# Local copy of test/gf180/gf180mcu_fd_io.lef with the duplicate macro bodies
# removed.  That file declares every one of its 14 macros twice with different
# geometry, and odb appends the second body to the first instead of replacing
# it, so gf180mcu_fd_io__dvdd ends up with the second body's Metal2 blanket
# (to local y 348.720) underneath the first body's pin openings (from local
# y 345.345).  Each body on its own keeps a legal 0.300 um gap.  The pad tests
# here need obstructions that are consistent with their own pins, so they read
# this copy; the odb behaviour is a separate issue.
VERSION 5.7 ;
  NOWIREEXTENSIONATPIN ON ;
  DIVIDERCHAR "/" ;
  BUSBITCHARS "[]" ;
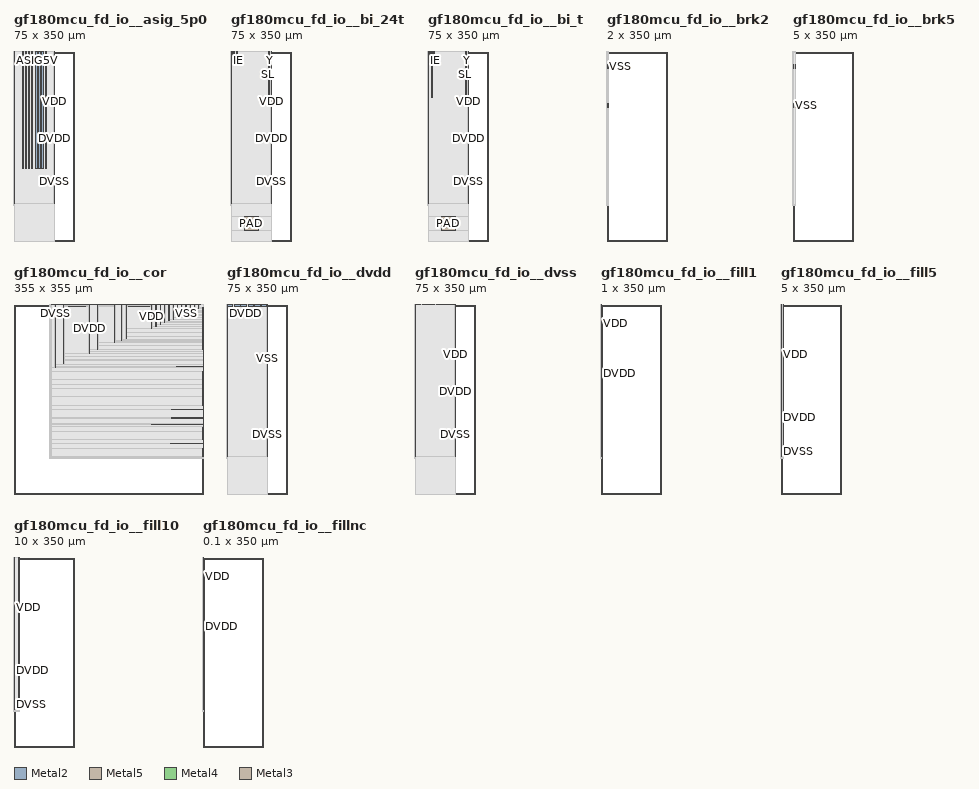
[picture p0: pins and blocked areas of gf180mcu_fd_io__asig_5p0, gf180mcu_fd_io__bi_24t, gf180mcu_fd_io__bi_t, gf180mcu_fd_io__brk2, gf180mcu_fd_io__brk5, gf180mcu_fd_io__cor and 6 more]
MACRO gf180mcu_fd_io__asig_5p0
  CLASS PAD INOUT ;
  FOREIGN gf180mcu_fd_io__asig_5p0 ;
  ORIGIN 0.000 0.000 ;
  SIZE 75.000 BY 350.000 ;
  SYMMETRY X Y R90 ;
  PIN ASIG5V
    DIRECTION INOUT ;
    USE SIGNAL ;
    PORT
      LAYER Metal2 ;
        RECT 15.340 134.370 17.880 350.000 ;
    END
    PORT
      LAYER Metal2 ;
        RECT 21.020 134.370 23.560 350.000 ;
    END
    PORT
      LAYER Metal2 ;
        RECT 26.700 134.370 29.240 350.000 ;
    END
    PORT
      LAYER Metal2 ;
        RECT 32.380 134.370 34.920 350.000 ;
    END
    PORT
      LAYER Metal2 ;
        RECT 40.080 134.370 42.620 350.000 ;
    END
    PORT
      LAYER Metal2 ;
        RECT 45.760 134.370 48.300 350.000 ;
    END
    PORT
      LAYER Metal2 ;
        RECT 51.440 134.370 53.980 350.000 ;
    END
    PORT
      LAYER Metal2 ;
        RECT 57.120 134.370 59.660 350.000 ;
    END
  END ASIG5V
  PIN DVDD
    DIRECTION INOUT ;
    USE POWER ;
    PORT
      LAYER Metal5 ;
        RECT 74.000 118.000 75.000 125.000 ;
    END
    PORT
      LAYER Metal5 ;
        RECT 74.000 182.000 75.000 197.000 ;
    END
    PORT
      LAYER Metal5 ;
        RECT 74.000 166.000 75.000 181.000 ;
    END
    PORT
      LAYER Metal5 ;
        RECT 74.000 150.000 75.000 165.000 ;
    END
    PORT
      LAYER Metal5 ;
        RECT 74.000 134.000 75.000 149.000 ;
    END
    PORT
      LAYER Metal5 ;
        RECT 74.000 214.000 75.000 229.000 ;
    END
    PORT
      LAYER Metal5 ;
        RECT 74.000 206.000 75.000 213.000 ;
    END
    PORT
      LAYER Metal5 ;
        RECT 74.000 278.000 75.000 285.000 ;
    END
    PORT
      LAYER Metal5 ;
        RECT 74.000 270.000 75.000 277.000 ;
    END
    PORT
      LAYER Metal5 ;
        RECT 74.000 262.000 75.000 269.000 ;
    END
    PORT
      LAYER Metal5 ;
        RECT 74.000 294.000 75.000 301.000 ;
    END
    PORT
      LAYER Metal5 ;
        RECT 74.000 334.000 75.000 341.000 ;
    END
    PORT
      LAYER Metal4 ;
        RECT 74.000 118.000 75.000 125.000 ;
    END
    PORT
      LAYER Metal4 ;
        RECT 74.000 182.000 75.000 197.000 ;
    END
    PORT
      LAYER Metal4 ;
        RECT 74.000 166.000 75.000 181.000 ;
    END
    PORT
      LAYER Metal4 ;
        RECT 74.000 150.000 75.000 165.000 ;
    END
    PORT
      LAYER Metal4 ;
        RECT 74.000 134.000 75.000 149.000 ;
    END
    PORT
      LAYER Metal4 ;
        RECT 74.000 214.000 75.000 229.000 ;
    END
    PORT
      LAYER Metal4 ;
        RECT 74.000 206.000 75.000 213.000 ;
    END
    PORT
      LAYER Metal4 ;
        RECT 74.000 278.000 75.000 285.000 ;
    END
    PORT
      LAYER Metal4 ;
        RECT 74.000 270.000 75.000 277.000 ;
    END
    PORT
      LAYER Metal4 ;
        RECT 74.000 262.000 75.000 269.000 ;
    END
    PORT
      LAYER Metal4 ;
        RECT 74.000 294.000 75.000 301.000 ;
    END
    PORT
      LAYER Metal4 ;
        RECT 74.000 334.000 75.000 341.000 ;
    END
    PORT
      LAYER Metal3 ;
        RECT 74.000 118.000 75.000 125.000 ;
    END
    PORT
      LAYER Metal3 ;
        RECT 74.000 182.000 75.000 197.000 ;
    END
    PORT
      LAYER Metal3 ;
        RECT 74.000 166.000 75.000 181.000 ;
    END
    PORT
      LAYER Metal3 ;
        RECT 74.000 150.000 75.000 165.000 ;
    END
    PORT
      LAYER Metal3 ;
        RECT 74.000 134.000 75.000 149.000 ;
    END
    PORT
      LAYER Metal3 ;
        RECT 74.000 214.000 75.000 229.000 ;
    END
    PORT
      LAYER Metal3 ;
        RECT 74.000 206.000 75.000 213.000 ;
    END
    PORT
      LAYER Metal3 ;
        RECT 74.000 278.000 75.000 285.000 ;
    END
    PORT
      LAYER Metal3 ;
        RECT 74.000 270.000 75.000 277.000 ;
    END
    PORT
      LAYER Metal3 ;
        RECT 74.000 262.000 75.000 269.000 ;
    END
    PORT
      LAYER Metal3 ;
        RECT 74.000 294.000 75.000 301.000 ;
    END
    PORT
      LAYER Metal3 ;
        RECT 74.000 334.000 75.000 341.000 ;
    END
    PORT
      LAYER Metal3 ;
        RECT 0.000 334.000 1.000 341.000 ;
    END
    PORT
      LAYER Metal3 ;
        RECT 0.000 294.000 1.000 301.000 ;
    END
    PORT
      LAYER Metal3 ;
        RECT 0.000 262.000 1.000 269.000 ;
    END
    PORT
      LAYER Metal3 ;
        RECT 0.000 270.000 1.000 277.000 ;
    END
    PORT
      LAYER Metal3 ;
        RECT 0.000 278.000 1.000 285.000 ;
    END
    PORT
      LAYER Metal3 ;
        RECT 0.000 206.000 1.000 213.000 ;
    END
    PORT
      LAYER Metal3 ;
        RECT 0.000 214.000 1.000 229.000 ;
    END
    PORT
      LAYER Metal3 ;
        RECT 0.000 134.000 1.000 149.000 ;
    END
    PORT
      LAYER Metal3 ;
        RECT 0.000 150.000 1.000 165.000 ;
    END
    PORT
      LAYER Metal3 ;
        RECT 0.000 166.000 1.000 181.000 ;
    END
    PORT
      LAYER Metal3 ;
        RECT 0.000 182.000 1.000 197.000 ;
    END
    PORT
      LAYER Metal5 ;
        RECT 0.000 334.000 1.000 341.000 ;
    END
    PORT
      LAYER Metal5 ;
        RECT 0.000 294.000 1.000 301.000 ;
    END
    PORT
      LAYER Metal5 ;
        RECT 0.000 262.000 1.000 269.000 ;
    END
    PORT
      LAYER Metal5 ;
        RECT 0.000 270.000 1.000 277.000 ;
    END
    PORT
      LAYER Metal5 ;
        RECT 0.000 278.000 1.000 285.000 ;
    END
    PORT
      LAYER Metal5 ;
        RECT 0.000 206.000 1.000 213.000 ;
    END
    PORT
      LAYER Metal5 ;
        RECT 0.000 214.000 1.000 229.000 ;
    END
    PORT
      LAYER Metal5 ;
        RECT 0.000 134.000 1.000 149.000 ;
    END
    PORT
      LAYER Metal5 ;
        RECT 0.000 150.000 1.000 165.000 ;
    END
    PORT
      LAYER Metal5 ;
        RECT 0.000 166.000 1.000 181.000 ;
    END
    PORT
      LAYER Metal5 ;
        RECT 0.000 182.000 1.000 197.000 ;
    END
    PORT
      LAYER Metal4 ;
        RECT 0.000 334.000 1.000 341.000 ;
    END
    PORT
      LAYER Metal4 ;
        RECT 0.000 294.000 1.000 301.000 ;
    END
    PORT
      LAYER Metal4 ;
        RECT 0.000 262.000 1.000 269.000 ;
    END
    PORT
      LAYER Metal4 ;
        RECT 0.000 270.000 1.000 277.000 ;
    END
    PORT
      LAYER Metal4 ;
        RECT 0.000 278.000 1.000 285.000 ;
    END
    PORT
      LAYER Metal4 ;
        RECT 0.000 206.000 1.000 213.000 ;
    END
    PORT
      LAYER Metal4 ;
        RECT 0.000 214.000 1.000 229.000 ;
    END
    PORT
      LAYER Metal4 ;
        RECT 0.000 134.000 1.000 149.000 ;
    END
    PORT
      LAYER Metal4 ;
        RECT 0.000 150.000 1.000 165.000 ;
    END
    PORT
      LAYER Metal4 ;
        RECT 0.000 166.000 1.000 181.000 ;
    END
    PORT
      LAYER Metal4 ;
        RECT 0.000 182.000 1.000 197.000 ;
    END
    PORT
      LAYER Metal4 ;
        RECT 0.000 118.000 1.000 125.000 ;
    END
    PORT
      LAYER Metal5 ;
        RECT 0.000 118.000 1.000 125.000 ;
    END
    PORT
      LAYER Metal3 ;
        RECT 0.000 118.000 1.000 125.000 ;
    END
  END DVDD
  PIN DVSS
    DIRECTION INOUT ;
    USE GROUND ;
    PORT
      LAYER Metal5 ;
        RECT 74.000 102.000 75.000 117.000 ;
    END
    PORT
      LAYER Metal5 ;
        RECT 74.000 86.000 75.000 101.000 ;
    END
    PORT
      LAYER Metal5 ;
        RECT 74.000 70.000 75.000 85.000 ;
    END
    PORT
      LAYER Metal5 ;
        RECT 74.000 126.000 75.000 133.000 ;
    END
    PORT
      LAYER Metal5 ;
        RECT 74.000 198.000 75.000 205.000 ;
    END
    PORT
      LAYER Metal5 ;
        RECT 74.000 230.000 75.000 245.000 ;
    END
    PORT
      LAYER Metal5 ;
        RECT 74.000 286.000 75.000 293.000 ;
    END
    PORT
      LAYER Metal5 ;
        RECT 74.000 302.000 75.000 309.000 ;
    END
    PORT
      LAYER Metal5 ;
        RECT 74.000 326.000 75.000 333.000 ;
    END
    PORT
      LAYER Metal5 ;
        RECT 74.000 342.000 75.000 348.390 ;
    END
    PORT
      LAYER Metal4 ;
        RECT 74.000 102.000 75.000 117.000 ;
    END
    PORT
      LAYER Metal4 ;
        RECT 74.000 86.000 75.000 101.000 ;
    END
    PORT
      LAYER Metal4 ;
        RECT 74.000 70.000 75.000 85.000 ;
    END
    PORT
      LAYER Metal4 ;
        RECT 74.000 126.000 75.000 133.000 ;
    END
    PORT
      LAYER Metal4 ;
        RECT 74.000 198.000 75.000 205.000 ;
    END
    PORT
      LAYER Metal4 ;
        RECT 74.000 230.000 75.000 245.000 ;
    END
    PORT
      LAYER Metal4 ;
        RECT 74.000 286.000 75.000 293.000 ;
    END
    PORT
      LAYER Metal4 ;
        RECT 74.000 302.000 75.000 309.000 ;
    END
    PORT
      LAYER Metal4 ;
        RECT 74.000 326.000 75.000 333.000 ;
    END
    PORT
      LAYER Metal4 ;
        RECT 74.000 342.000 75.000 348.390 ;
    END
    PORT
      LAYER Metal3 ;
        RECT 74.000 102.000 75.000 117.000 ;
    END
    PORT
      LAYER Metal3 ;
        RECT 74.000 86.000 75.000 101.000 ;
    END
    PORT
      LAYER Metal3 ;
        RECT 74.000 70.000 75.000 85.000 ;
    END
    PORT
      LAYER Metal3 ;
        RECT 74.000 126.000 75.000 133.000 ;
    END
    PORT
      LAYER Metal3 ;
        RECT 74.000 198.000 75.000 205.000 ;
    END
    PORT
      LAYER Metal3 ;
        RECT 74.000 230.000 75.000 245.000 ;
    END
    PORT
      LAYER Metal3 ;
        RECT 74.000 286.000 75.000 293.000 ;
    END
    PORT
      LAYER Metal3 ;
        RECT 74.000 302.000 75.000 309.000 ;
    END
    PORT
      LAYER Metal3 ;
        RECT 74.000 326.000 75.000 333.000 ;
    END
    PORT
      LAYER Metal3 ;
        RECT 74.000 342.000 75.000 348.390 ;
    END
    PORT
      LAYER Metal3 ;
        RECT 0.000 342.000 1.000 348.390 ;
    END
    PORT
      LAYER Metal3 ;
        RECT 0.000 326.000 1.000 333.000 ;
    END
    PORT
      LAYER Metal3 ;
        RECT 0.000 302.000 1.000 309.000 ;
    END
    PORT
      LAYER Metal3 ;
        RECT 0.000 286.000 1.000 293.000 ;
    END
    PORT
      LAYER Metal3 ;
        RECT 0.000 230.000 1.000 245.000 ;
    END
    PORT
      LAYER Metal3 ;
        RECT 0.000 198.000 1.000 205.000 ;
    END
    PORT
      LAYER Metal3 ;
        RECT 0.000 126.000 1.000 133.000 ;
    END
    PORT
      LAYER Metal3 ;
        RECT 0.000 70.000 1.000 85.000 ;
    END
    PORT
      LAYER Metal3 ;
        RECT 0.000 86.000 1.000 101.000 ;
    END
    PORT
      LAYER Metal5 ;
        RECT 0.000 342.000 1.000 348.390 ;
    END
    PORT
      LAYER Metal5 ;
        RECT 0.000 326.000 1.000 333.000 ;
    END
    PORT
      LAYER Metal5 ;
        RECT 0.000 302.000 1.000 309.000 ;
    END
    PORT
      LAYER Metal5 ;
        RECT 0.000 286.000 1.000 293.000 ;
    END
    PORT
      LAYER Metal5 ;
        RECT 0.000 230.000 1.000 245.000 ;
    END
    PORT
      LAYER Metal5 ;
        RECT 0.000 198.000 1.000 205.000 ;
    END
    PORT
      LAYER Metal5 ;
        RECT 0.000 126.000 1.000 133.000 ;
    END
    PORT
      LAYER Metal5 ;
        RECT 0.000 70.000 1.000 85.000 ;
    END
    PORT
      LAYER Metal5 ;
        RECT 0.000 86.000 1.000 101.000 ;
    END
    PORT
      LAYER Metal4 ;
        RECT 0.000 342.000 1.000 348.390 ;
    END
    PORT
      LAYER Metal4 ;
        RECT 0.000 326.000 1.000 333.000 ;
    END
    PORT
      LAYER Metal4 ;
        RECT 0.000 302.000 1.000 309.000 ;
    END
    PORT
      LAYER Metal4 ;
        RECT 0.000 286.000 1.000 293.000 ;
    END
    PORT
      LAYER Metal4 ;
        RECT 0.000 230.000 1.000 245.000 ;
    END
    PORT
      LAYER Metal4 ;
        RECT 0.000 198.000 1.000 205.000 ;
    END
    PORT
      LAYER Metal4 ;
        RECT 0.000 126.000 1.000 133.000 ;
    END
    PORT
      LAYER Metal4 ;
        RECT 0.000 70.000 1.000 85.000 ;
    END
    PORT
      LAYER Metal4 ;
        RECT 0.000 86.000 1.000 101.000 ;
    END
    PORT
      LAYER Metal4 ;
        RECT 0.000 102.000 1.000 117.000 ;
    END
    PORT
      LAYER Metal5 ;
        RECT 0.000 102.000 1.000 117.000 ;
    END
    PORT
      LAYER Metal3 ;
        RECT 0.000 102.000 1.000 117.000 ;
    END
  END DVSS
  PIN VDD
    DIRECTION INOUT ;
    USE POWER ;
    PORT
      LAYER Metal5 ;
        RECT 74.000 254.000 75.000 261.000 ;
    END
    PORT
      LAYER Metal5 ;
        RECT 74.000 310.000 75.000 317.000 ;
    END
    PORT
      LAYER Metal4 ;
        RECT 74.000 254.000 75.000 261.000 ;
    END
    PORT
      LAYER Metal4 ;
        RECT 74.000 310.000 75.000 317.000 ;
    END
    PORT
      LAYER Metal3 ;
        RECT 74.000 254.000 75.000 261.000 ;
    END
    PORT
      LAYER Metal3 ;
        RECT 74.000 310.000 75.000 317.000 ;
    END
    PORT
      LAYER Metal3 ;
        RECT 0.000 310.000 1.000 317.000 ;
    END
    PORT
      LAYER Metal5 ;
        RECT 0.000 310.000 1.000 317.000 ;
    END
    PORT
      LAYER Metal4 ;
        RECT 0.000 310.000 1.000 317.000 ;
    END
    PORT
      LAYER Metal4 ;
        RECT 0.000 254.000 1.000 261.000 ;
    END
    PORT
      LAYER Metal5 ;
        RECT 0.000 254.000 1.000 261.000 ;
    END
    PORT
      LAYER Metal3 ;
        RECT 0.000 254.000 1.000 261.000 ;
    END
  END VDD
  PIN VSS
    DIRECTION INOUT ;
    USE GROUND ;
    PORT
      LAYER Metal5 ;
        RECT 74.000 246.000 75.000 253.000 ;
    END
    PORT
      LAYER Metal5 ;
        RECT 74.000 318.000 75.000 325.000 ;
    END
    PORT
      LAYER Metal4 ;
        RECT 74.000 246.000 75.000 253.000 ;
    END
    PORT
      LAYER Metal4 ;
        RECT 74.000 318.000 75.000 325.000 ;
    END
    PORT
      LAYER Metal3 ;
        RECT 74.000 246.000 75.000 253.000 ;
    END
    PORT
      LAYER Metal3 ;
        RECT 74.000 318.000 75.000 325.000 ;
    END
    PORT
      LAYER Metal3 ;
        RECT 0.000 318.000 1.000 325.000 ;
    END
    PORT
      LAYER Metal5 ;
        RECT 0.000 318.000 1.000 325.000 ;
    END
    PORT
      LAYER Metal4 ;
        RECT 0.000 318.000 1.000 325.000 ;
    END
    PORT
      LAYER Metal4 ;
        RECT 0.000 246.000 1.000 253.000 ;
    END
    PORT
      LAYER Metal5 ;
        RECT 0.000 246.000 1.000 253.000 ;
    END
    PORT
      LAYER Metal3 ;
        RECT 0.000 246.000 1.000 253.000 ;
    END
  END VSS
  OBS
      LAYER Metal1 ;
        RECT -0.160 65.540 75.160 349.785 ;
      LAYER Metal2 ;
        RECT 0.000 134.070 15.040 348.390 ;
        RECT 18.180 134.070 20.720 348.390 ;
        RECT 23.860 134.070 26.400 348.390 ;
        RECT 29.540 134.070 32.080 348.390 ;
        RECT 35.220 134.070 39.780 348.390 ;
        RECT 42.920 134.070 45.460 348.390 ;
        RECT 48.600 134.070 51.140 348.390 ;
        RECT 54.280 134.070 56.820 348.390 ;
        RECT 59.960 134.070 75.000 348.390 ;
        RECT 0.000 0.000 75.000 134.070 ;
      LAYER Metal3 ;
        RECT 1.300 341.700 73.700 348.390 ;
        RECT 1.000 341.300 74.000 341.700 ;
        RECT 1.300 333.700 73.700 341.300 ;
        RECT 1.000 333.300 74.000 333.700 ;
        RECT 1.300 325.700 73.700 333.300 ;
        RECT 1.000 325.300 74.000 325.700 ;
        RECT 1.300 317.700 73.700 325.300 ;
        RECT 1.000 317.300 74.000 317.700 ;
        RECT 1.300 309.700 73.700 317.300 ;
        RECT 1.000 309.300 74.000 309.700 ;
        RECT 1.300 301.700 73.700 309.300 ;
        RECT 1.000 301.300 74.000 301.700 ;
        RECT 1.300 293.700 73.700 301.300 ;
        RECT 1.000 293.300 74.000 293.700 ;
        RECT 1.300 285.700 73.700 293.300 ;
        RECT 1.000 285.300 74.000 285.700 ;
        RECT 1.300 277.700 73.700 285.300 ;
        RECT 1.000 277.300 74.000 277.700 ;
        RECT 1.300 269.700 73.700 277.300 ;
        RECT 1.000 269.300 74.000 269.700 ;
        RECT 1.300 261.700 73.700 269.300 ;
        RECT 1.000 261.300 74.000 261.700 ;
        RECT 1.300 253.700 73.700 261.300 ;
        RECT 1.000 253.300 74.000 253.700 ;
        RECT 1.300 245.700 73.700 253.300 ;
        RECT 1.000 245.300 74.000 245.700 ;
        RECT 1.300 229.700 73.700 245.300 ;
        RECT 1.000 229.300 74.000 229.700 ;
        RECT 1.300 213.700 73.700 229.300 ;
        RECT 1.000 213.300 74.000 213.700 ;
        RECT 1.300 205.700 73.700 213.300 ;
        RECT 1.000 205.300 74.000 205.700 ;
        RECT 1.300 197.700 73.700 205.300 ;
        RECT 1.000 197.300 74.000 197.700 ;
        RECT 1.300 181.700 73.700 197.300 ;
        RECT 1.000 181.300 74.000 181.700 ;
        RECT 1.300 165.700 73.700 181.300 ;
        RECT 1.000 165.300 74.000 165.700 ;
        RECT 1.300 149.700 73.700 165.300 ;
        RECT 1.000 149.300 74.000 149.700 ;
        RECT 1.300 133.700 73.700 149.300 ;
        RECT 1.000 133.300 74.000 133.700 ;
        RECT 1.300 125.700 73.700 133.300 ;
        RECT 1.000 125.300 74.000 125.700 ;
        RECT 1.300 117.700 73.700 125.300 ;
        RECT 1.000 117.300 74.000 117.700 ;
        RECT 1.300 101.700 73.700 117.300 ;
        RECT 1.000 101.300 74.000 101.700 ;
        RECT 1.300 85.700 73.700 101.300 ;
        RECT 1.000 85.300 74.000 85.700 ;
        RECT 1.300 69.700 73.700 85.300 ;
        RECT 1.000 0.000 74.000 69.700 ;
      LAYER Metal4 ;
        RECT 1.300 341.700 73.700 348.390 ;
        RECT 1.000 341.300 74.000 341.700 ;
        RECT 1.300 333.700 73.700 341.300 ;
        RECT 1.000 333.300 74.000 333.700 ;
        RECT 1.300 325.700 73.700 333.300 ;
        RECT 1.000 325.300 74.000 325.700 ;
        RECT 1.300 317.700 73.700 325.300 ;
        RECT 1.000 317.300 74.000 317.700 ;
        RECT 1.300 309.700 73.700 317.300 ;
        RECT 1.000 309.300 74.000 309.700 ;
        RECT 1.300 301.700 73.700 309.300 ;
        RECT 1.000 301.300 74.000 301.700 ;
        RECT 1.300 293.700 73.700 301.300 ;
        RECT 1.000 293.300 74.000 293.700 ;
        RECT 1.300 285.700 73.700 293.300 ;
        RECT 1.000 285.300 74.000 285.700 ;
        RECT 1.300 277.700 73.700 285.300 ;
        RECT 1.000 277.300 74.000 277.700 ;
        RECT 1.300 269.700 73.700 277.300 ;
        RECT 1.000 269.300 74.000 269.700 ;
        RECT 1.300 261.700 73.700 269.300 ;
        RECT 1.000 261.300 74.000 261.700 ;
        RECT 1.300 253.700 73.700 261.300 ;
        RECT 1.000 253.300 74.000 253.700 ;
        RECT 1.300 245.700 73.700 253.300 ;
        RECT 1.000 245.300 74.000 245.700 ;
        RECT 1.300 229.700 73.700 245.300 ;
        RECT 1.000 229.300 74.000 229.700 ;
        RECT 1.300 213.700 73.700 229.300 ;
        RECT 1.000 213.300 74.000 213.700 ;
        RECT 1.300 205.700 73.700 213.300 ;
        RECT 1.000 205.300 74.000 205.700 ;
        RECT 1.300 197.700 73.700 205.300 ;
        RECT 1.000 197.300 74.000 197.700 ;
        RECT 1.300 181.700 73.700 197.300 ;
        RECT 1.000 181.300 74.000 181.700 ;
        RECT 1.300 165.700 73.700 181.300 ;
        RECT 1.000 165.300 74.000 165.700 ;
        RECT 1.300 149.700 73.700 165.300 ;
        RECT 1.000 149.300 74.000 149.700 ;
        RECT 1.300 133.700 73.700 149.300 ;
        RECT 1.000 133.300 74.000 133.700 ;
        RECT 1.300 125.700 73.700 133.300 ;
        RECT 1.000 125.300 74.000 125.700 ;
        RECT 1.300 117.700 73.700 125.300 ;
        RECT 1.000 117.300 74.000 117.700 ;
        RECT 1.300 101.700 73.700 117.300 ;
        RECT 1.000 101.300 74.000 101.700 ;
        RECT 1.300 85.700 73.700 101.300 ;
        RECT 1.000 85.300 74.000 85.700 ;
        RECT 1.300 69.700 73.700 85.300 ;
        RECT 1.000 0.000 74.000 69.700 ;
      LAYER Metal5 ;
        RECT 1.500 69.500 73.500 348.390 ;
        RECT 1.000 0.000 74.000 69.500 ;
  END
END gf180mcu_fd_io__asig_5p0

#--------EOF---------

#--------EOF---------

MACRO gf180mcu_fd_io__bi_24t
  CLASS PAD INOUT ;
  FOREIGN gf180mcu_fd_io__bi_24t ;
  ORIGIN 0.000 0.000 ;
  SIZE 75.000 BY 350.000 ;
  SYMMETRY X Y R90 ;
  PIN A
    DIRECTION INPUT ;
    USE SIGNAL ;
    PORT
      LAYER Metal2 ;
        RECT 69.400 264.310 69.780 350.000 ;
    END
  END A
  PIN CS
    DIRECTION INPUT ;
    USE SIGNAL ;
    PORT
      LAYER Metal2 ;
        RECT 3.360 328.395 3.740 350.000 ;
    END
  END CS
  PIN DVDD
    DIRECTION INOUT ;
    USE POWER ;
    PORT
      LAYER Metal5 ;
        RECT 74.000 118.000 75.000 125.000 ;
    END
    PORT
      LAYER Metal5 ;
        RECT 74.000 182.000 75.000 197.000 ;
    END
    PORT
      LAYER Metal5 ;
        RECT 74.000 166.000 75.000 181.000 ;
    END
    PORT
      LAYER Metal5 ;
        RECT 74.000 150.000 75.000 165.000 ;
    END
    PORT
      LAYER Metal5 ;
        RECT 74.000 134.000 75.000 149.000 ;
    END
    PORT
      LAYER Metal5 ;
        RECT 74.000 214.000 75.000 229.000 ;
    END
    PORT
      LAYER Metal5 ;
        RECT 74.000 206.000 75.000 213.000 ;
    END
    PORT
      LAYER Metal5 ;
        RECT 74.000 278.000 75.000 285.000 ;
    END
    PORT
      LAYER Metal5 ;
        RECT 74.000 270.000 75.000 277.000 ;
    END
    PORT
      LAYER Metal5 ;
        RECT 74.000 262.000 75.000 269.000 ;
    END
    PORT
      LAYER Metal5 ;
        RECT 74.000 294.000 75.000 301.000 ;
    END
    PORT
      LAYER Metal5 ;
        RECT 74.000 334.000 75.000 341.000 ;
    END
    PORT
      LAYER Metal4 ;
        RECT 74.000 118.000 75.000 125.000 ;
    END
    PORT
      LAYER Metal4 ;
        RECT 74.000 182.000 75.000 197.000 ;
    END
    PORT
      LAYER Metal4 ;
        RECT 74.000 166.000 75.000 181.000 ;
    END
    PORT
      LAYER Metal4 ;
        RECT 74.000 150.000 75.000 165.000 ;
    END
    PORT
      LAYER Metal4 ;
        RECT 74.000 134.000 75.000 149.000 ;
    END
    PORT
      LAYER Metal4 ;
        RECT 74.000 214.000 75.000 229.000 ;
    END
    PORT
      LAYER Metal4 ;
        RECT 74.000 206.000 75.000 213.000 ;
    END
    PORT
      LAYER Metal4 ;
        RECT 74.000 278.000 75.000 285.000 ;
    END
    PORT
      LAYER Metal4 ;
        RECT 74.000 270.000 75.000 277.000 ;
    END
    PORT
      LAYER Metal4 ;
        RECT 74.000 262.000 75.000 269.000 ;
    END
    PORT
      LAYER Metal4 ;
        RECT 74.000 294.000 75.000 301.000 ;
    END
    PORT
      LAYER Metal4 ;
        RECT 74.000 334.000 75.000 341.000 ;
    END
    PORT
      LAYER Metal3 ;
        RECT 74.000 118.000 75.000 125.000 ;
    END
    PORT
      LAYER Metal3 ;
        RECT 74.000 182.000 75.000 197.000 ;
    END
    PORT
      LAYER Metal3 ;
        RECT 74.000 166.000 75.000 181.000 ;
    END
    PORT
      LAYER Metal3 ;
        RECT 74.000 150.000 75.000 165.000 ;
    END
    PORT
      LAYER Metal3 ;
        RECT 74.000 134.000 75.000 149.000 ;
    END
    PORT
      LAYER Metal3 ;
        RECT 74.000 214.000 75.000 229.000 ;
    END
    PORT
      LAYER Metal3 ;
        RECT 74.000 206.000 75.000 213.000 ;
    END
    PORT
      LAYER Metal3 ;
        RECT 74.000 278.000 75.000 285.000 ;
    END
    PORT
      LAYER Metal3 ;
        RECT 74.000 270.000 75.000 277.000 ;
    END
    PORT
      LAYER Metal3 ;
        RECT 74.000 262.000 75.000 269.000 ;
    END
    PORT
      LAYER Metal3 ;
        RECT 74.000 294.000 75.000 301.000 ;
    END
    PORT
      LAYER Metal3 ;
        RECT 74.000 334.000 75.000 341.000 ;
    END
    PORT
      LAYER Metal3 ;
        RECT 0.000 334.000 1.000 341.000 ;
    END
    PORT
      LAYER Metal3 ;
        RECT 0.000 294.000 1.000 301.000 ;
    END
    PORT
      LAYER Metal3 ;
        RECT 0.000 262.000 1.000 269.000 ;
    END
    PORT
      LAYER Metal3 ;
        RECT 0.000 270.000 1.000 277.000 ;
    END
    PORT
      LAYER Metal3 ;
        RECT 0.000 278.000 1.000 285.000 ;
    END
    PORT
      LAYER Metal3 ;
        RECT 0.000 206.000 1.000 213.000 ;
    END
    PORT
      LAYER Metal3 ;
        RECT 0.000 214.000 1.000 229.000 ;
    END
    PORT
      LAYER Metal3 ;
        RECT 0.000 134.000 1.000 149.000 ;
    END
    PORT
      LAYER Metal3 ;
        RECT 0.000 150.000 1.000 165.000 ;
    END
    PORT
      LAYER Metal3 ;
        RECT 0.000 166.000 1.000 181.000 ;
    END
    PORT
      LAYER Metal3 ;
        RECT 0.000 182.000 1.000 197.000 ;
    END
    PORT
      LAYER Metal4 ;
        RECT 0.000 334.000 1.000 341.000 ;
    END
    PORT
      LAYER Metal4 ;
        RECT 0.000 294.000 1.000 301.000 ;
    END
    PORT
      LAYER Metal4 ;
        RECT 0.000 262.000 1.000 269.000 ;
    END
    PORT
      LAYER Metal4 ;
        RECT 0.000 270.000 1.000 277.000 ;
    END
    PORT
      LAYER Metal4 ;
        RECT 0.000 278.000 1.000 285.000 ;
    END
    PORT
      LAYER Metal4 ;
        RECT 0.000 206.000 1.000 213.000 ;
    END
    PORT
      LAYER Metal4 ;
        RECT 0.000 214.000 1.000 229.000 ;
    END
    PORT
      LAYER Metal4 ;
        RECT 0.000 134.000 1.000 149.000 ;
    END
    PORT
      LAYER Metal4 ;
        RECT 0.000 150.000 1.000 165.000 ;
    END
    PORT
      LAYER Metal4 ;
        RECT 0.000 166.000 1.000 181.000 ;
    END
    PORT
      LAYER Metal4 ;
        RECT 0.000 182.000 1.000 197.000 ;
    END
    PORT
      LAYER Metal5 ;
        RECT 0.000 334.000 1.000 341.000 ;
    END
    PORT
      LAYER Metal5 ;
        RECT 0.000 294.000 1.000 301.000 ;
    END
    PORT
      LAYER Metal5 ;
        RECT 0.000 262.000 1.000 269.000 ;
    END
    PORT
      LAYER Metal5 ;
        RECT 0.000 270.000 1.000 277.000 ;
    END
    PORT
      LAYER Metal5 ;
        RECT 0.000 278.000 1.000 285.000 ;
    END
    PORT
      LAYER Metal5 ;
        RECT 0.000 206.000 1.000 213.000 ;
    END
    PORT
      LAYER Metal5 ;
        RECT 0.000 214.000 1.000 229.000 ;
    END
    PORT
      LAYER Metal5 ;
        RECT 0.000 134.000 1.000 149.000 ;
    END
    PORT
      LAYER Metal5 ;
        RECT 0.000 150.000 1.000 165.000 ;
    END
    PORT
      LAYER Metal5 ;
        RECT 0.000 166.000 1.000 181.000 ;
    END
    PORT
      LAYER Metal5 ;
        RECT 0.000 182.000 1.000 197.000 ;
    END
    PORT
      LAYER Metal5 ;
        RECT 0.000 118.000 1.000 125.000 ;
    END
    PORT
      LAYER Metal4 ;
        RECT 0.000 118.000 1.000 125.000 ;
    END
    PORT
      LAYER Metal3 ;
        RECT 0.000 118.000 1.000 125.000 ;
    END
  END DVDD
  PIN DVSS
    DIRECTION INOUT ;
    USE GROUND ;
    PORT
      LAYER Metal5 ;
        RECT 74.000 102.000 75.000 117.000 ;
    END
    PORT
      LAYER Metal5 ;
        RECT 74.000 86.000 75.000 101.000 ;
    END
    PORT
      LAYER Metal5 ;
        RECT 74.000 70.000 75.000 85.000 ;
    END
    PORT
      LAYER Metal5 ;
        RECT 74.000 126.000 75.000 133.000 ;
    END
    PORT
      LAYER Metal5 ;
        RECT 74.000 198.000 75.000 205.000 ;
    END
    PORT
      LAYER Metal5 ;
        RECT 74.000 230.000 75.000 245.000 ;
    END
    PORT
      LAYER Metal5 ;
        RECT 74.000 286.000 75.000 293.000 ;
    END
    PORT
      LAYER Metal5 ;
        RECT 74.000 302.000 75.000 309.000 ;
    END
    PORT
      LAYER Metal5 ;
        RECT 74.000 326.000 75.000 333.000 ;
    END
    PORT
      LAYER Metal5 ;
        RECT 74.000 342.000 75.000 348.390 ;
    END
    PORT
      LAYER Metal4 ;
        RECT 74.000 102.000 75.000 117.000 ;
    END
    PORT
      LAYER Metal4 ;
        RECT 74.000 86.000 75.000 101.000 ;
    END
    PORT
      LAYER Metal4 ;
        RECT 74.000 70.000 75.000 85.000 ;
    END
    PORT
      LAYER Metal4 ;
        RECT 74.000 126.000 75.000 133.000 ;
    END
    PORT
      LAYER Metal4 ;
        RECT 74.000 198.000 75.000 205.000 ;
    END
    PORT
      LAYER Metal4 ;
        RECT 74.000 230.000 75.000 245.000 ;
    END
    PORT
      LAYER Metal4 ;
        RECT 74.000 286.000 75.000 293.000 ;
    END
    PORT
      LAYER Metal4 ;
        RECT 74.000 302.000 75.000 309.000 ;
    END
    PORT
      LAYER Metal4 ;
        RECT 74.000 326.000 75.000 333.000 ;
    END
    PORT
      LAYER Metal4 ;
        RECT 74.000 342.000 75.000 348.390 ;
    END
    PORT
      LAYER Metal3 ;
        RECT 74.000 102.000 75.000 117.000 ;
    END
    PORT
      LAYER Metal3 ;
        RECT 74.000 86.000 75.000 101.000 ;
    END
    PORT
      LAYER Metal3 ;
        RECT 74.000 70.000 75.000 85.000 ;
    END
    PORT
      LAYER Metal3 ;
        RECT 74.000 126.000 75.000 133.000 ;
    END
    PORT
      LAYER Metal3 ;
        RECT 74.000 198.000 75.000 205.000 ;
    END
    PORT
      LAYER Metal3 ;
        RECT 74.000 230.000 75.000 245.000 ;
    END
    PORT
      LAYER Metal3 ;
        RECT 74.000 286.000 75.000 293.000 ;
    END
    PORT
      LAYER Metal3 ;
        RECT 74.000 302.000 75.000 309.000 ;
    END
    PORT
      LAYER Metal3 ;
        RECT 74.000 326.000 75.000 333.000 ;
    END
    PORT
      LAYER Metal3 ;
        RECT 74.000 342.000 75.000 348.390 ;
    END
    PORT
      LAYER Metal3 ;
        RECT 0.000 342.000 1.000 348.390 ;
    END
    PORT
      LAYER Metal3 ;
        RECT 0.000 326.000 1.000 333.000 ;
    END
    PORT
      LAYER Metal3 ;
        RECT 0.000 302.000 1.000 309.000 ;
    END
    PORT
      LAYER Metal3 ;
        RECT 0.000 286.000 1.000 293.000 ;
    END
    PORT
      LAYER Metal3 ;
        RECT 0.000 230.000 1.000 245.000 ;
    END
    PORT
      LAYER Metal3 ;
        RECT 0.000 198.000 1.000 205.000 ;
    END
    PORT
      LAYER Metal3 ;
        RECT 0.000 126.000 1.000 133.000 ;
    END
    PORT
      LAYER Metal3 ;
        RECT 0.000 70.000 1.000 85.000 ;
    END
    PORT
      LAYER Metal3 ;
        RECT 0.000 86.000 1.000 101.000 ;
    END
    PORT
      LAYER Metal4 ;
        RECT 0.000 342.000 1.000 348.390 ;
    END
    PORT
      LAYER Metal4 ;
        RECT 0.000 326.000 1.000 333.000 ;
    END
    PORT
      LAYER Metal4 ;
        RECT 0.000 302.000 1.000 309.000 ;
    END
    PORT
      LAYER Metal4 ;
        RECT 0.000 286.000 1.000 293.000 ;
    END
    PORT
      LAYER Metal4 ;
        RECT 0.000 230.000 1.000 245.000 ;
    END
    PORT
      LAYER Metal4 ;
        RECT 0.000 198.000 1.000 205.000 ;
    END
    PORT
      LAYER Metal4 ;
        RECT 0.000 126.000 1.000 133.000 ;
    END
    PORT
      LAYER Metal4 ;
        RECT 0.000 70.000 1.000 85.000 ;
    END
    PORT
      LAYER Metal4 ;
        RECT 0.000 86.000 1.000 101.000 ;
    END
    PORT
      LAYER Metal5 ;
        RECT 0.000 342.000 1.000 348.390 ;
    END
    PORT
      LAYER Metal5 ;
        RECT 0.000 326.000 1.000 333.000 ;
    END
    PORT
      LAYER Metal5 ;
        RECT 0.000 302.000 1.000 309.000 ;
    END
    PORT
      LAYER Metal5 ;
        RECT 0.000 286.000 1.000 293.000 ;
    END
    PORT
      LAYER Metal5 ;
        RECT 0.000 230.000 1.000 245.000 ;
    END
    PORT
      LAYER Metal5 ;
        RECT 0.000 198.000 1.000 205.000 ;
    END
    PORT
      LAYER Metal5 ;
        RECT 0.000 126.000 1.000 133.000 ;
    END
    PORT
      LAYER Metal5 ;
        RECT 0.000 70.000 1.000 85.000 ;
    END
    PORT
      LAYER Metal5 ;
        RECT 0.000 86.000 1.000 101.000 ;
    END
    PORT
      LAYER Metal5 ;
        RECT 0.000 102.000 1.000 117.000 ;
    END
    PORT
      LAYER Metal4 ;
        RECT 0.000 102.000 1.000 117.000 ;
    END
    PORT
      LAYER Metal3 ;
        RECT 0.000 102.000 1.000 117.000 ;
    END
  END DVSS
  PIN IE
    DIRECTION INPUT ;
    USE SIGNAL ;
    PORT
      LAYER Metal2 ;
        RECT 11.385 334.770 11.765 350.000 ;
    END
  END IE
  PIN OE
    DIRECTION INPUT ;
    USE SIGNAL ;
    PORT
      LAYER Metal2 ;
        RECT 70.130 266.190 70.510 350.000 ;
    END
  END OE
  PIN PAD
    DIRECTION INOUT ;
    USE SIGNAL ;
    PORT
      LAYER Metal5 ;
        RECT 25.000 20.000 50.000 45.000 ;
    END
  END PAD
  PIN PD
    DIRECTION INPUT ;
    USE SIGNAL ;
    PORT
      LAYER Metal2 ;
        RECT 10.330 329.950 10.710 350.000 ;
    END
  END PD
  PIN PU
    DIRECTION INPUT ;
    USE SIGNAL ;
    PORT
      LAYER Metal2 ;
        RECT 5.965 330.270 6.345 350.000 ;
    END
  END PU
  PIN SL
    DIRECTION INPUT ;
    USE SIGNAL ;
    PORT
      LAYER Metal2 ;
        RECT 68.670 264.990 69.050 350.000 ;
    END
  END SL
  PIN VDD
    DIRECTION INOUT ;
    USE POWER ;
    PORT
      LAYER Metal5 ;
        RECT 74.000 254.000 75.000 261.000 ;
    END
    PORT
      LAYER Metal5 ;
        RECT 74.000 310.000 75.000 317.000 ;
    END
    PORT
      LAYER Metal4 ;
        RECT 74.000 254.000 75.000 261.000 ;
    END
    PORT
      LAYER Metal4 ;
        RECT 74.000 310.000 75.000 317.000 ;
    END
    PORT
      LAYER Metal3 ;
        RECT 74.000 254.000 75.000 261.000 ;
    END
    PORT
      LAYER Metal3 ;
        RECT 74.000 310.000 75.000 317.000 ;
    END
    PORT
      LAYER Metal3 ;
        RECT 0.000 310.000 1.000 317.000 ;
    END
    PORT
      LAYER Metal4 ;
        RECT 0.000 310.000 1.000 317.000 ;
    END
    PORT
      LAYER Metal5 ;
        RECT 0.000 310.000 1.000 317.000 ;
    END
    PORT
      LAYER Metal5 ;
        RECT 0.000 254.000 1.000 261.000 ;
    END
    PORT
      LAYER Metal4 ;
        RECT 0.000 254.000 1.000 261.000 ;
    END
    PORT
      LAYER Metal3 ;
        RECT 0.000 254.000 1.000 261.000 ;
    END
  END VDD
  PIN VSS
    DIRECTION INOUT ;
    USE GROUND ;
    PORT
      LAYER Metal5 ;
        RECT 74.000 246.000 75.000 253.000 ;
    END
    PORT
      LAYER Metal5 ;
        RECT 74.000 318.000 75.000 325.000 ;
    END
    PORT
      LAYER Metal4 ;
        RECT 74.000 246.000 75.000 253.000 ;
    END
    PORT
      LAYER Metal4 ;
        RECT 74.000 318.000 75.000 325.000 ;
    END
    PORT
      LAYER Metal3 ;
        RECT 74.000 246.000 75.000 253.000 ;
    END
    PORT
      LAYER Metal3 ;
        RECT 74.000 318.000 75.000 325.000 ;
    END
    PORT
      LAYER Metal3 ;
        RECT 0.000 318.000 1.000 325.000 ;
    END
    PORT
      LAYER Metal4 ;
        RECT 0.000 318.000 1.000 325.000 ;
    END
    PORT
      LAYER Metal5 ;
        RECT 0.000 318.000 1.000 325.000 ;
    END
    PORT
      LAYER Metal5 ;
        RECT 0.000 246.000 1.000 253.000 ;
    END
    PORT
      LAYER Metal4 ;
        RECT 0.000 246.000 1.000 253.000 ;
    END
    PORT
      LAYER Metal3 ;
        RECT 0.000 246.000 1.000 253.000 ;
    END
  END VSS
  PIN Y
    DIRECTION OUTPUT ;
    USE SIGNAL ;
    PORT
      LAYER Metal2 ;
        RECT 70.860 319.750 71.240 350.000 ;
    END
  END Y
  OBS
      LAYER Metal1 ;
        RECT -0.160 65.540 75.160 349.785 ;
      LAYER Metal2 ;
        RECT 0.000 328.095 3.060 348.225 ;
        RECT 4.040 329.970 5.665 348.225 ;
        RECT 6.645 329.970 10.030 348.225 ;
        RECT 4.040 329.650 10.030 329.970 ;
        RECT 11.010 334.470 11.085 348.225 ;
        RECT 12.065 334.470 68.370 348.225 ;
        RECT 11.010 329.650 68.370 334.470 ;
        RECT 4.040 328.095 68.370 329.650 ;
        RECT 0.000 264.690 68.370 328.095 ;
        RECT 71.540 319.450 75.000 348.225 ;
        RECT 70.810 265.890 75.000 319.450 ;
        RECT 0.000 264.010 69.100 264.690 ;
        RECT 70.080 264.010 75.000 265.890 ;
        RECT 0.000 0.000 75.000 264.010 ;
      LAYER Metal3 ;
        RECT 1.300 341.700 73.700 348.390 ;
        RECT 1.000 341.300 74.000 341.700 ;
        RECT 1.300 333.700 73.700 341.300 ;
        RECT 1.000 333.300 74.000 333.700 ;
        RECT 1.300 325.700 73.700 333.300 ;
        RECT 1.000 325.300 74.000 325.700 ;
        RECT 1.300 317.700 73.700 325.300 ;
        RECT 1.000 317.300 74.000 317.700 ;
        RECT 1.300 309.700 73.700 317.300 ;
        RECT 1.000 309.300 74.000 309.700 ;
        RECT 1.300 301.700 73.700 309.300 ;
        RECT 1.000 301.300 74.000 301.700 ;
        RECT 1.300 293.700 73.700 301.300 ;
        RECT 1.000 293.300 74.000 293.700 ;
        RECT 1.300 285.700 73.700 293.300 ;
        RECT 1.000 285.300 74.000 285.700 ;
        RECT 1.300 277.700 73.700 285.300 ;
        RECT 1.000 277.300 74.000 277.700 ;
        RECT 1.300 269.700 73.700 277.300 ;
        RECT 1.000 269.300 74.000 269.700 ;
        RECT 1.300 261.700 73.700 269.300 ;
        RECT 1.000 261.300 74.000 261.700 ;
        RECT 1.300 253.700 73.700 261.300 ;
        RECT 1.000 253.300 74.000 253.700 ;
        RECT 1.300 245.700 73.700 253.300 ;
        RECT 1.000 245.300 74.000 245.700 ;
        RECT 1.300 229.700 73.700 245.300 ;
        RECT 1.000 229.300 74.000 229.700 ;
        RECT 1.300 213.700 73.700 229.300 ;
        RECT 1.000 213.300 74.000 213.700 ;
        RECT 1.300 205.700 73.700 213.300 ;
        RECT 1.000 205.300 74.000 205.700 ;
        RECT 1.300 197.700 73.700 205.300 ;
        RECT 1.000 197.300 74.000 197.700 ;
        RECT 1.300 181.700 73.700 197.300 ;
        RECT 1.000 181.300 74.000 181.700 ;
        RECT 1.300 165.700 73.700 181.300 ;
        RECT 1.000 165.300 74.000 165.700 ;
        RECT 1.300 149.700 73.700 165.300 ;
        RECT 1.000 149.300 74.000 149.700 ;
        RECT 1.300 133.700 73.700 149.300 ;
        RECT 1.000 133.300 74.000 133.700 ;
        RECT 1.300 125.700 73.700 133.300 ;
        RECT 1.000 125.300 74.000 125.700 ;
        RECT 1.300 117.700 73.700 125.300 ;
        RECT 1.000 117.300 74.000 117.700 ;
        RECT 1.300 101.700 73.700 117.300 ;
        RECT 1.000 101.300 74.000 101.700 ;
        RECT 1.300 85.700 73.700 101.300 ;
        RECT 1.000 85.300 74.000 85.700 ;
        RECT 1.300 69.700 73.700 85.300 ;
        RECT 1.000 0.000 74.000 69.700 ;
      LAYER Metal4 ;
        RECT 1.300 341.700 73.700 348.390 ;
        RECT 1.000 341.300 74.000 341.700 ;
        RECT 1.300 333.700 73.700 341.300 ;
        RECT 1.000 333.300 74.000 333.700 ;
        RECT 1.300 325.700 73.700 333.300 ;
        RECT 1.000 325.300 74.000 325.700 ;
        RECT 1.300 317.700 73.700 325.300 ;
        RECT 1.000 317.300 74.000 317.700 ;
        RECT 1.300 309.700 73.700 317.300 ;
        RECT 1.000 309.300 74.000 309.700 ;
        RECT 1.300 301.700 73.700 309.300 ;
        RECT 1.000 301.300 74.000 301.700 ;
        RECT 1.300 293.700 73.700 301.300 ;
        RECT 1.000 293.300 74.000 293.700 ;
        RECT 1.300 285.700 73.700 293.300 ;
        RECT 1.000 285.300 74.000 285.700 ;
        RECT 1.300 277.700 73.700 285.300 ;
        RECT 1.000 277.300 74.000 277.700 ;
        RECT 1.300 269.700 73.700 277.300 ;
        RECT 1.000 269.300 74.000 269.700 ;
        RECT 1.300 261.700 73.700 269.300 ;
        RECT 1.000 261.300 74.000 261.700 ;
        RECT 1.300 253.700 73.700 261.300 ;
        RECT 1.000 253.300 74.000 253.700 ;
        RECT 1.300 245.700 73.700 253.300 ;
        RECT 1.000 245.300 74.000 245.700 ;
        RECT 1.300 229.700 73.700 245.300 ;
        RECT 1.000 229.300 74.000 229.700 ;
        RECT 1.300 213.700 73.700 229.300 ;
        RECT 1.000 213.300 74.000 213.700 ;
        RECT 1.300 205.700 73.700 213.300 ;
        RECT 1.000 205.300 74.000 205.700 ;
        RECT 1.300 197.700 73.700 205.300 ;
        RECT 1.000 197.300 74.000 197.700 ;
        RECT 1.300 181.700 73.700 197.300 ;
        RECT 1.000 181.300 74.000 181.700 ;
        RECT 1.300 165.700 73.700 181.300 ;
        RECT 1.000 165.300 74.000 165.700 ;
        RECT 1.300 149.700 73.700 165.300 ;
        RECT 1.000 149.300 74.000 149.700 ;
        RECT 1.300 133.700 73.700 149.300 ;
        RECT 1.000 133.300 74.000 133.700 ;
        RECT 1.300 125.700 73.700 133.300 ;
        RECT 1.000 125.300 74.000 125.700 ;
        RECT 1.300 117.700 73.700 125.300 ;
        RECT 1.000 117.300 74.000 117.700 ;
        RECT 1.300 101.700 73.700 117.300 ;
        RECT 1.000 101.300 74.000 101.700 ;
        RECT 1.300 85.700 73.700 101.300 ;
        RECT 1.000 85.300 74.000 85.700 ;
        RECT 1.300 69.700 73.700 85.300 ;
        RECT 1.000 0.000 74.000 69.700 ;
      LAYER Metal5 ;
        RECT 1.500 69.500 73.500 348.390 ;
        RECT 1.000 45.500 74.000 69.500 ;
        RECT 1.000 19.500 24.500 45.500 ;
        RECT 50.500 19.500 74.000 45.500 ;
        RECT 1.000 0.000 74.000 19.500 ;
  END
END gf180mcu_fd_io__bi_24t

#--------EOF---------

#--------EOF---------

MACRO gf180mcu_fd_io__bi_t
  CLASS PAD INOUT ;
  FOREIGN gf180mcu_fd_io__bi_t ;
  ORIGIN 0.000 0.000 ;
  SIZE 75.000 BY 350.000 ;
  SYMMETRY X Y R90 ;
  PIN A
    DIRECTION INPUT ;
    USE SIGNAL ;
    PORT
      LAYER Metal2 ;
        RECT 69.400 264.460 69.780 350.000 ;
    END
  END A
  PIN CS
    DIRECTION INPUT ;
    USE SIGNAL ;
    PORT
      LAYER Metal2 ;
        RECT 3.360 328.545 3.740 350.000 ;
    END
  END CS
  PIN DVDD
    DIRECTION INOUT ;
    USE POWER ;
    PORT
      LAYER Metal5 ;
        RECT 74.000 118.000 75.000 125.000 ;
    END
    PORT
      LAYER Metal5 ;
        RECT 74.000 182.000 75.000 197.000 ;
    END
    PORT
      LAYER Metal5 ;
        RECT 74.000 166.000 75.000 181.000 ;
    END
    PORT
      LAYER Metal5 ;
        RECT 74.000 150.000 75.000 165.000 ;
    END
    PORT
      LAYER Metal5 ;
        RECT 74.000 134.000 75.000 149.000 ;
    END
    PORT
      LAYER Metal5 ;
        RECT 74.000 214.000 75.000 229.000 ;
    END
    PORT
      LAYER Metal5 ;
        RECT 74.000 206.000 75.000 213.000 ;
    END
    PORT
      LAYER Metal5 ;
        RECT 74.000 278.000 75.000 285.000 ;
    END
    PORT
      LAYER Metal5 ;
        RECT 74.000 270.000 75.000 277.000 ;
    END
    PORT
      LAYER Metal5 ;
        RECT 74.000 262.000 75.000 269.000 ;
    END
    PORT
      LAYER Metal5 ;
        RECT 74.000 294.000 75.000 301.000 ;
    END
    PORT
      LAYER Metal5 ;
        RECT 74.000 334.000 75.000 341.000 ;
    END
    PORT
      LAYER Metal4 ;
        RECT 74.000 118.000 75.000 125.000 ;
    END
    PORT
      LAYER Metal4 ;
        RECT 74.000 182.000 75.000 197.000 ;
    END
    PORT
      LAYER Metal4 ;
        RECT 74.000 166.000 75.000 181.000 ;
    END
    PORT
      LAYER Metal4 ;
        RECT 74.000 150.000 75.000 165.000 ;
    END
    PORT
      LAYER Metal4 ;
        RECT 74.000 134.000 75.000 149.000 ;
    END
    PORT
      LAYER Metal4 ;
        RECT 74.000 214.000 75.000 229.000 ;
    END
    PORT
      LAYER Metal4 ;
        RECT 74.000 206.000 75.000 213.000 ;
    END
    PORT
      LAYER Metal4 ;
        RECT 74.000 278.000 75.000 285.000 ;
    END
    PORT
      LAYER Metal4 ;
        RECT 74.000 270.000 75.000 277.000 ;
    END
    PORT
      LAYER Metal4 ;
        RECT 74.000 262.000 75.000 269.000 ;
    END
    PORT
      LAYER Metal4 ;
        RECT 74.000 294.000 75.000 301.000 ;
    END
    PORT
      LAYER Metal4 ;
        RECT 74.000 334.000 75.000 341.000 ;
    END
    PORT
      LAYER Metal3 ;
        RECT 74.000 118.000 75.000 125.000 ;
    END
    PORT
      LAYER Metal3 ;
        RECT 74.000 182.000 75.000 197.000 ;
    END
    PORT
      LAYER Metal3 ;
        RECT 74.000 166.000 75.000 181.000 ;
    END
    PORT
      LAYER Metal3 ;
        RECT 74.000 150.000 75.000 165.000 ;
    END
    PORT
      LAYER Metal3 ;
        RECT 74.000 134.000 75.000 149.000 ;
    END
    PORT
      LAYER Metal3 ;
        RECT 74.000 214.000 75.000 229.000 ;
    END
    PORT
      LAYER Metal3 ;
        RECT 74.000 206.000 75.000 213.000 ;
    END
    PORT
      LAYER Metal3 ;
        RECT 74.000 278.000 75.000 285.000 ;
    END
    PORT
      LAYER Metal3 ;
        RECT 74.000 270.000 75.000 277.000 ;
    END
    PORT
      LAYER Metal3 ;
        RECT 74.000 262.000 75.000 269.000 ;
    END
    PORT
      LAYER Metal3 ;
        RECT 74.000 294.000 75.000 301.000 ;
    END
    PORT
      LAYER Metal3 ;
        RECT 74.000 334.000 75.000 341.000 ;
    END
    PORT
      LAYER Metal3 ;
        RECT 0.000 334.000 1.000 341.000 ;
    END
    PORT
      LAYER Metal3 ;
        RECT 0.000 294.000 1.000 301.000 ;
    END
    PORT
      LAYER Metal3 ;
        RECT 0.000 262.000 1.000 269.000 ;
    END
    PORT
      LAYER Metal3 ;
        RECT 0.000 270.000 1.000 277.000 ;
    END
    PORT
      LAYER Metal3 ;
        RECT 0.000 278.000 1.000 285.000 ;
    END
    PORT
      LAYER Metal3 ;
        RECT 0.000 206.000 1.000 213.000 ;
    END
    PORT
      LAYER Metal3 ;
        RECT 0.000 214.000 1.000 229.000 ;
    END
    PORT
      LAYER Metal3 ;
        RECT 0.000 134.000 1.000 149.000 ;
    END
    PORT
      LAYER Metal3 ;
        RECT 0.000 150.000 1.000 165.000 ;
    END
    PORT
      LAYER Metal3 ;
        RECT 0.000 166.000 1.000 181.000 ;
    END
    PORT
      LAYER Metal3 ;
        RECT 0.000 182.000 1.000 197.000 ;
    END
    PORT
      LAYER Metal4 ;
        RECT 0.000 334.000 1.000 341.000 ;
    END
    PORT
      LAYER Metal4 ;
        RECT 0.000 294.000 1.000 301.000 ;
    END
    PORT
      LAYER Metal4 ;
        RECT 0.000 262.000 1.000 269.000 ;
    END
    PORT
      LAYER Metal4 ;
        RECT 0.000 270.000 1.000 277.000 ;
    END
    PORT
      LAYER Metal4 ;
        RECT 0.000 278.000 1.000 285.000 ;
    END
    PORT
      LAYER Metal4 ;
        RECT 0.000 206.000 1.000 213.000 ;
    END
    PORT
      LAYER Metal4 ;
        RECT 0.000 214.000 1.000 229.000 ;
    END
    PORT
      LAYER Metal4 ;
        RECT 0.000 134.000 1.000 149.000 ;
    END
    PORT
      LAYER Metal4 ;
        RECT 0.000 150.000 1.000 165.000 ;
    END
    PORT
      LAYER Metal4 ;
        RECT 0.000 166.000 1.000 181.000 ;
    END
    PORT
      LAYER Metal4 ;
        RECT 0.000 182.000 1.000 197.000 ;
    END
    PORT
      LAYER Metal5 ;
        RECT 0.000 334.000 1.000 341.000 ;
    END
    PORT
      LAYER Metal5 ;
        RECT 0.000 294.000 1.000 301.000 ;
    END
    PORT
      LAYER Metal5 ;
        RECT 0.000 262.000 1.000 269.000 ;
    END
    PORT
      LAYER Metal5 ;
        RECT 0.000 270.000 1.000 277.000 ;
    END
    PORT
      LAYER Metal5 ;
        RECT 0.000 278.000 1.000 285.000 ;
    END
    PORT
      LAYER Metal5 ;
        RECT 0.000 206.000 1.000 213.000 ;
    END
    PORT
      LAYER Metal5 ;
        RECT 0.000 214.000 1.000 229.000 ;
    END
    PORT
      LAYER Metal5 ;
        RECT 0.000 134.000 1.000 149.000 ;
    END
    PORT
      LAYER Metal5 ;
        RECT 0.000 150.000 1.000 165.000 ;
    END
    PORT
      LAYER Metal5 ;
        RECT 0.000 166.000 1.000 181.000 ;
    END
    PORT
      LAYER Metal5 ;
        RECT 0.000 182.000 1.000 197.000 ;
    END
    PORT
      LAYER Metal5 ;
        RECT 0.000 118.000 1.000 125.000 ;
    END
    PORT
      LAYER Metal4 ;
        RECT 0.000 118.000 1.000 125.000 ;
    END
    PORT
      LAYER Metal3 ;
        RECT 0.000 118.000 1.000 125.000 ;
    END
  END DVDD
  PIN DVSS
    DIRECTION INOUT ;
    USE GROUND ;
    PORT
      LAYER Metal5 ;
        RECT 74.000 102.000 75.000 117.000 ;
    END
    PORT
      LAYER Metal5 ;
        RECT 74.000 86.000 75.000 101.000 ;
    END
    PORT
      LAYER Metal5 ;
        RECT 74.000 70.000 75.000 85.000 ;
    END
    PORT
      LAYER Metal5 ;
        RECT 74.000 126.000 75.000 133.000 ;
    END
    PORT
      LAYER Metal5 ;
        RECT 74.000 198.000 75.000 205.000 ;
    END
    PORT
      LAYER Metal5 ;
        RECT 74.000 230.000 75.000 245.000 ;
    END
    PORT
      LAYER Metal5 ;
        RECT 74.000 286.000 75.000 293.000 ;
    END
    PORT
      LAYER Metal5 ;
        RECT 74.000 302.000 75.000 309.000 ;
    END
    PORT
      LAYER Metal5 ;
        RECT 74.000 326.000 75.000 333.000 ;
    END
    PORT
      LAYER Metal5 ;
        RECT 74.000 342.000 75.000 348.390 ;
    END
    PORT
      LAYER Metal4 ;
        RECT 74.000 102.000 75.000 117.000 ;
    END
    PORT
      LAYER Metal4 ;
        RECT 74.000 86.000 75.000 101.000 ;
    END
    PORT
      LAYER Metal4 ;
        RECT 74.000 70.000 75.000 85.000 ;
    END
    PORT
      LAYER Metal4 ;
        RECT 74.000 126.000 75.000 133.000 ;
    END
    PORT
      LAYER Metal4 ;
        RECT 74.000 198.000 75.000 205.000 ;
    END
    PORT
      LAYER Metal4 ;
        RECT 74.000 230.000 75.000 245.000 ;
    END
    PORT
      LAYER Metal4 ;
        RECT 74.000 286.000 75.000 293.000 ;
    END
    PORT
      LAYER Metal4 ;
        RECT 74.000 302.000 75.000 309.000 ;
    END
    PORT
      LAYER Metal4 ;
        RECT 74.000 326.000 75.000 333.000 ;
    END
    PORT
      LAYER Metal4 ;
        RECT 74.000 342.000 75.000 348.390 ;
    END
    PORT
      LAYER Metal3 ;
        RECT 74.000 102.000 75.000 117.000 ;
    END
    PORT
      LAYER Metal3 ;
        RECT 74.000 86.000 75.000 101.000 ;
    END
    PORT
      LAYER Metal3 ;
        RECT 74.000 70.000 75.000 85.000 ;
    END
    PORT
      LAYER Metal3 ;
        RECT 74.000 126.000 75.000 133.000 ;
    END
    PORT
      LAYER Metal3 ;
        RECT 74.000 198.000 75.000 205.000 ;
    END
    PORT
      LAYER Metal3 ;
        RECT 74.000 230.000 75.000 245.000 ;
    END
    PORT
      LAYER Metal3 ;
        RECT 74.000 286.000 75.000 293.000 ;
    END
    PORT
      LAYER Metal3 ;
        RECT 74.000 302.000 75.000 309.000 ;
    END
    PORT
      LAYER Metal3 ;
        RECT 74.000 326.000 75.000 333.000 ;
    END
    PORT
      LAYER Metal3 ;
        RECT 74.000 342.000 75.000 348.390 ;
    END
    PORT
      LAYER Metal3 ;
        RECT 0.000 342.000 1.000 348.390 ;
    END
    PORT
      LAYER Metal3 ;
        RECT 0.000 326.000 1.000 333.000 ;
    END
    PORT
      LAYER Metal3 ;
        RECT 0.000 302.000 1.000 309.000 ;
    END
    PORT
      LAYER Metal3 ;
        RECT 0.000 286.000 1.000 293.000 ;
    END
    PORT
      LAYER Metal3 ;
        RECT 0.000 230.000 1.000 245.000 ;
    END
    PORT
      LAYER Metal3 ;
        RECT 0.000 198.000 1.000 205.000 ;
    END
    PORT
      LAYER Metal3 ;
        RECT 0.000 126.000 1.000 133.000 ;
    END
    PORT
      LAYER Metal3 ;
        RECT 0.000 70.000 1.000 85.000 ;
    END
    PORT
      LAYER Metal3 ;
        RECT 0.000 86.000 1.000 101.000 ;
    END
    PORT
      LAYER Metal4 ;
        RECT 0.000 342.000 1.000 348.390 ;
    END
    PORT
      LAYER Metal4 ;
        RECT 0.000 326.000 1.000 333.000 ;
    END
    PORT
      LAYER Metal4 ;
        RECT 0.000 302.000 1.000 309.000 ;
    END
    PORT
      LAYER Metal4 ;
        RECT 0.000 286.000 1.000 293.000 ;
    END
    PORT
      LAYER Metal4 ;
        RECT 0.000 230.000 1.000 245.000 ;
    END
    PORT
      LAYER Metal4 ;
        RECT 0.000 198.000 1.000 205.000 ;
    END
    PORT
      LAYER Metal4 ;
        RECT 0.000 126.000 1.000 133.000 ;
    END
    PORT
      LAYER Metal4 ;
        RECT 0.000 70.000 1.000 85.000 ;
    END
    PORT
      LAYER Metal4 ;
        RECT 0.000 86.000 1.000 101.000 ;
    END
    PORT
      LAYER Metal5 ;
        RECT 0.000 342.000 1.000 348.390 ;
    END
    PORT
      LAYER Metal5 ;
        RECT 0.000 326.000 1.000 333.000 ;
    END
    PORT
      LAYER Metal5 ;
        RECT 0.000 302.000 1.000 309.000 ;
    END
    PORT
      LAYER Metal5 ;
        RECT 0.000 286.000 1.000 293.000 ;
    END
    PORT
      LAYER Metal5 ;
        RECT 0.000 230.000 1.000 245.000 ;
    END
    PORT
      LAYER Metal5 ;
        RECT 0.000 198.000 1.000 205.000 ;
    END
    PORT
      LAYER Metal5 ;
        RECT 0.000 126.000 1.000 133.000 ;
    END
    PORT
      LAYER Metal5 ;
        RECT 0.000 70.000 1.000 85.000 ;
    END
    PORT
      LAYER Metal5 ;
        RECT 0.000 86.000 1.000 101.000 ;
    END
    PORT
      LAYER Metal5 ;
        RECT 0.000 102.000 1.000 117.000 ;
    END
    PORT
      LAYER Metal4 ;
        RECT 0.000 102.000 1.000 117.000 ;
    END
    PORT
      LAYER Metal3 ;
        RECT 0.000 102.000 1.000 117.000 ;
    END
  END DVSS
  PIN IE
    DIRECTION INPUT ;
    USE SIGNAL ;
    PORT
      LAYER Metal2 ;
        RECT 11.385 334.920 11.765 350.000 ;
    END
  END IE
  PIN OE
    DIRECTION INPUT ;
    USE SIGNAL ;
    PORT
      LAYER Metal2 ;
        RECT 70.130 266.340 70.510 350.000 ;
    END
  END OE
  PIN PAD
    DIRECTION INOUT ;
    USE SIGNAL ;
    PORT
      LAYER Metal5 ;
        RECT 25.000 20.000 50.000 45.000 ;
    END
  END PAD
  PIN PD
    DIRECTION INPUT ;
    USE SIGNAL ;
    PORT
      LAYER Metal2 ;
        RECT 10.330 330.100 10.710 350.000 ;
    END
  END PD
  PIN PDRV0
    DIRECTION INPUT ;
    USE SIGNAL ;
    PORT
      LAYER Metal2 ;
        RECT 7.110 264.665 7.490 350.000 ;
    END
  END PDRV0
  PIN PDRV1
    DIRECTION INPUT ;
    USE SIGNAL ;
    PORT
      LAYER Metal2 ;
        RECT 7.820 264.990 8.200 350.000 ;
    END
  END PDRV1
  PIN PU
    DIRECTION INPUT ;
    USE SIGNAL ;
    PORT
      LAYER Metal2 ;
        RECT 5.965 330.420 6.345 350.000 ;
    END
  END PU
  PIN SL
    DIRECTION INPUT ;
    USE SIGNAL ;
    PORT
      LAYER Metal2 ;
        RECT 68.670 265.140 69.050 350.000 ;
    END
  END SL
  PIN VDD
    DIRECTION INOUT ;
    USE POWER ;
    PORT
      LAYER Metal5 ;
        RECT 74.000 254.000 75.000 261.000 ;
    END
    PORT
      LAYER Metal5 ;
        RECT 74.000 310.000 75.000 317.000 ;
    END
    PORT
      LAYER Metal4 ;
        RECT 74.000 254.000 75.000 261.000 ;
    END
    PORT
      LAYER Metal4 ;
        RECT 74.000 310.000 75.000 317.000 ;
    END
    PORT
      LAYER Metal3 ;
        RECT 74.000 254.000 75.000 261.000 ;
    END
    PORT
      LAYER Metal3 ;
        RECT 74.000 310.000 75.000 317.000 ;
    END
    PORT
      LAYER Metal3 ;
        RECT 0.000 310.000 1.000 317.000 ;
    END
    PORT
      LAYER Metal4 ;
        RECT 0.000 310.000 1.000 317.000 ;
    END
    PORT
      LAYER Metal5 ;
        RECT 0.000 310.000 1.000 317.000 ;
    END
    PORT
      LAYER Metal5 ;
        RECT 0.000 254.000 1.000 261.000 ;
    END
    PORT
      LAYER Metal4 ;
        RECT 0.000 254.000 1.000 261.000 ;
    END
    PORT
      LAYER Metal3 ;
        RECT 0.000 254.000 1.000 261.000 ;
    END
  END VDD
  PIN VSS
    DIRECTION INOUT ;
    USE GROUND ;
    PORT
      LAYER Metal5 ;
        RECT 74.000 246.000 75.000 253.000 ;
    END
    PORT
      LAYER Metal5 ;
        RECT 74.000 318.000 75.000 325.000 ;
    END
    PORT
      LAYER Metal4 ;
        RECT 74.000 246.000 75.000 253.000 ;
    END
    PORT
      LAYER Metal4 ;
        RECT 74.000 318.000 75.000 325.000 ;
    END
    PORT
      LAYER Metal3 ;
        RECT 74.000 246.000 75.000 253.000 ;
    END
    PORT
      LAYER Metal3 ;
        RECT 74.000 318.000 75.000 325.000 ;
    END
    PORT
      LAYER Metal3 ;
        RECT 0.000 318.000 1.000 325.000 ;
    END
    PORT
      LAYER Metal4 ;
        RECT 0.000 318.000 1.000 325.000 ;
    END
    PORT
      LAYER Metal5 ;
        RECT 0.000 318.000 1.000 325.000 ;
    END
    PORT
      LAYER Metal5 ;
        RECT 0.000 246.000 1.000 253.000 ;
    END
    PORT
      LAYER Metal4 ;
        RECT 0.000 246.000 1.000 253.000 ;
    END
    PORT
      LAYER Metal3 ;
        RECT 0.000 246.000 1.000 253.000 ;
    END
  END VSS
  PIN Y
    DIRECTION OUTPUT ;
    USE SIGNAL ;
    PORT
      LAYER Metal2 ;
        RECT 70.860 319.900 71.240 350.000 ;
    END
  END Y
  OBS
      LAYER Metal1 ;
        RECT -0.160 65.540 75.160 349.785 ;
      LAYER Metal2 ;
        RECT 0.000 328.245 3.060 348.375 ;
        RECT 4.040 330.120 5.665 348.375 ;
        RECT 6.645 330.120 6.810 348.375 ;
        RECT 4.040 328.245 6.810 330.120 ;
        RECT 0.000 264.365 6.810 328.245 ;
        RECT 8.500 329.800 10.030 348.375 ;
        RECT 11.010 334.620 11.085 348.375 ;
        RECT 12.065 334.620 68.370 348.375 ;
        RECT 11.010 329.800 68.370 334.620 ;
        RECT 8.500 264.840 68.370 329.800 ;
        RECT 71.540 319.600 75.000 348.375 ;
        RECT 70.810 266.040 75.000 319.600 ;
        RECT 8.500 264.690 69.100 264.840 ;
        RECT 7.790 264.365 69.100 264.690 ;
        RECT 0.000 264.160 69.100 264.365 ;
        RECT 70.080 264.160 75.000 266.040 ;
        RECT 0.000 0.000 75.000 264.160 ;
      LAYER Metal3 ;
        RECT 1.300 341.700 73.700 348.390 ;
        RECT 0.665 341.300 74.000 341.700 ;
        RECT 1.300 333.700 73.700 341.300 ;
        RECT 0.665 333.300 74.000 333.700 ;
        RECT 1.300 325.700 73.700 333.300 ;
        RECT 0.665 325.300 74.000 325.700 ;
        RECT 1.300 317.700 73.700 325.300 ;
        RECT 0.665 317.300 74.000 317.700 ;
        RECT 1.300 309.700 73.700 317.300 ;
        RECT 0.665 309.300 74.000 309.700 ;
        RECT 1.300 301.700 73.700 309.300 ;
        RECT 0.665 301.300 74.000 301.700 ;
        RECT 1.300 293.700 73.700 301.300 ;
        RECT 0.665 293.300 74.000 293.700 ;
        RECT 1.300 285.700 73.700 293.300 ;
        RECT 0.665 285.300 74.000 285.700 ;
        RECT 1.300 277.700 73.700 285.300 ;
        RECT 0.665 277.300 74.000 277.700 ;
        RECT 1.300 269.700 73.700 277.300 ;
        RECT 0.665 269.300 74.000 269.700 ;
        RECT 1.300 261.700 73.700 269.300 ;
        RECT 0.665 261.300 74.000 261.700 ;
        RECT 1.300 253.700 73.700 261.300 ;
        RECT 0.665 253.300 74.000 253.700 ;
        RECT 1.300 245.700 73.700 253.300 ;
        RECT 0.665 245.300 74.000 245.700 ;
        RECT 1.300 229.700 73.700 245.300 ;
        RECT 0.665 229.300 74.000 229.700 ;
        RECT 1.300 213.700 73.700 229.300 ;
        RECT 0.665 213.300 74.000 213.700 ;
        RECT 1.300 205.700 73.700 213.300 ;
        RECT 0.665 205.300 74.000 205.700 ;
        RECT 1.300 197.700 73.700 205.300 ;
        RECT 0.665 197.300 74.000 197.700 ;
        RECT 1.300 181.700 73.700 197.300 ;
        RECT 0.665 181.300 74.000 181.700 ;
        RECT 1.300 165.700 73.700 181.300 ;
        RECT 0.665 165.300 74.000 165.700 ;
        RECT 1.300 149.700 73.700 165.300 ;
        RECT 0.665 149.300 74.000 149.700 ;
        RECT 1.300 133.700 73.700 149.300 ;
        RECT 0.665 133.300 74.000 133.700 ;
        RECT 1.300 125.700 73.700 133.300 ;
        RECT 0.665 125.300 74.000 125.700 ;
        RECT 1.300 117.700 73.700 125.300 ;
        RECT 0.665 117.300 74.000 117.700 ;
        RECT 1.300 101.700 73.700 117.300 ;
        RECT 0.665 101.300 74.000 101.700 ;
        RECT 1.300 85.700 73.700 101.300 ;
        RECT 0.665 85.300 74.000 85.700 ;
        RECT 1.300 69.700 73.700 85.300 ;
        RECT 0.665 0.000 74.000 69.700 ;
      LAYER Metal4 ;
        RECT 1.300 341.700 73.700 348.390 ;
        RECT 1.000 341.300 74.000 341.700 ;
        RECT 1.300 333.700 73.700 341.300 ;
        RECT 1.000 333.300 74.000 333.700 ;
        RECT 1.300 325.700 73.700 333.300 ;
        RECT 1.000 325.300 74.000 325.700 ;
        RECT 1.300 317.700 73.700 325.300 ;
        RECT 1.000 317.300 74.000 317.700 ;
        RECT 1.300 309.700 73.700 317.300 ;
        RECT 1.000 309.300 74.000 309.700 ;
        RECT 1.300 301.700 73.700 309.300 ;
        RECT 1.000 301.300 74.000 301.700 ;
        RECT 1.300 293.700 73.700 301.300 ;
        RECT 1.000 293.300 74.000 293.700 ;
        RECT 1.300 285.700 73.700 293.300 ;
        RECT 1.000 285.300 74.000 285.700 ;
        RECT 1.300 277.700 73.700 285.300 ;
        RECT 1.000 277.300 74.000 277.700 ;
        RECT 1.300 269.700 73.700 277.300 ;
        RECT 1.000 269.300 74.000 269.700 ;
        RECT 1.300 261.700 73.700 269.300 ;
        RECT 1.000 261.300 74.000 261.700 ;
        RECT 1.300 253.700 73.700 261.300 ;
        RECT 1.000 253.300 74.000 253.700 ;
        RECT 1.300 245.700 73.700 253.300 ;
        RECT 1.000 245.300 74.000 245.700 ;
        RECT 1.300 229.700 73.700 245.300 ;
        RECT 1.000 229.300 74.000 229.700 ;
        RECT 1.300 213.700 73.700 229.300 ;
        RECT 1.000 213.300 74.000 213.700 ;
        RECT 1.300 205.700 73.700 213.300 ;
        RECT 1.000 205.300 74.000 205.700 ;
        RECT 1.300 197.700 73.700 205.300 ;
        RECT 1.000 197.300 74.000 197.700 ;
        RECT 1.300 181.700 73.700 197.300 ;
        RECT 1.000 181.300 74.000 181.700 ;
        RECT 1.300 165.700 73.700 181.300 ;
        RECT 1.000 165.300 74.000 165.700 ;
        RECT 1.300 149.700 73.700 165.300 ;
        RECT 1.000 149.300 74.000 149.700 ;
        RECT 1.300 133.700 73.700 149.300 ;
        RECT 1.000 133.300 74.000 133.700 ;
        RECT 1.300 125.700 73.700 133.300 ;
        RECT 1.000 125.300 74.000 125.700 ;
        RECT 1.300 117.700 73.700 125.300 ;
        RECT 1.000 117.300 74.000 117.700 ;
        RECT 1.300 101.700 73.700 117.300 ;
        RECT 1.000 101.300 74.000 101.700 ;
        RECT 1.300 85.700 73.700 101.300 ;
        RECT 1.000 85.300 74.000 85.700 ;
        RECT 1.300 69.700 73.700 85.300 ;
        RECT 1.000 0.000 74.000 69.700 ;
      LAYER Metal5 ;
        RECT 1.500 69.500 73.500 348.390 ;
        RECT 1.000 45.500 74.000 69.500 ;
        RECT 1.000 19.500 24.500 45.500 ;
        RECT 50.500 19.500 74.000 45.500 ;
        RECT 1.000 0.000 74.000 19.500 ;
  END
END gf180mcu_fd_io__bi_t

#--------EOF---------

#--------EOF---------

MACRO gf180mcu_fd_io__brk2
  CLASS PAD ;
  FOREIGN gf180mcu_fd_io__brk2 ;
  ORIGIN 0.000 0.000 ;
  SIZE 2.000 BY 350.000 ;
  SYMMETRY X Y R90 ;
  PIN VSS
    DIRECTION INOUT ;
    USE GROUND ;
    PORT
      LAYER Metal3 ;
        RECT 0.000 318.000 2.000 325.000 ;
    END
    PORT
      LAYER Metal4 ;
        RECT 0.000 318.000 2.000 325.000 ;
    END
    PORT
      LAYER Metal5 ;
        RECT 0.000 318.000 2.000 325.000 ;
    END
    PORT
      LAYER Metal5 ;
        RECT 0.000 246.000 2.000 253.000 ;
    END
    PORT
      LAYER Metal4 ;
        RECT 0.000 246.000 2.000 253.000 ;
    END
    PORT
      LAYER Metal3 ;
        RECT 0.000 246.000 2.000 253.000 ;
    END
  END VSS
  OBS
      LAYER Metal1 ;
        RECT -0.160 65.540 2.160 349.785 ;
      LAYER Metal2 ;
        RECT 0.000 66.375 2.000 348.845 ;
  END
END gf180mcu_fd_io__brk2

#--------EOF---------

#--------EOF---------

MACRO gf180mcu_fd_io__brk5
  CLASS PAD ;
  FOREIGN gf180mcu_fd_io__brk5 ;
  ORIGIN 0.000 0.000 ;
  SIZE 5.000 BY 350.000 ;
  SYMMETRY X Y R90 ;
  PIN VSS
    DIRECTION INOUT ;
    USE GROUND ;
    PORT
      LAYER Metal5 ;
        RECT 4.000 246.000 5.000 253.000 ;
    END
    PORT
      LAYER Metal5 ;
        RECT 4.000 318.000 5.000 325.000 ;
    END
    PORT
      LAYER Metal4 ;
        RECT 4.000 246.000 5.000 253.000 ;
    END
    PORT
      LAYER Metal4 ;
        RECT 4.000 318.000 5.000 325.000 ;
    END
    PORT
      LAYER Metal3 ;
        RECT 4.000 246.000 5.000 253.000 ;
    END
    PORT
      LAYER Metal3 ;
        RECT 4.000 318.000 5.000 325.000 ;
    END
    PORT
      LAYER Metal3 ;
        RECT 0.000 318.000 1.000 325.000 ;
    END
    PORT
      LAYER Metal4 ;
        RECT 0.000 318.000 1.000 325.000 ;
    END
    PORT
      LAYER Metal5 ;
        RECT 0.000 318.000 1.000 325.000 ;
    END
    PORT
      LAYER Metal5 ;
        RECT 0.000 246.000 1.000 253.000 ;
    END
    PORT
      LAYER Metal4 ;
        RECT 0.000 246.000 1.000 253.000 ;
    END
    PORT
      LAYER Metal3 ;
        RECT 0.000 246.000 1.000 253.000 ;
    END
  END VSS
  OBS
      LAYER Metal1 ;
        RECT -0.160 65.540 5.160 349.785 ;
      LAYER Metal2 ;
        RECT 0.000 68.110 5.000 348.080 ;
      LAYER Metal3 ;
        RECT 1.300 317.700 3.700 325.000 ;
        RECT 1.000 253.300 4.000 317.700 ;
        RECT 1.300 246.000 3.700 253.300 ;
      LAYER Metal4 ;
        RECT 1.300 317.700 3.700 325.000 ;
        RECT 1.000 253.300 4.000 317.700 ;
        RECT 1.300 246.000 3.700 253.300 ;
      LAYER Metal5 ;
        RECT 1.500 317.500 3.500 325.000 ;
        RECT 1.000 253.500 4.000 317.500 ;
        RECT 1.500 246.000 3.500 253.500 ;
  END
END gf180mcu_fd_io__brk5

#--------EOF---------

#--------EOF---------

MACRO gf180mcu_fd_io__cor
  CLASS ENDCAP BOTTOMLEFT ;
  FOREIGN gf180mcu_fd_io__cor ;
  ORIGIN 0.000 0.000 ;
  SIZE 355.000 BY 355.000 ;
  SYMMETRY X Y R90 ;
  PIN DVDD
    DIRECTION INOUT ;
    USE POWER ;
    PORT
      LAYER Metal3 ;
        RECT 334.000 354.000 341.000 355.000 ;
    END
    PORT
      LAYER Metal3 ;
        RECT 354.000 334.000 355.000 341.000 ;
    END
    PORT
      LAYER Metal3 ;
        RECT 294.000 354.000 301.000 355.000 ;
    END
    PORT
      LAYER Metal3 ;
        RECT 354.000 294.000 355.000 301.000 ;
    END
    PORT
      LAYER Metal3 ;
        RECT 278.000 354.000 285.000 355.000 ;
    END
    PORT
      LAYER Metal3 ;
        RECT 354.000 278.000 355.000 285.000 ;
    END
    PORT
      LAYER Metal3 ;
        RECT 270.000 354.000 277.000 355.000 ;
    END
    PORT
      LAYER Metal3 ;
        RECT 354.000 270.000 355.000 277.000 ;
    END
    PORT
      LAYER Metal3 ;
        RECT 262.000 354.000 269.000 355.000 ;
    END
    PORT
      LAYER Metal3 ;
        RECT 354.000 262.000 355.000 269.000 ;
    END
    PORT
      LAYER Metal3 ;
        RECT 214.000 354.000 229.000 355.000 ;
    END
    PORT
      LAYER Metal3 ;
        RECT 354.000 214.000 355.000 229.000 ;
    END
    PORT
      LAYER Metal3 ;
        RECT 206.000 354.000 213.000 355.000 ;
    END
    PORT
      LAYER Metal3 ;
        RECT 354.000 206.000 355.000 213.000 ;
    END
    PORT
      LAYER Metal3 ;
        RECT 182.000 354.000 197.000 355.000 ;
    END
    PORT
      LAYER Metal3 ;
        RECT 354.000 182.000 355.000 197.000 ;
    END
    PORT
      LAYER Metal3 ;
        RECT 166.000 354.000 181.000 355.000 ;
    END
    PORT
      LAYER Metal3 ;
        RECT 354.000 166.000 355.000 181.000 ;
    END
    PORT
      LAYER Metal3 ;
        RECT 150.000 354.000 165.000 355.000 ;
    END
    PORT
      LAYER Metal3 ;
        RECT 354.000 150.000 355.000 165.000 ;
    END
    PORT
      LAYER Metal3 ;
        RECT 134.000 354.000 149.000 355.000 ;
    END
    PORT
      LAYER Metal3 ;
        RECT 354.000 134.000 355.000 149.000 ;
    END
    PORT
      LAYER Metal3 ;
        RECT 118.000 354.000 125.000 355.000 ;
    END
    PORT
      LAYER Metal4 ;
        RECT 334.000 354.000 341.000 355.000 ;
    END
    PORT
      LAYER Metal4 ;
        RECT 354.000 334.000 355.000 341.000 ;
    END
    PORT
      LAYER Metal4 ;
        RECT 294.000 354.000 301.000 355.000 ;
    END
    PORT
      LAYER Metal4 ;
        RECT 354.000 294.000 355.000 301.000 ;
    END
    PORT
      LAYER Metal4 ;
        RECT 278.000 354.000 285.000 355.000 ;
    END
    PORT
      LAYER Metal4 ;
        RECT 354.000 278.000 355.000 285.000 ;
    END
    PORT
      LAYER Metal4 ;
        RECT 270.000 354.000 277.000 355.000 ;
    END
    PORT
      LAYER Metal4 ;
        RECT 354.000 270.000 355.000 277.000 ;
    END
    PORT
      LAYER Metal4 ;
        RECT 262.000 354.000 269.000 355.000 ;
    END
    PORT
      LAYER Metal4 ;
        RECT 354.000 262.000 355.000 269.000 ;
    END
    PORT
      LAYER Metal4 ;
        RECT 214.000 354.000 229.000 355.000 ;
    END
    PORT
      LAYER Metal4 ;
        RECT 354.000 214.000 355.000 229.000 ;
    END
    PORT
      LAYER Metal4 ;
        RECT 206.000 354.000 213.000 355.000 ;
    END
    PORT
      LAYER Metal4 ;
        RECT 354.000 206.000 355.000 213.000 ;
    END
    PORT
      LAYER Metal4 ;
        RECT 182.000 354.000 197.000 355.000 ;
    END
    PORT
      LAYER Metal4 ;
        RECT 354.000 182.000 355.000 197.000 ;
    END
    PORT
      LAYER Metal4 ;
        RECT 166.000 354.000 181.000 355.000 ;
    END
    PORT
      LAYER Metal4 ;
        RECT 354.000 166.000 355.000 181.000 ;
    END
    PORT
      LAYER Metal4 ;
        RECT 150.000 354.000 165.000 355.000 ;
    END
    PORT
      LAYER Metal4 ;
        RECT 354.000 150.000 355.000 165.000 ;
    END
    PORT
      LAYER Metal4 ;
        RECT 134.000 354.000 149.000 355.000 ;
    END
    PORT
      LAYER Metal4 ;
        RECT 354.000 134.000 355.000 149.000 ;
    END
    PORT
      LAYER Metal4 ;
        RECT 118.000 354.000 125.000 355.000 ;
    END
    PORT
      LAYER Metal5 ;
        RECT 334.000 354.000 341.000 355.000 ;
    END
    PORT
      LAYER Metal5 ;
        RECT 354.000 334.000 355.000 341.000 ;
    END
    PORT
      LAYER Metal5 ;
        RECT 294.000 354.000 301.000 355.000 ;
    END
    PORT
      LAYER Metal5 ;
        RECT 354.000 294.000 355.000 301.000 ;
    END
    PORT
      LAYER Metal5 ;
        RECT 278.000 354.000 285.000 355.000 ;
    END
    PORT
      LAYER Metal5 ;
        RECT 354.000 278.000 355.000 285.000 ;
    END
    PORT
      LAYER Metal5 ;
        RECT 270.000 354.000 277.000 355.000 ;
    END
    PORT
      LAYER Metal5 ;
        RECT 354.000 270.000 355.000 277.000 ;
    END
    PORT
      LAYER Metal5 ;
        RECT 262.000 354.000 269.000 355.000 ;
    END
    PORT
      LAYER Metal5 ;
        RECT 354.000 262.000 355.000 269.000 ;
    END
    PORT
      LAYER Metal5 ;
        RECT 214.000 354.000 229.000 355.000 ;
    END
    PORT
      LAYER Metal5 ;
        RECT 354.000 214.000 355.000 229.000 ;
    END
    PORT
      LAYER Metal5 ;
        RECT 206.000 354.000 213.000 355.000 ;
    END
    PORT
      LAYER Metal5 ;
        RECT 354.000 206.000 355.000 213.000 ;
    END
    PORT
      LAYER Metal5 ;
        RECT 182.000 354.000 197.000 355.000 ;
    END
    PORT
      LAYER Metal5 ;
        RECT 354.000 182.000 355.000 197.000 ;
    END
    PORT
      LAYER Metal5 ;
        RECT 166.000 354.000 181.000 355.000 ;
    END
    PORT
      LAYER Metal5 ;
        RECT 354.000 166.000 355.000 181.000 ;
    END
    PORT
      LAYER Metal5 ;
        RECT 150.000 354.000 165.000 355.000 ;
    END
    PORT
      LAYER Metal5 ;
        RECT 354.000 150.000 355.000 165.000 ;
    END
    PORT
      LAYER Metal5 ;
        RECT 134.000 354.000 149.000 355.000 ;
    END
    PORT
      LAYER Metal5 ;
        RECT 354.000 134.000 355.000 149.000 ;
    END
    PORT
      LAYER Metal5 ;
        RECT 118.000 354.000 125.000 355.000 ;
    END
    PORT
      LAYER Metal5 ;
        RECT 354.000 118.000 355.000 125.000 ;
    END
    PORT
      LAYER Metal4 ;
        RECT 354.000 118.000 355.000 125.000 ;
    END
    PORT
      LAYER Metal3 ;
        RECT 354.000 118.000 355.000 125.000 ;
    END
    PORT
      LAYER Metal5 ;
        RECT 337.310 343.345 337.690 354.000 ;
    END
    PORT
      LAYER Metal5 ;
        RECT 352.060 214.000 352.440 229.000 ;
    END
    PORT
      LAYER Metal5 ;
        RECT 352.215 265.875 352.225 265.885 ;
    END
    PORT
      LAYER Metal5 ;
        RECT 351.910 270.000 352.290 277.000 ;
    END
    PORT
      LAYER Metal5 ;
        RECT 351.920 278.000 352.300 285.000 ;
    END
    PORT
      LAYER Metal5 ;
        RECT 351.945 294.000 352.325 301.000 ;
    END
    PORT
      LAYER Metal5 ;
        RECT 352.010 334.000 352.390 341.000 ;
    END
    PORT
      LAYER Metal5 ;
        RECT 214.000 350.740 229.000 351.120 ;
    END
    PORT
      LAYER Metal5 ;
        RECT 265.310 313.415 265.690 354.000 ;
    END
    PORT
      LAYER Metal5 ;
        RECT 273.310 316.745 273.690 354.000 ;
    END
    PORT
      LAYER Metal5 ;
        RECT 281.310 320.060 281.690 354.000 ;
    END
    PORT
      LAYER Metal5 ;
        RECT 297.310 326.710 297.690 354.000 ;
    END
    PORT
      LAYER Metal5 ;
        RECT 209.310 289.930 209.690 354.000 ;
    END
    PORT
      LAYER Metal5 ;
        RECT 188.320 283.200 188.700 354.000 ;
    END
    PORT
      LAYER Metal5 ;
        RECT 118.000 350.800 125.000 351.180 ;
    END
    PORT
      LAYER Metal5 ;
        RECT 140.320 263.145 140.700 354.000 ;
    END
    PORT
      LAYER Metal5 ;
        RECT 156.320 269.835 156.700 354.000 ;
    END
    PORT
      LAYER Metal5 ;
        RECT 172.240 351.095 172.250 351.105 ;
    END
    PORT
      LAYER Metal5 ;
        RECT 351.970 182.000 352.350 197.000 ;
    END
    PORT
      LAYER Metal5 ;
        RECT 352.035 206.000 352.415 213.000 ;
    END
    PORT
      LAYER Metal5 ;
        RECT 293.405 157.640 354.000 158.020 ;
    END
    PORT
      LAYER Metal5 ;
        RECT 351.920 166.000 352.300 181.000 ;
    END
    PORT
      LAYER Metal5 ;
        RECT 352.120 118.000 352.500 125.000 ;
    END
    PORT
      LAYER Metal5 ;
        RECT 293.405 141.640 354.000 142.020 ;
    END
  END DVDD
  PIN DVSS
    DIRECTION INOUT ;
    USE GROUND ;
    PORT
      LAYER Metal3 ;
        RECT 342.000 354.000 348.390 355.000 ;
    END
    PORT
      LAYER Metal3 ;
        RECT 354.000 342.000 355.000 348.390 ;
    END
    PORT
      LAYER Metal3 ;
        RECT 326.000 354.000 333.000 355.000 ;
    END
    PORT
      LAYER Metal3 ;
        RECT 354.000 326.000 355.000 333.000 ;
    END
    PORT
      LAYER Metal3 ;
        RECT 302.000 354.000 309.000 355.000 ;
    END
    PORT
      LAYER Metal3 ;
        RECT 354.000 302.000 355.000 309.000 ;
    END
    PORT
      LAYER Metal3 ;
        RECT 286.000 354.000 293.000 355.000 ;
    END
    PORT
      LAYER Metal3 ;
        RECT 354.000 286.000 355.000 293.000 ;
    END
    PORT
      LAYER Metal3 ;
        RECT 230.000 354.000 245.000 355.000 ;
    END
    PORT
      LAYER Metal3 ;
        RECT 354.000 230.000 355.000 245.000 ;
    END
    PORT
      LAYER Metal3 ;
        RECT 198.000 354.000 205.000 355.000 ;
    END
    PORT
      LAYER Metal3 ;
        RECT 354.000 198.000 355.000 205.000 ;
    END
    PORT
      LAYER Metal3 ;
        RECT 126.000 354.000 133.000 355.000 ;
    END
    PORT
      LAYER Metal3 ;
        RECT 354.000 126.000 355.000 133.000 ;
    END
    PORT
      LAYER Metal3 ;
        RECT 102.000 354.000 117.000 355.000 ;
    END
    PORT
      LAYER Metal3 ;
        RECT 354.000 102.000 355.000 117.000 ;
    END
    PORT
      LAYER Metal3 ;
        RECT 86.000 354.000 101.000 355.000 ;
    END
    PORT
      LAYER Metal3 ;
        RECT 354.000 86.000 355.000 101.000 ;
    END
    PORT
      LAYER Metal3 ;
        RECT 70.000 354.000 85.000 355.000 ;
    END
    PORT
      LAYER Metal4 ;
        RECT 342.000 354.000 348.390 355.000 ;
    END
    PORT
      LAYER Metal4 ;
        RECT 354.000 342.000 355.000 348.390 ;
    END
    PORT
      LAYER Metal4 ;
        RECT 326.000 354.000 333.000 355.000 ;
    END
    PORT
      LAYER Metal4 ;
        RECT 354.000 326.000 355.000 333.000 ;
    END
    PORT
      LAYER Metal4 ;
        RECT 302.000 354.000 309.000 355.000 ;
    END
    PORT
      LAYER Metal4 ;
        RECT 354.000 302.000 355.000 309.000 ;
    END
    PORT
      LAYER Metal4 ;
        RECT 286.000 354.000 293.000 355.000 ;
    END
    PORT
      LAYER Metal4 ;
        RECT 354.000 286.000 355.000 293.000 ;
    END
    PORT
      LAYER Metal4 ;
        RECT 230.000 354.000 245.000 355.000 ;
    END
    PORT
      LAYER Metal4 ;
        RECT 354.000 230.000 355.000 245.000 ;
    END
    PORT
      LAYER Metal4 ;
        RECT 198.000 354.000 205.000 355.000 ;
    END
    PORT
      LAYER Metal4 ;
        RECT 354.000 198.000 355.000 205.000 ;
    END
    PORT
      LAYER Metal4 ;
        RECT 126.000 354.000 133.000 355.000 ;
    END
    PORT
      LAYER Metal4 ;
        RECT 354.000 126.000 355.000 133.000 ;
    END
    PORT
      LAYER Metal4 ;
        RECT 102.000 354.000 117.000 355.000 ;
    END
    PORT
      LAYER Metal4 ;
        RECT 354.000 102.000 355.000 117.000 ;
    END
    PORT
      LAYER Metal4 ;
        RECT 86.000 354.000 101.000 355.000 ;
    END
    PORT
      LAYER Metal4 ;
        RECT 354.000 86.000 355.000 101.000 ;
    END
    PORT
      LAYER Metal4 ;
        RECT 70.000 354.000 85.000 355.000 ;
    END
    PORT
      LAYER Metal5 ;
        RECT 342.000 354.000 348.390 355.000 ;
    END
    PORT
      LAYER Metal5 ;
        RECT 354.000 342.000 355.000 348.390 ;
    END
    PORT
      LAYER Metal5 ;
        RECT 326.000 354.000 333.000 355.000 ;
    END
    PORT
      LAYER Metal5 ;
        RECT 354.000 326.000 355.000 333.000 ;
    END
    PORT
      LAYER Metal5 ;
        RECT 302.000 354.000 309.000 355.000 ;
    END
    PORT
      LAYER Metal5 ;
        RECT 354.000 302.000 355.000 309.000 ;
    END
    PORT
      LAYER Metal5 ;
        RECT 286.000 354.000 293.000 355.000 ;
    END
    PORT
      LAYER Metal5 ;
        RECT 354.000 286.000 355.000 293.000 ;
    END
    PORT
      LAYER Metal5 ;
        RECT 230.000 354.000 245.000 355.000 ;
    END
    PORT
      LAYER Metal5 ;
        RECT 354.000 230.000 355.000 245.000 ;
    END
    PORT
      LAYER Metal5 ;
        RECT 198.000 354.000 205.000 355.000 ;
    END
    PORT
      LAYER Metal5 ;
        RECT 354.000 198.000 355.000 205.000 ;
    END
    PORT
      LAYER Metal5 ;
        RECT 126.000 354.000 133.000 355.000 ;
    END
    PORT
      LAYER Metal5 ;
        RECT 354.000 126.000 355.000 133.000 ;
    END
    PORT
      LAYER Metal5 ;
        RECT 102.000 354.000 117.000 355.000 ;
    END
    PORT
      LAYER Metal5 ;
        RECT 354.000 102.000 355.000 117.000 ;
    END
    PORT
      LAYER Metal5 ;
        RECT 86.000 354.000 101.000 355.000 ;
    END
    PORT
      LAYER Metal5 ;
        RECT 354.000 86.000 355.000 101.000 ;
    END
    PORT
      LAYER Metal5 ;
        RECT 70.000 354.000 85.000 355.000 ;
    END
    PORT
      LAYER Metal5 ;
        RECT 354.000 70.000 355.000 85.000 ;
    END
    PORT
      LAYER Metal4 ;
        RECT 354.000 70.000 355.000 85.000 ;
    END
    PORT
      LAYER Metal3 ;
        RECT 354.000 70.000 355.000 85.000 ;
    END
    PORT
      LAYER Metal5 ;
        RECT 345.005 346.290 345.385 354.000 ;
    END
    PORT
      LAYER Metal5 ;
        RECT 303.085 237.640 354.000 238.020 ;
    END
    PORT
      LAYER Metal5 ;
        RECT 351.930 286.000 352.310 293.000 ;
    END
    PORT
      LAYER Metal5 ;
        RECT 351.955 302.000 352.335 309.000 ;
    END
    PORT
      LAYER Metal5 ;
        RECT 352.000 326.000 352.380 333.000 ;
    END
    PORT
      LAYER Metal5 ;
        RECT 351.975 342.000 352.355 348.390 ;
    END
    PORT
      LAYER Metal5 ;
        RECT 230.000 350.855 245.000 351.235 ;
    END
    PORT
      LAYER Metal5 ;
        RECT 289.310 323.375 289.690 354.000 ;
    END
    PORT
      LAYER Metal5 ;
        RECT 305.310 330.035 305.690 354.000 ;
    END
    PORT
      LAYER Metal5 ;
        RECT 329.335 340.000 329.715 354.000 ;
    END
    PORT
      LAYER Metal5 ;
        RECT 201.310 286.570 201.690 354.000 ;
    END
    PORT
      LAYER Metal5 ;
        RECT 76.980 236.435 77.360 354.000 ;
    END
    PORT
      LAYER Metal5 ;
        RECT 92.980 243.115 93.360 354.000 ;
    END
    PORT
      LAYER Metal5 ;
        RECT 102.000 350.755 117.000 351.135 ;
    END
    PORT
      LAYER Metal5 ;
        RECT 126.000 350.820 133.000 351.200 ;
    END
    PORT
      LAYER Metal5 ;
        RECT 292.025 94.300 354.000 94.680 ;
    END
    PORT
      LAYER Metal5 ;
        RECT 352.020 70.000 352.400 85.000 ;
    END
    PORT
      LAYER Metal5 ;
        RECT 352.075 102.000 352.455 117.000 ;
    END
    PORT
      LAYER Metal5 ;
        RECT 256.480 129.970 354.000 130.350 ;
    END
    PORT
      LAYER Metal5 ;
        RECT 352.005 198.000 352.385 205.000 ;
    END
  END DVSS
  PIN VDD
    DIRECTION INOUT ;
    USE POWER ;
    PORT
      LAYER Metal3 ;
        RECT 310.000 354.000 317.000 355.000 ;
    END
    PORT
      LAYER Metal3 ;
        RECT 354.000 310.000 355.000 317.000 ;
    END
    PORT
      LAYER Metal3 ;
        RECT 254.000 354.000 261.000 355.000 ;
    END
    PORT
      LAYER Metal4 ;
        RECT 310.000 354.000 317.000 355.000 ;
    END
    PORT
      LAYER Metal4 ;
        RECT 354.000 310.000 355.000 317.000 ;
    END
    PORT
      LAYER Metal4 ;
        RECT 254.000 354.000 261.000 355.000 ;
    END
    PORT
      LAYER Metal5 ;
        RECT 310.000 354.000 317.000 355.000 ;
    END
    PORT
      LAYER Metal5 ;
        RECT 354.000 310.000 355.000 317.000 ;
    END
    PORT
      LAYER Metal5 ;
        RECT 254.000 354.000 261.000 355.000 ;
    END
    PORT
      LAYER Metal5 ;
        RECT 354.000 254.000 355.000 261.000 ;
    END
    PORT
      LAYER Metal4 ;
        RECT 354.000 254.000 355.000 261.000 ;
    END
    PORT
      LAYER Metal3 ;
        RECT 354.000 254.000 355.000 261.000 ;
    END
    PORT
      LAYER Metal5 ;
        RECT 352.735 257.050 352.745 257.060 ;
    END
    PORT
      LAYER Metal5 ;
        RECT 351.965 310.000 352.345 317.000 ;
    END
    PORT
      LAYER Metal5 ;
        RECT 257.310 310.075 257.690 354.000 ;
    END
    PORT
      LAYER Metal5 ;
        RECT 313.310 333.350 313.690 354.000 ;
    END
  END VDD
  PIN VSS
    DIRECTION INOUT ;
    USE GROUND ;
    PORT
      LAYER Metal3 ;
        RECT 318.000 354.000 325.000 355.000 ;
    END
    PORT
      LAYER Metal3 ;
        RECT 354.000 318.000 355.000 325.000 ;
    END
    PORT
      LAYER Metal3 ;
        RECT 246.000 354.000 253.000 355.000 ;
    END
    PORT
      LAYER Metal4 ;
        RECT 318.000 354.000 325.000 355.000 ;
    END
    PORT
      LAYER Metal4 ;
        RECT 354.000 318.000 355.000 325.000 ;
    END
    PORT
      LAYER Metal4 ;
        RECT 246.000 354.000 253.000 355.000 ;
    END
    PORT
      LAYER Metal5 ;
        RECT 318.000 354.000 325.000 355.000 ;
    END
    PORT
      LAYER Metal5 ;
        RECT 354.000 318.000 355.000 325.000 ;
    END
    PORT
      LAYER Metal5 ;
        RECT 246.000 354.000 253.000 355.000 ;
    END
    PORT
      LAYER Metal5 ;
        RECT 354.000 246.000 355.000 253.000 ;
    END
    PORT
      LAYER Metal4 ;
        RECT 354.000 246.000 355.000 253.000 ;
    END
    PORT
      LAYER Metal3 ;
        RECT 354.000 246.000 355.000 253.000 ;
    END
    PORT
      LAYER Metal5 ;
        RECT 352.730 249.875 352.740 249.885 ;
    END
    PORT
      LAYER Metal5 ;
        RECT 351.995 318.000 352.375 325.000 ;
    END
    PORT
      LAYER Metal5 ;
        RECT 246.000 350.880 253.000 351.260 ;
    END
    PORT
      LAYER Metal5 ;
        RECT 321.310 336.710 321.690 354.000 ;
    END
  END VSS
  OBS
      LAYER Metal1 ;
        RECT 65.540 65.540 355.000 355.000 ;
      LAYER Metal2 ;
        RECT 68.030 67.970 354.505 354.450 ;
      LAYER Metal3 ;
        RECT 85.300 353.700 85.700 354.450 ;
        RECT 101.300 353.700 101.700 354.450 ;
        RECT 117.300 353.700 117.700 354.450 ;
        RECT 125.300 353.700 125.700 354.450 ;
        RECT 133.300 353.700 133.700 354.450 ;
        RECT 149.300 353.700 149.700 354.450 ;
        RECT 165.300 353.700 165.700 354.450 ;
        RECT 181.300 353.700 181.700 354.450 ;
        RECT 197.300 353.700 197.700 354.450 ;
        RECT 205.300 353.700 205.700 354.450 ;
        RECT 213.300 353.700 213.700 354.450 ;
        RECT 229.300 353.700 229.700 354.450 ;
        RECT 245.300 353.700 245.700 354.450 ;
        RECT 253.300 353.700 253.700 354.450 ;
        RECT 261.300 353.700 261.700 354.450 ;
        RECT 269.300 353.700 269.700 354.450 ;
        RECT 277.300 353.700 277.700 354.450 ;
        RECT 285.300 353.700 285.700 354.450 ;
        RECT 293.300 353.700 293.700 354.450 ;
        RECT 301.300 353.700 301.700 354.450 ;
        RECT 309.300 353.700 309.700 354.450 ;
        RECT 317.300 353.700 317.700 354.450 ;
        RECT 325.300 353.700 325.700 354.450 ;
        RECT 333.300 353.700 333.700 354.450 ;
        RECT 341.300 353.700 341.700 354.450 ;
        RECT 348.690 353.700 354.000 354.450 ;
        RECT 70.000 348.690 354.000 353.700 ;
        RECT 70.000 341.700 353.700 348.690 ;
        RECT 70.000 341.300 354.000 341.700 ;
        RECT 70.000 333.700 353.700 341.300 ;
        RECT 70.000 333.300 354.000 333.700 ;
        RECT 70.000 325.700 353.700 333.300 ;
        RECT 70.000 325.300 354.000 325.700 ;
        RECT 70.000 317.700 353.700 325.300 ;
        RECT 70.000 317.300 354.000 317.700 ;
        RECT 70.000 309.700 353.700 317.300 ;
        RECT 70.000 309.300 354.000 309.700 ;
        RECT 70.000 301.700 353.700 309.300 ;
        RECT 70.000 301.300 354.000 301.700 ;
        RECT 70.000 293.700 353.700 301.300 ;
        RECT 70.000 293.300 354.000 293.700 ;
        RECT 70.000 285.700 353.700 293.300 ;
        RECT 70.000 285.300 354.000 285.700 ;
        RECT 70.000 277.700 353.700 285.300 ;
        RECT 70.000 277.300 354.000 277.700 ;
        RECT 70.000 269.700 353.700 277.300 ;
        RECT 70.000 269.300 354.000 269.700 ;
        RECT 70.000 261.700 353.700 269.300 ;
        RECT 70.000 261.300 354.000 261.700 ;
        RECT 70.000 253.700 353.700 261.300 ;
        RECT 70.000 253.300 354.000 253.700 ;
        RECT 70.000 245.700 353.700 253.300 ;
        RECT 70.000 245.300 354.000 245.700 ;
        RECT 70.000 229.700 353.700 245.300 ;
        RECT 70.000 229.300 354.000 229.700 ;
        RECT 70.000 213.700 353.700 229.300 ;
        RECT 70.000 213.300 354.000 213.700 ;
        RECT 70.000 205.700 353.700 213.300 ;
        RECT 70.000 205.300 354.000 205.700 ;
        RECT 70.000 197.700 353.700 205.300 ;
        RECT 70.000 197.300 354.000 197.700 ;
        RECT 70.000 181.700 353.700 197.300 ;
        RECT 70.000 181.300 354.000 181.700 ;
        RECT 70.000 165.700 353.700 181.300 ;
        RECT 70.000 165.300 354.000 165.700 ;
        RECT 70.000 149.700 353.700 165.300 ;
        RECT 70.000 149.300 354.000 149.700 ;
        RECT 70.000 133.700 353.700 149.300 ;
        RECT 70.000 133.300 354.000 133.700 ;
        RECT 70.000 125.700 353.700 133.300 ;
        RECT 70.000 125.300 354.000 125.700 ;
        RECT 70.000 117.700 353.700 125.300 ;
        RECT 70.000 117.300 354.000 117.700 ;
        RECT 70.000 101.700 353.700 117.300 ;
        RECT 70.000 101.300 354.000 101.700 ;
        RECT 70.000 85.700 353.700 101.300 ;
        RECT 70.000 85.300 354.000 85.700 ;
        RECT 70.000 70.000 353.700 85.300 ;
      LAYER Metal4 ;
        RECT 85.300 353.700 85.700 354.000 ;
        RECT 101.300 353.700 101.700 354.000 ;
        RECT 117.300 353.700 117.700 354.000 ;
        RECT 125.300 353.700 125.700 354.000 ;
        RECT 133.300 353.700 133.700 354.000 ;
        RECT 149.300 353.700 149.700 354.000 ;
        RECT 165.300 353.700 165.700 354.000 ;
        RECT 181.300 353.700 181.700 354.000 ;
        RECT 197.300 353.700 197.700 354.000 ;
        RECT 205.300 353.700 205.700 354.000 ;
        RECT 213.300 353.700 213.700 354.000 ;
        RECT 229.300 353.700 229.700 354.000 ;
        RECT 245.300 353.700 245.700 354.000 ;
        RECT 253.300 353.700 253.700 354.000 ;
        RECT 261.300 353.700 261.700 354.000 ;
        RECT 269.300 353.700 269.700 354.000 ;
        RECT 277.300 353.700 277.700 354.000 ;
        RECT 285.300 353.700 285.700 354.000 ;
        RECT 293.300 353.700 293.700 354.000 ;
        RECT 301.300 353.700 301.700 354.000 ;
        RECT 309.300 353.700 309.700 354.000 ;
        RECT 317.300 353.700 317.700 354.000 ;
        RECT 325.300 353.700 325.700 354.000 ;
        RECT 333.300 353.700 333.700 354.000 ;
        RECT 341.300 353.700 341.700 354.000 ;
        RECT 348.690 353.700 354.000 354.000 ;
        RECT 70.000 348.690 354.000 353.700 ;
        RECT 70.000 341.700 353.700 348.690 ;
        RECT 70.000 341.300 354.000 341.700 ;
        RECT 70.000 333.700 353.700 341.300 ;
        RECT 70.000 333.300 354.000 333.700 ;
        RECT 70.000 325.700 353.700 333.300 ;
        RECT 70.000 325.300 354.000 325.700 ;
        RECT 70.000 317.700 353.700 325.300 ;
        RECT 70.000 317.300 354.000 317.700 ;
        RECT 70.000 309.700 353.700 317.300 ;
        RECT 70.000 309.300 354.000 309.700 ;
        RECT 70.000 301.700 353.700 309.300 ;
        RECT 70.000 301.300 354.000 301.700 ;
        RECT 70.000 293.700 353.700 301.300 ;
        RECT 70.000 293.300 354.000 293.700 ;
        RECT 70.000 285.700 353.700 293.300 ;
        RECT 70.000 285.300 354.000 285.700 ;
        RECT 70.000 277.700 353.700 285.300 ;
        RECT 70.000 277.300 354.000 277.700 ;
        RECT 70.000 269.700 353.700 277.300 ;
        RECT 70.000 269.300 354.000 269.700 ;
        RECT 70.000 261.700 353.700 269.300 ;
        RECT 70.000 261.300 354.000 261.700 ;
        RECT 70.000 253.700 353.700 261.300 ;
        RECT 70.000 253.300 354.000 253.700 ;
        RECT 70.000 245.700 353.700 253.300 ;
        RECT 70.000 245.300 354.000 245.700 ;
        RECT 70.000 229.700 353.700 245.300 ;
        RECT 70.000 229.300 354.000 229.700 ;
        RECT 70.000 213.700 353.700 229.300 ;
        RECT 70.000 213.300 354.000 213.700 ;
        RECT 70.000 205.700 353.700 213.300 ;
        RECT 70.000 205.300 354.000 205.700 ;
        RECT 70.000 197.700 353.700 205.300 ;
        RECT 70.000 197.300 354.000 197.700 ;
        RECT 70.000 181.700 353.700 197.300 ;
        RECT 70.000 181.300 354.000 181.700 ;
        RECT 70.000 165.700 353.700 181.300 ;
        RECT 70.000 165.300 354.000 165.700 ;
        RECT 70.000 149.700 353.700 165.300 ;
        RECT 70.000 149.300 354.000 149.700 ;
        RECT 70.000 133.700 353.700 149.300 ;
        RECT 70.000 133.300 354.000 133.700 ;
        RECT 70.000 125.700 353.700 133.300 ;
        RECT 70.000 125.300 354.000 125.700 ;
        RECT 70.000 117.700 353.700 125.300 ;
        RECT 70.000 117.300 354.000 117.700 ;
        RECT 70.000 101.700 353.700 117.300 ;
        RECT 70.000 101.300 354.000 101.700 ;
        RECT 70.000 85.700 353.700 101.300 ;
        RECT 70.000 85.300 354.000 85.700 ;
        RECT 70.000 70.000 353.700 85.300 ;
      LAYER Metal5 ;
        RECT 348.890 353.500 354.000 354.000 ;
        RECT 70.000 235.935 76.480 353.500 ;
        RECT 77.860 242.615 92.480 353.500 ;
        RECT 93.860 351.700 139.820 353.500 ;
        RECT 93.860 351.680 125.500 351.700 ;
        RECT 93.860 351.635 117.500 351.680 ;
        RECT 93.860 350.255 101.500 351.635 ;
        RECT 133.500 350.320 139.820 351.700 ;
        RECT 125.500 350.300 139.820 350.320 ;
        RECT 117.500 350.255 139.820 350.300 ;
        RECT 93.860 262.645 139.820 350.255 ;
        RECT 141.200 269.335 155.820 353.500 ;
        RECT 157.200 351.605 187.820 353.500 ;
        RECT 157.200 350.595 171.740 351.605 ;
        RECT 172.750 350.595 187.820 351.605 ;
        RECT 157.200 282.700 187.820 350.595 ;
        RECT 189.200 286.070 200.810 353.500 ;
        RECT 202.190 289.430 208.810 353.500 ;
        RECT 210.190 351.760 256.810 353.500 ;
        RECT 210.190 351.735 245.500 351.760 ;
        RECT 210.190 351.620 229.500 351.735 ;
        RECT 210.190 350.240 213.500 351.620 ;
        RECT 253.500 350.380 256.810 351.760 ;
        RECT 245.500 350.355 256.810 350.380 ;
        RECT 229.500 350.240 256.810 350.355 ;
        RECT 210.190 309.575 256.810 350.240 ;
        RECT 258.190 312.915 264.810 353.500 ;
        RECT 266.190 316.245 272.810 353.500 ;
        RECT 274.190 319.560 280.810 353.500 ;
        RECT 282.190 322.875 288.810 353.500 ;
        RECT 290.190 326.210 296.810 353.500 ;
        RECT 298.190 329.535 304.810 353.500 ;
        RECT 306.190 332.850 312.810 353.500 ;
        RECT 314.190 336.210 320.810 353.500 ;
        RECT 322.190 339.500 328.835 353.500 ;
        RECT 330.215 342.845 336.810 353.500 ;
        RECT 338.190 345.790 344.505 353.500 ;
        RECT 345.885 348.890 354.000 353.500 ;
        RECT 345.885 345.790 351.475 348.890 ;
        RECT 338.190 342.845 351.475 345.790 ;
        RECT 330.215 341.500 351.475 342.845 ;
        RECT 352.855 341.500 353.500 348.890 ;
        RECT 330.215 339.500 351.510 341.500 ;
        RECT 322.190 336.210 351.510 339.500 ;
        RECT 314.190 333.500 351.510 336.210 ;
        RECT 352.890 333.500 353.500 341.500 ;
        RECT 314.190 332.850 351.500 333.500 ;
        RECT 306.190 329.535 351.500 332.850 ;
        RECT 298.190 326.210 351.500 329.535 ;
        RECT 290.190 325.500 351.500 326.210 ;
        RECT 352.880 325.500 353.500 333.500 ;
        RECT 290.190 322.875 351.495 325.500 ;
        RECT 282.190 319.560 351.495 322.875 ;
        RECT 274.190 317.500 351.495 319.560 ;
        RECT 352.875 317.500 353.500 325.500 ;
        RECT 274.190 316.245 351.465 317.500 ;
        RECT 266.190 312.915 351.465 316.245 ;
        RECT 258.190 309.575 351.465 312.915 ;
        RECT 210.190 309.500 351.465 309.575 ;
        RECT 352.845 309.500 353.500 317.500 ;
        RECT 210.190 301.500 351.455 309.500 ;
        RECT 352.835 301.500 353.500 309.500 ;
        RECT 210.190 293.500 351.445 301.500 ;
        RECT 352.825 293.500 353.500 301.500 ;
        RECT 210.190 289.430 351.430 293.500 ;
        RECT 202.190 286.070 351.430 289.430 ;
        RECT 189.200 285.500 351.430 286.070 ;
        RECT 352.810 285.500 353.500 293.500 ;
        RECT 189.200 282.700 351.420 285.500 ;
        RECT 157.200 277.500 351.420 282.700 ;
        RECT 352.800 277.500 353.500 285.500 ;
        RECT 157.200 269.500 351.410 277.500 ;
        RECT 352.790 269.500 353.500 277.500 ;
        RECT 157.200 269.335 353.500 269.500 ;
        RECT 141.200 266.385 353.500 269.335 ;
        RECT 141.200 265.375 351.715 266.385 ;
        RECT 352.725 265.375 353.500 266.385 ;
        RECT 141.200 262.645 353.500 265.375 ;
        RECT 93.860 257.560 353.500 262.645 ;
        RECT 93.860 256.550 352.235 257.560 ;
        RECT 353.245 256.550 353.500 257.560 ;
        RECT 93.860 250.385 353.500 256.550 ;
        RECT 93.860 249.375 352.230 250.385 ;
        RECT 353.240 249.375 353.500 250.385 ;
        RECT 93.860 242.615 353.500 249.375 ;
        RECT 77.860 238.520 353.500 242.615 ;
        RECT 77.860 237.140 302.585 238.520 ;
        RECT 77.860 235.935 353.500 237.140 ;
        RECT 70.000 229.500 353.500 235.935 ;
        RECT 70.000 213.500 351.560 229.500 ;
        RECT 352.940 213.500 353.500 229.500 ;
        RECT 70.000 205.500 351.535 213.500 ;
        RECT 352.915 205.500 353.500 213.500 ;
        RECT 70.000 197.500 351.505 205.500 ;
        RECT 352.885 197.500 353.500 205.500 ;
        RECT 70.000 181.500 351.470 197.500 ;
        RECT 352.850 181.500 353.500 197.500 ;
        RECT 70.000 165.500 351.420 181.500 ;
        RECT 352.800 165.500 353.500 181.500 ;
        RECT 70.000 158.520 353.500 165.500 ;
        RECT 70.000 157.140 292.905 158.520 ;
        RECT 70.000 142.520 353.500 157.140 ;
        RECT 70.000 141.140 292.905 142.520 ;
        RECT 70.000 130.850 353.500 141.140 ;
        RECT 70.000 129.470 255.980 130.850 ;
        RECT 70.000 125.500 353.500 129.470 ;
        RECT 70.000 117.500 351.620 125.500 ;
        RECT 353.000 117.500 353.500 125.500 ;
        RECT 70.000 101.500 351.575 117.500 ;
        RECT 352.955 101.500 353.500 117.500 ;
        RECT 70.000 95.180 353.500 101.500 ;
        RECT 70.000 93.800 291.525 95.180 ;
        RECT 70.000 85.500 353.500 93.800 ;
        RECT 70.000 70.000 351.520 85.500 ;
        RECT 352.900 70.000 353.500 85.500 ;
  END
END gf180mcu_fd_io__cor

#--------EOF---------

#--------EOF---------

MACRO gf180mcu_fd_io__dvdd
  CLASS PAD POWER ;
  FOREIGN gf180mcu_fd_io__dvdd ;
  ORIGIN 0.000 0.000 ;
  SIZE 75.000 BY 350.000 ;
  SYMMETRY X Y R90 ;
  PIN DVDD
    DIRECTION INOUT ;
    USE POWER ;
    PORT
      LAYER Metal5 ;
        RECT 74.000 118.000 75.000 125.000 ;
    END
    PORT
      LAYER Metal5 ;
        RECT 74.000 182.000 75.000 197.000 ;
    END
    PORT
      LAYER Metal5 ;
        RECT 74.000 166.000 75.000 181.000 ;
    END
    PORT
      LAYER Metal5 ;
        RECT 74.000 150.000 75.000 165.000 ;
    END
    PORT
      LAYER Metal5 ;
        RECT 74.000 134.000 75.000 149.000 ;
    END
    PORT
      LAYER Metal5 ;
        RECT 74.000 214.000 75.000 229.000 ;
    END
    PORT
      LAYER Metal5 ;
        RECT 74.000 206.000 75.000 213.000 ;
    END
    PORT
      LAYER Metal5 ;
        RECT 74.000 254.000 75.000 261.000 ;
    END
    PORT
      LAYER Metal5 ;
        RECT 74.000 278.000 75.000 285.000 ;
    END
    PORT
      LAYER Metal5 ;
        RECT 74.000 270.000 75.000 277.000 ;
    END
    PORT
      LAYER Metal5 ;
        RECT 74.000 262.000 75.000 269.000 ;
    END
    PORT
      LAYER Metal5 ;
        RECT 74.000 294.000 75.000 301.000 ;
    END
    PORT
      LAYER Metal5 ;
        RECT 74.000 310.000 75.000 317.000 ;
    END
    PORT
      LAYER Metal5 ;
        RECT 74.000 334.000 75.000 341.000 ;
    END
    PORT
      LAYER Metal4 ;
        RECT 74.000 118.000 75.000 125.000 ;
    END
    PORT
      LAYER Metal4 ;
        RECT 74.000 182.000 75.000 197.000 ;
    END
    PORT
      LAYER Metal4 ;
        RECT 74.000 166.000 75.000 181.000 ;
    END
    PORT
      LAYER Metal4 ;
        RECT 74.000 150.000 75.000 165.000 ;
    END
    PORT
      LAYER Metal4 ;
        RECT 74.000 134.000 75.000 149.000 ;
    END
    PORT
      LAYER Metal4 ;
        RECT 74.000 214.000 75.000 229.000 ;
    END
    PORT
      LAYER Metal4 ;
        RECT 74.000 206.000 75.000 213.000 ;
    END
    PORT
      LAYER Metal4 ;
        RECT 74.000 254.000 75.000 261.000 ;
    END
    PORT
      LAYER Metal4 ;
        RECT 74.000 278.000 75.000 285.000 ;
    END
    PORT
      LAYER Metal4 ;
        RECT 74.000 270.000 75.000 277.000 ;
    END
    PORT
      LAYER Metal4 ;
        RECT 74.000 262.000 75.000 269.000 ;
    END
    PORT
      LAYER Metal4 ;
        RECT 74.000 294.000 75.000 301.000 ;
    END
    PORT
      LAYER Metal4 ;
        RECT 74.000 310.000 75.000 317.000 ;
    END
    PORT
      LAYER Metal4 ;
        RECT 74.000 334.000 75.000 341.000 ;
    END
    PORT
      LAYER Metal3 ;
        RECT 74.000 118.000 75.000 125.000 ;
    END
    PORT
      LAYER Metal3 ;
        RECT 74.000 182.000 75.000 197.000 ;
    END
    PORT
      LAYER Metal3 ;
        RECT 74.000 166.000 75.000 181.000 ;
    END
    PORT
      LAYER Metal3 ;
        RECT 74.000 150.000 75.000 165.000 ;
    END
    PORT
      LAYER Metal3 ;
        RECT 74.000 134.000 75.000 149.000 ;
    END
    PORT
      LAYER Metal3 ;
        RECT 74.000 214.000 75.000 229.000 ;
    END
    PORT
      LAYER Metal3 ;
        RECT 74.000 206.000 75.000 213.000 ;
    END
    PORT
      LAYER Metal3 ;
        RECT 74.000 254.000 75.000 261.000 ;
    END
    PORT
      LAYER Metal3 ;
        RECT 74.000 278.000 75.000 285.000 ;
    END
    PORT
      LAYER Metal3 ;
        RECT 74.000 270.000 75.000 277.000 ;
    END
    PORT
      LAYER Metal3 ;
        RECT 74.000 262.000 75.000 269.000 ;
    END
    PORT
      LAYER Metal3 ;
        RECT 74.000 294.000 75.000 301.000 ;
    END
    PORT
      LAYER Metal3 ;
        RECT 74.000 310.000 75.000 317.000 ;
    END
    PORT
      LAYER Metal3 ;
        RECT 74.000 334.000 75.000 341.000 ;
    END
    PORT
      LAYER Metal2 ;
        RECT 1.360 345.345 10.860 350.000 ;
    END
    PORT
      LAYER Metal2 ;
        RECT 13.760 345.345 24.010 350.000 ;
    END
    PORT
      LAYER Metal2 ;
        RECT 25.610 345.345 35.860 350.000 ;
    END
    PORT
      LAYER Metal2 ;
        RECT 39.140 345.345 49.390 350.000 ;
    END
    PORT
      LAYER Metal2 ;
        RECT 50.990 345.345 61.240 350.000 ;
    END
    PORT
      LAYER Metal3 ;
        RECT 0.000 334.000 1.000 341.000 ;
    END
    PORT
      LAYER Metal3 ;
        RECT 0.000 310.000 1.000 317.000 ;
    END
    PORT
      LAYER Metal3 ;
        RECT 0.000 294.000 1.000 301.000 ;
    END
    PORT
      LAYER Metal3 ;
        RECT 0.000 262.000 1.000 269.000 ;
    END
    PORT
      LAYER Metal3 ;
        RECT 0.000 270.000 1.000 277.000 ;
    END
    PORT
      LAYER Metal3 ;
        RECT 0.000 278.000 1.000 285.000 ;
    END
    PORT
      LAYER Metal3 ;
        RECT 0.000 254.000 1.000 261.000 ;
    END
    PORT
      LAYER Metal3 ;
        RECT 0.000 206.000 1.000 213.000 ;
    END
    PORT
      LAYER Metal3 ;
        RECT 0.000 214.000 1.000 229.000 ;
    END
    PORT
      LAYER Metal3 ;
        RECT 0.000 134.000 1.000 149.000 ;
    END
    PORT
      LAYER Metal3 ;
        RECT 0.000 150.000 1.000 165.000 ;
    END
    PORT
      LAYER Metal3 ;
        RECT 0.000 166.000 1.000 181.000 ;
    END
    PORT
      LAYER Metal3 ;
        RECT 0.000 182.000 1.000 197.000 ;
    END
    PORT
      LAYER Metal4 ;
        RECT 0.000 334.000 1.000 341.000 ;
    END
    PORT
      LAYER Metal4 ;
        RECT 0.000 310.000 1.000 317.000 ;
    END
    PORT
      LAYER Metal4 ;
        RECT 0.000 294.000 1.000 301.000 ;
    END
    PORT
      LAYER Metal4 ;
        RECT 0.000 262.000 1.000 269.000 ;
    END
    PORT
      LAYER Metal4 ;
        RECT 0.000 270.000 1.000 277.000 ;
    END
    PORT
      LAYER Metal4 ;
        RECT 0.000 278.000 1.000 285.000 ;
    END
    PORT
      LAYER Metal4 ;
        RECT 0.000 254.000 1.000 261.000 ;
    END
    PORT
      LAYER Metal4 ;
        RECT 0.000 206.000 1.000 213.000 ;
    END
    PORT
      LAYER Metal4 ;
        RECT 0.000 214.000 1.000 229.000 ;
    END
    PORT
      LAYER Metal4 ;
        RECT 0.000 134.000 1.000 149.000 ;
    END
    PORT
      LAYER Metal4 ;
        RECT 0.000 150.000 1.000 165.000 ;
    END
    PORT
      LAYER Metal4 ;
        RECT 0.000 166.000 1.000 181.000 ;
    END
    PORT
      LAYER Metal4 ;
        RECT 0.000 182.000 1.000 197.000 ;
    END
    PORT
      LAYER Metal5 ;
        RECT 0.000 334.000 1.000 341.000 ;
    END
    PORT
      LAYER Metal5 ;
        RECT 0.000 310.000 1.000 317.000 ;
    END
    PORT
      LAYER Metal5 ;
        RECT 0.000 294.000 1.000 301.000 ;
    END
    PORT
      LAYER Metal5 ;
        RECT 0.000 262.000 1.000 269.000 ;
    END
    PORT
      LAYER Metal5 ;
        RECT 0.000 270.000 1.000 277.000 ;
    END
    PORT
      LAYER Metal5 ;
        RECT 0.000 278.000 1.000 285.000 ;
    END
    PORT
      LAYER Metal5 ;
        RECT 0.000 254.000 1.000 261.000 ;
    END
    PORT
      LAYER Metal5 ;
        RECT 0.000 206.000 1.000 213.000 ;
    END
    PORT
      LAYER Metal5 ;
        RECT 0.000 214.000 1.000 229.000 ;
    END
    PORT
      LAYER Metal5 ;
        RECT 0.000 134.000 1.000 149.000 ;
    END
    PORT
      LAYER Metal5 ;
        RECT 0.000 150.000 1.000 165.000 ;
    END
    PORT
      LAYER Metal5 ;
        RECT 0.000 166.000 1.000 181.000 ;
    END
    PORT
      LAYER Metal5 ;
        RECT 0.000 182.000 1.000 197.000 ;
    END
    PORT
      LAYER Metal5 ;
        RECT 0.000 118.000 1.000 125.000 ;
    END
    PORT
      LAYER Metal4 ;
        RECT 0.000 118.000 1.000 125.000 ;
    END
    PORT
      LAYER Metal3 ;
        RECT 0.000 118.000 1.000 125.000 ;
    END
    PORT
      LAYER Metal2 ;
        RECT 64.140 345.345 73.640 350.000 ;
    END
  END DVDD
  PIN DVSS
    DIRECTION INOUT ;
    USE GROUND ;
    PORT
      LAYER Metal5 ;
        RECT 74.000 102.000 75.000 117.000 ;
    END
    PORT
      LAYER Metal5 ;
        RECT 74.000 86.000 75.000 101.000 ;
    END
    PORT
      LAYER Metal5 ;
        RECT 74.000 70.000 75.000 85.000 ;
    END
    PORT
      LAYER Metal5 ;
        RECT 74.000 126.000 75.000 133.000 ;
    END
    PORT
      LAYER Metal5 ;
        RECT 74.000 198.000 75.000 205.000 ;
    END
    PORT
      LAYER Metal5 ;
        RECT 74.000 230.000 75.000 245.000 ;
    END
    PORT
      LAYER Metal5 ;
        RECT 74.000 286.000 75.000 293.000 ;
    END
    PORT
      LAYER Metal5 ;
        RECT 74.000 302.000 75.000 309.000 ;
    END
    PORT
      LAYER Metal5 ;
        RECT 74.000 326.000 75.000 333.000 ;
    END
    PORT
      LAYER Metal5 ;
        RECT 74.000 342.000 75.000 348.390 ;
    END
    PORT
      LAYER Metal4 ;
        RECT 74.000 102.000 75.000 117.000 ;
    END
    PORT
      LAYER Metal4 ;
        RECT 74.000 86.000 75.000 101.000 ;
    END
    PORT
      LAYER Metal4 ;
        RECT 74.000 70.000 75.000 85.000 ;
    END
    PORT
      LAYER Metal4 ;
        RECT 74.000 126.000 75.000 133.000 ;
    END
    PORT
      LAYER Metal4 ;
        RECT 74.000 198.000 75.000 205.000 ;
    END
    PORT
      LAYER Metal4 ;
        RECT 74.000 230.000 75.000 245.000 ;
    END
    PORT
      LAYER Metal4 ;
        RECT 74.000 286.000 75.000 293.000 ;
    END
    PORT
      LAYER Metal4 ;
        RECT 74.000 302.000 75.000 309.000 ;
    END
    PORT
      LAYER Metal4 ;
        RECT 74.000 326.000 75.000 333.000 ;
    END
    PORT
      LAYER Metal4 ;
        RECT 74.000 342.000 75.000 348.390 ;
    END
    PORT
      LAYER Metal3 ;
        RECT 74.000 102.000 75.000 117.000 ;
    END
    PORT
      LAYER Metal3 ;
        RECT 74.000 86.000 75.000 101.000 ;
    END
    PORT
      LAYER Metal3 ;
        RECT 74.000 70.000 75.000 85.000 ;
    END
    PORT
      LAYER Metal3 ;
        RECT 74.000 126.000 75.000 133.000 ;
    END
    PORT
      LAYER Metal3 ;
        RECT 74.000 198.000 75.000 205.000 ;
    END
    PORT
      LAYER Metal3 ;
        RECT 74.000 230.000 75.000 245.000 ;
    END
    PORT
      LAYER Metal3 ;
        RECT 74.000 286.000 75.000 293.000 ;
    END
    PORT
      LAYER Metal3 ;
        RECT 74.000 302.000 75.000 309.000 ;
    END
    PORT
      LAYER Metal3 ;
        RECT 74.000 326.000 75.000 333.000 ;
    END
    PORT
      LAYER Metal3 ;
        RECT 74.000 342.000 75.000 348.390 ;
    END
    PORT
      LAYER Metal3 ;
        RECT 0.000 342.000 1.000 348.390 ;
    END
    PORT
      LAYER Metal3 ;
        RECT 0.000 326.000 1.000 333.000 ;
    END
    PORT
      LAYER Metal3 ;
        RECT 0.000 302.000 1.000 309.000 ;
    END
    PORT
      LAYER Metal3 ;
        RECT 0.000 286.000 1.000 293.000 ;
    END
    PORT
      LAYER Metal3 ;
        RECT 0.000 230.000 1.000 245.000 ;
    END
    PORT
      LAYER Metal3 ;
        RECT 0.000 198.000 1.000 205.000 ;
    END
    PORT
      LAYER Metal3 ;
        RECT 0.000 126.000 1.000 133.000 ;
    END
    PORT
      LAYER Metal3 ;
        RECT 0.000 70.000 1.000 85.000 ;
    END
    PORT
      LAYER Metal3 ;
        RECT 0.000 86.000 1.000 101.000 ;
    END
    PORT
      LAYER Metal4 ;
        RECT 0.000 342.000 1.000 348.390 ;
    END
    PORT
      LAYER Metal4 ;
        RECT 0.000 326.000 1.000 333.000 ;
    END
    PORT
      LAYER Metal4 ;
        RECT 0.000 302.000 1.000 309.000 ;
    END
    PORT
      LAYER Metal4 ;
        RECT 0.000 286.000 1.000 293.000 ;
    END
    PORT
      LAYER Metal4 ;
        RECT 0.000 230.000 1.000 245.000 ;
    END
    PORT
      LAYER Metal4 ;
        RECT 0.000 198.000 1.000 205.000 ;
    END
    PORT
      LAYER Metal4 ;
        RECT 0.000 126.000 1.000 133.000 ;
    END
    PORT
      LAYER Metal4 ;
        RECT 0.000 70.000 1.000 85.000 ;
    END
    PORT
      LAYER Metal4 ;
        RECT 0.000 86.000 1.000 101.000 ;
    END
    PORT
      LAYER Metal5 ;
        RECT 0.000 342.000 1.000 348.390 ;
    END
    PORT
      LAYER Metal5 ;
        RECT 0.000 326.000 1.000 333.000 ;
    END
    PORT
      LAYER Metal5 ;
        RECT 0.000 302.000 1.000 309.000 ;
    END
    PORT
      LAYER Metal5 ;
        RECT 0.000 286.000 1.000 293.000 ;
    END
    PORT
      LAYER Metal5 ;
        RECT 0.000 230.000 1.000 245.000 ;
    END
    PORT
      LAYER Metal5 ;
        RECT 0.000 198.000 1.000 205.000 ;
    END
    PORT
      LAYER Metal5 ;
        RECT 0.000 126.000 1.000 133.000 ;
    END
    PORT
      LAYER Metal5 ;
        RECT 0.000 70.000 1.000 85.000 ;
    END
    PORT
      LAYER Metal5 ;
        RECT 0.000 86.000 1.000 101.000 ;
    END
    PORT
      LAYER Metal5 ;
        RECT 0.000 102.000 1.000 117.000 ;
    END
    PORT
      LAYER Metal4 ;
        RECT 0.000 102.000 1.000 117.000 ;
    END
    PORT
      LAYER Metal3 ;
        RECT 0.000 102.000 1.000 117.000 ;
    END
  END DVSS
  PIN VSS
    DIRECTION INOUT ;
    USE GROUND ;
    PORT
      LAYER Metal5 ;
        RECT 74.000 246.000 75.000 253.000 ;
    END
    PORT
      LAYER Metal5 ;
        RECT 74.000 318.000 75.000 325.000 ;
    END
    PORT
      LAYER Metal4 ;
        RECT 74.000 246.000 75.000 253.000 ;
    END
    PORT
      LAYER Metal4 ;
        RECT 74.000 318.000 75.000 325.000 ;
    END
    PORT
      LAYER Metal3 ;
        RECT 74.000 246.000 75.000 253.000 ;
    END
    PORT
      LAYER Metal3 ;
        RECT 74.000 318.000 75.000 325.000 ;
    END
    PORT
      LAYER Metal3 ;
        RECT 0.000 318.000 1.000 325.000 ;
    END
    PORT
      LAYER Metal4 ;
        RECT 0.000 318.000 1.000 325.000 ;
    END
    PORT
      LAYER Metal5 ;
        RECT 0.000 318.000 1.000 325.000 ;
    END
    PORT
      LAYER Metal5 ;
        RECT 0.000 246.000 1.000 253.000 ;
    END
    PORT
      LAYER Metal4 ;
        RECT 0.000 246.000 1.000 253.000 ;
    END
    PORT
      LAYER Metal3 ;
        RECT 0.000 246.000 1.000 253.000 ;
    END
  END VSS
  OBS
      LAYER Metal1 ;
        RECT -0.160 65.540 75.160 349.785 ;
      LAYER Metal2 ;
        RECT 0.000 345.045 1.060 348.390 ;
        RECT 11.160 345.045 13.460 348.390 ;
        RECT 24.310 345.045 25.310 348.390 ;
        RECT 36.160 345.045 38.840 348.390 ;
        RECT 49.690 345.045 50.690 348.390 ;
        RECT 61.540 345.045 63.840 348.390 ;
        RECT 73.940 345.045 75.000 348.390 ;
        RECT 0.000 0.000 75.000 345.045 ;
      LAYER Metal3 ;
        RECT 1.300 341.700 73.700 348.390 ;
        RECT 1.000 341.300 74.000 341.700 ;
        RECT 1.300 333.700 73.700 341.300 ;
        RECT 1.000 333.300 74.000 333.700 ;
        RECT 1.300 325.700 73.700 333.300 ;
        RECT 1.000 325.300 74.000 325.700 ;
        RECT 1.300 317.700 73.700 325.300 ;
        RECT 1.000 317.300 74.000 317.700 ;
        RECT 1.300 309.700 73.700 317.300 ;
        RECT 1.000 309.300 74.000 309.700 ;
        RECT 1.300 301.700 73.700 309.300 ;
        RECT 1.000 301.300 74.000 301.700 ;
        RECT 1.300 293.700 73.700 301.300 ;
        RECT 1.000 293.300 74.000 293.700 ;
        RECT 1.300 285.700 73.700 293.300 ;
        RECT 1.000 285.300 74.000 285.700 ;
        RECT 1.300 277.700 73.700 285.300 ;
        RECT 1.000 277.300 74.000 277.700 ;
        RECT 1.300 269.700 73.700 277.300 ;
        RECT 1.000 269.300 74.000 269.700 ;
        RECT 1.300 261.700 73.700 269.300 ;
        RECT 1.000 261.300 74.000 261.700 ;
        RECT 1.300 253.700 73.700 261.300 ;
        RECT 1.000 253.300 74.000 253.700 ;
        RECT 1.300 245.700 73.700 253.300 ;
        RECT 1.000 245.300 74.000 245.700 ;
        RECT 1.300 229.700 73.700 245.300 ;
        RECT 1.000 229.300 74.000 229.700 ;
        RECT 1.300 213.700 73.700 229.300 ;
        RECT 1.000 213.300 74.000 213.700 ;
        RECT 1.300 205.700 73.700 213.300 ;
        RECT 1.000 205.300 74.000 205.700 ;
        RECT 1.300 197.700 73.700 205.300 ;
        RECT 1.000 197.300 74.000 197.700 ;
        RECT 1.300 181.700 73.700 197.300 ;
        RECT 1.000 181.300 74.000 181.700 ;
        RECT 1.300 165.700 73.700 181.300 ;
        RECT 1.000 165.300 74.000 165.700 ;
        RECT 1.300 149.700 73.700 165.300 ;
        RECT 1.000 149.300 74.000 149.700 ;
        RECT 1.300 133.700 73.700 149.300 ;
        RECT 1.000 133.300 74.000 133.700 ;
        RECT 1.300 125.700 73.700 133.300 ;
        RECT 1.000 125.300 74.000 125.700 ;
        RECT 1.300 117.700 73.700 125.300 ;
        RECT 1.000 117.300 74.000 117.700 ;
        RECT 1.300 101.700 73.700 117.300 ;
        RECT 1.000 101.300 74.000 101.700 ;
        RECT 1.300 85.700 73.700 101.300 ;
        RECT 1.000 85.300 74.000 85.700 ;
        RECT 1.300 69.700 73.700 85.300 ;
        RECT 1.000 0.000 74.000 69.700 ;
      LAYER Metal4 ;
        RECT 1.300 341.700 73.700 348.390 ;
        RECT 1.000 341.300 74.000 341.700 ;
        RECT 1.300 333.700 73.700 341.300 ;
        RECT 1.000 333.300 74.000 333.700 ;
        RECT 1.300 325.700 73.700 333.300 ;
        RECT 1.000 325.300 74.000 325.700 ;
        RECT 1.300 317.700 73.700 325.300 ;
        RECT 1.000 317.300 74.000 317.700 ;
        RECT 1.300 309.700 73.700 317.300 ;
        RECT 1.000 309.300 74.000 309.700 ;
        RECT 1.300 301.700 73.700 309.300 ;
        RECT 1.000 301.300 74.000 301.700 ;
        RECT 1.300 293.700 73.700 301.300 ;
        RECT 1.000 293.300 74.000 293.700 ;
        RECT 1.300 285.700 73.700 293.300 ;
        RECT 1.000 285.300 74.000 285.700 ;
        RECT 1.300 277.700 73.700 285.300 ;
        RECT 1.000 277.300 74.000 277.700 ;
        RECT 1.300 269.700 73.700 277.300 ;
        RECT 1.000 269.300 74.000 269.700 ;
        RECT 1.300 261.700 73.700 269.300 ;
        RECT 1.000 261.300 74.000 261.700 ;
        RECT 1.300 253.700 73.700 261.300 ;
        RECT 1.000 253.300 74.000 253.700 ;
        RECT 1.300 245.700 73.700 253.300 ;
        RECT 1.000 245.300 74.000 245.700 ;
        RECT 1.300 229.700 73.700 245.300 ;
        RECT 1.000 229.300 74.000 229.700 ;
        RECT 1.300 213.700 73.700 229.300 ;
        RECT 1.000 213.300 74.000 213.700 ;
        RECT 1.300 205.700 73.700 213.300 ;
        RECT 1.000 205.300 74.000 205.700 ;
        RECT 1.300 197.700 73.700 205.300 ;
        RECT 1.000 197.300 74.000 197.700 ;
        RECT 1.300 181.700 73.700 197.300 ;
        RECT 1.000 181.300 74.000 181.700 ;
        RECT 1.300 165.700 73.700 181.300 ;
        RECT 1.000 165.300 74.000 165.700 ;
        RECT 1.300 149.700 73.700 165.300 ;
        RECT 1.000 149.300 74.000 149.700 ;
        RECT 1.300 133.700 73.700 149.300 ;
        RECT 1.000 133.300 74.000 133.700 ;
        RECT 1.300 125.700 73.700 133.300 ;
        RECT 1.000 125.300 74.000 125.700 ;
        RECT 1.300 117.700 73.700 125.300 ;
        RECT 1.000 117.300 74.000 117.700 ;
        RECT 1.300 101.700 73.700 117.300 ;
        RECT 1.000 101.300 74.000 101.700 ;
        RECT 1.300 85.700 73.700 101.300 ;
        RECT 1.000 85.300 74.000 85.700 ;
        RECT 1.300 69.700 73.700 85.300 ;
        RECT 1.000 0.000 74.000 69.700 ;
      LAYER Metal5 ;
        RECT 1.500 69.500 73.500 348.390 ;
        RECT 1.000 0.000 74.000 69.500 ;
  END
END gf180mcu_fd_io__dvdd

#--------EOF---------

#--------EOF---------

MACRO gf180mcu_fd_io__dvss
  CLASS PAD POWER ;
  FOREIGN gf180mcu_fd_io__dvss ;
  ORIGIN 0.000 0.000 ;
  SIZE 75.000 BY 350.000 ;
  SYMMETRY X Y R90 ;
  PIN DVDD
    DIRECTION INOUT ;
    USE POWER ;
    PORT
      LAYER Metal5 ;
        RECT 74.000 118.000 75.000 125.000 ;
    END
    PORT
      LAYER Metal5 ;
        RECT 74.000 182.000 75.000 197.000 ;
    END
    PORT
      LAYER Metal5 ;
        RECT 74.000 166.000 75.000 181.000 ;
    END
    PORT
      LAYER Metal5 ;
        RECT 74.000 150.000 75.000 165.000 ;
    END
    PORT
      LAYER Metal5 ;
        RECT 74.000 134.000 75.000 149.000 ;
    END
    PORT
      LAYER Metal5 ;
        RECT 74.000 214.000 75.000 229.000 ;
    END
    PORT
      LAYER Metal5 ;
        RECT 74.000 206.000 75.000 213.000 ;
    END
    PORT
      LAYER Metal5 ;
        RECT 74.000 278.000 75.000 285.000 ;
    END
    PORT
      LAYER Metal5 ;
        RECT 74.000 270.000 75.000 277.000 ;
    END
    PORT
      LAYER Metal5 ;
        RECT 74.000 262.000 75.000 269.000 ;
    END
    PORT
      LAYER Metal5 ;
        RECT 74.000 294.000 75.000 301.000 ;
    END
    PORT
      LAYER Metal5 ;
        RECT 74.000 334.000 75.000 341.000 ;
    END
    PORT
      LAYER Metal4 ;
        RECT 74.000 118.000 75.000 125.000 ;
    END
    PORT
      LAYER Metal4 ;
        RECT 74.000 182.000 75.000 197.000 ;
    END
    PORT
      LAYER Metal4 ;
        RECT 74.000 166.000 75.000 181.000 ;
    END
    PORT
      LAYER Metal4 ;
        RECT 74.000 150.000 75.000 165.000 ;
    END
    PORT
      LAYER Metal4 ;
        RECT 74.000 134.000 75.000 149.000 ;
    END
    PORT
      LAYER Metal4 ;
        RECT 74.000 214.000 75.000 229.000 ;
    END
    PORT
      LAYER Metal4 ;
        RECT 74.000 206.000 75.000 213.000 ;
    END
    PORT
      LAYER Metal4 ;
        RECT 74.000 278.000 75.000 285.000 ;
    END
    PORT
      LAYER Metal4 ;
        RECT 74.000 270.000 75.000 277.000 ;
    END
    PORT
      LAYER Metal4 ;
        RECT 74.000 262.000 75.000 269.000 ;
    END
    PORT
      LAYER Metal4 ;
        RECT 74.000 294.000 75.000 301.000 ;
    END
    PORT
      LAYER Metal4 ;
        RECT 74.000 334.000 75.000 341.000 ;
    END
    PORT
      LAYER Metal3 ;
        RECT 74.000 118.000 75.000 125.000 ;
    END
    PORT
      LAYER Metal3 ;
        RECT 74.000 182.000 75.000 197.000 ;
    END
    PORT
      LAYER Metal3 ;
        RECT 74.000 166.000 75.000 181.000 ;
    END
    PORT
      LAYER Metal3 ;
        RECT 74.000 150.000 75.000 165.000 ;
    END
    PORT
      LAYER Metal3 ;
        RECT 74.000 134.000 75.000 149.000 ;
    END
    PORT
      LAYER Metal3 ;
        RECT 74.000 214.000 75.000 229.000 ;
    END
    PORT
      LAYER Metal3 ;
        RECT 74.000 206.000 75.000 213.000 ;
    END
    PORT
      LAYER Metal3 ;
        RECT 74.000 278.000 75.000 285.000 ;
    END
    PORT
      LAYER Metal3 ;
        RECT 74.000 270.000 75.000 277.000 ;
    END
    PORT
      LAYER Metal3 ;
        RECT 74.000 262.000 75.000 269.000 ;
    END
    PORT
      LAYER Metal3 ;
        RECT 74.000 294.000 75.000 301.000 ;
    END
    PORT
      LAYER Metal3 ;
        RECT 74.000 334.000 75.000 341.000 ;
    END
    PORT
      LAYER Metal3 ;
        RECT 0.000 334.000 1.000 341.000 ;
    END
    PORT
      LAYER Metal3 ;
        RECT 0.000 294.000 1.000 301.000 ;
    END
    PORT
      LAYER Metal3 ;
        RECT 0.000 262.000 1.000 269.000 ;
    END
    PORT
      LAYER Metal3 ;
        RECT 0.000 270.000 1.000 277.000 ;
    END
    PORT
      LAYER Metal3 ;
        RECT 0.000 278.000 1.000 285.000 ;
    END
    PORT
      LAYER Metal3 ;
        RECT 0.000 206.000 1.000 213.000 ;
    END
    PORT
      LAYER Metal3 ;
        RECT 0.000 214.000 1.000 229.000 ;
    END
    PORT
      LAYER Metal3 ;
        RECT 0.000 134.000 1.000 149.000 ;
    END
    PORT
      LAYER Metal3 ;
        RECT 0.000 150.000 1.000 165.000 ;
    END
    PORT
      LAYER Metal3 ;
        RECT 0.000 166.000 1.000 181.000 ;
    END
    PORT
      LAYER Metal3 ;
        RECT 0.000 182.000 1.000 197.000 ;
    END
    PORT
      LAYER Metal4 ;
        RECT 0.000 334.000 1.000 341.000 ;
    END
    PORT
      LAYER Metal4 ;
        RECT 0.000 294.000 1.000 301.000 ;
    END
    PORT
      LAYER Metal4 ;
        RECT 0.000 262.000 1.000 269.000 ;
    END
    PORT
      LAYER Metal4 ;
        RECT 0.000 270.000 1.000 277.000 ;
    END
    PORT
      LAYER Metal4 ;
        RECT 0.000 278.000 1.000 285.000 ;
    END
    PORT
      LAYER Metal4 ;
        RECT 0.000 206.000 1.000 213.000 ;
    END
    PORT
      LAYER Metal4 ;
        RECT 0.000 214.000 1.000 229.000 ;
    END
    PORT
      LAYER Metal4 ;
        RECT 0.000 134.000 1.000 149.000 ;
    END
    PORT
      LAYER Metal4 ;
        RECT 0.000 150.000 1.000 165.000 ;
    END
    PORT
      LAYER Metal4 ;
        RECT 0.000 166.000 1.000 181.000 ;
    END
    PORT
      LAYER Metal4 ;
        RECT 0.000 182.000 1.000 197.000 ;
    END
    PORT
      LAYER Metal5 ;
        RECT 0.000 334.000 1.000 341.000 ;
    END
    PORT
      LAYER Metal5 ;
        RECT 0.000 294.000 1.000 301.000 ;
    END
    PORT
      LAYER Metal5 ;
        RECT 0.000 262.000 1.000 269.000 ;
    END
    PORT
      LAYER Metal5 ;
        RECT 0.000 270.000 1.000 277.000 ;
    END
    PORT
      LAYER Metal5 ;
        RECT 0.000 278.000 1.000 285.000 ;
    END
    PORT
      LAYER Metal5 ;
        RECT 0.000 206.000 1.000 213.000 ;
    END
    PORT
      LAYER Metal5 ;
        RECT 0.000 214.000 1.000 229.000 ;
    END
    PORT
      LAYER Metal5 ;
        RECT 0.000 134.000 1.000 149.000 ;
    END
    PORT
      LAYER Metal5 ;
        RECT 0.000 150.000 1.000 165.000 ;
    END
    PORT
      LAYER Metal5 ;
        RECT 0.000 166.000 1.000 181.000 ;
    END
    PORT
      LAYER Metal5 ;
        RECT 0.000 182.000 1.000 197.000 ;
    END
    PORT
      LAYER Metal5 ;
        RECT 0.000 118.000 1.000 125.000 ;
    END
    PORT
      LAYER Metal4 ;
        RECT 0.000 118.000 1.000 125.000 ;
    END
    PORT
      LAYER Metal3 ;
        RECT 0.000 118.000 1.000 125.000 ;
    END
  END DVDD
  PIN DVSS
    DIRECTION INOUT ;
    USE GROUND ;
    PORT
      LAYER Metal5 ;
        RECT 74.000 102.000 75.000 117.000 ;
    END
    PORT
      LAYER Metal5 ;
        RECT 74.000 86.000 75.000 101.000 ;
    END
    PORT
      LAYER Metal5 ;
        RECT 74.000 70.000 75.000 85.000 ;
    END
    PORT
      LAYER Metal5 ;
        RECT 74.000 126.000 75.000 133.000 ;
    END
    PORT
      LAYER Metal5 ;
        RECT 74.000 198.000 75.000 205.000 ;
    END
    PORT
      LAYER Metal5 ;
        RECT 74.000 230.000 75.000 245.000 ;
    END
    PORT
      LAYER Metal5 ;
        RECT 74.000 246.000 75.000 253.000 ;
    END
    PORT
      LAYER Metal5 ;
        RECT 74.000 286.000 75.000 293.000 ;
    END
    PORT
      LAYER Metal5 ;
        RECT 74.000 302.000 75.000 309.000 ;
    END
    PORT
      LAYER Metal5 ;
        RECT 74.000 318.000 75.000 325.000 ;
    END
    PORT
      LAYER Metal5 ;
        RECT 74.000 326.000 75.000 333.000 ;
    END
    PORT
      LAYER Metal5 ;
        RECT 74.000 342.000 75.000 348.390 ;
    END
    PORT
      LAYER Metal4 ;
        RECT 74.000 102.000 75.000 117.000 ;
    END
    PORT
      LAYER Metal4 ;
        RECT 74.000 86.000 75.000 101.000 ;
    END
    PORT
      LAYER Metal4 ;
        RECT 74.000 70.000 75.000 85.000 ;
    END
    PORT
      LAYER Metal4 ;
        RECT 74.000 126.000 75.000 133.000 ;
    END
    PORT
      LAYER Metal4 ;
        RECT 74.000 198.000 75.000 205.000 ;
    END
    PORT
      LAYER Metal4 ;
        RECT 74.000 230.000 75.000 245.000 ;
    END
    PORT
      LAYER Metal4 ;
        RECT 74.000 246.000 75.000 253.000 ;
    END
    PORT
      LAYER Metal4 ;
        RECT 74.000 286.000 75.000 293.000 ;
    END
    PORT
      LAYER Metal4 ;
        RECT 74.000 302.000 75.000 309.000 ;
    END
    PORT
      LAYER Metal4 ;
        RECT 74.000 318.000 75.000 325.000 ;
    END
    PORT
      LAYER Metal4 ;
        RECT 74.000 326.000 75.000 333.000 ;
    END
    PORT
      LAYER Metal4 ;
        RECT 74.000 342.000 75.000 348.390 ;
    END
    PORT
      LAYER Metal3 ;
        RECT 74.000 102.000 75.000 117.000 ;
    END
    PORT
      LAYER Metal3 ;
        RECT 74.000 86.000 75.000 101.000 ;
    END
    PORT
      LAYER Metal3 ;
        RECT 74.000 70.000 75.000 85.000 ;
    END
    PORT
      LAYER Metal3 ;
        RECT 74.000 126.000 75.000 133.000 ;
    END
    PORT
      LAYER Metal3 ;
        RECT 74.000 198.000 75.000 205.000 ;
    END
    PORT
      LAYER Metal3 ;
        RECT 74.000 230.000 75.000 245.000 ;
    END
    PORT
      LAYER Metal3 ;
        RECT 74.000 246.000 75.000 253.000 ;
    END
    PORT
      LAYER Metal3 ;
        RECT 74.000 286.000 75.000 293.000 ;
    END
    PORT
      LAYER Metal3 ;
        RECT 74.000 302.000 75.000 309.000 ;
    END
    PORT
      LAYER Metal3 ;
        RECT 74.000 318.000 75.000 325.000 ;
    END
    PORT
      LAYER Metal3 ;
        RECT 74.000 326.000 75.000 333.000 ;
    END
    PORT
      LAYER Metal3 ;
        RECT 74.000 342.000 75.000 348.390 ;
    END
    PORT
      LAYER Metal2 ;
        RECT 1.360 349.000 10.860 350.000 ;
    END
    PORT
      LAYER Metal2 ;
        RECT 13.760 349.000 24.010 350.000 ;
    END
    PORT
      LAYER Metal2 ;
        RECT 25.610 349.000 35.860 350.000 ;
    END
    PORT
      LAYER Metal2 ;
        RECT 39.140 349.000 49.390 350.000 ;
    END
    PORT
      LAYER Metal2 ;
        RECT 50.990 349.000 61.240 350.000 ;
    END
    PORT
      LAYER Metal3 ;
        RECT 0.000 342.000 1.000 348.390 ;
    END
    PORT
      LAYER Metal3 ;
        RECT 0.000 326.000 1.000 333.000 ;
    END
    PORT
      LAYER Metal3 ;
        RECT 0.000 318.000 1.000 325.000 ;
    END
    PORT
      LAYER Metal3 ;
        RECT 0.000 302.000 1.000 309.000 ;
    END
    PORT
      LAYER Metal3 ;
        RECT 0.000 286.000 1.000 293.000 ;
    END
    PORT
      LAYER Metal3 ;
        RECT 0.000 246.000 1.000 253.000 ;
    END
    PORT
      LAYER Metal3 ;
        RECT 0.000 230.000 1.000 245.000 ;
    END
    PORT
      LAYER Metal3 ;
        RECT 0.000 198.000 1.000 205.000 ;
    END
    PORT
      LAYER Metal3 ;
        RECT 0.000 126.000 1.000 133.000 ;
    END
    PORT
      LAYER Metal3 ;
        RECT 0.000 70.000 1.000 85.000 ;
    END
    PORT
      LAYER Metal3 ;
        RECT 0.000 86.000 1.000 101.000 ;
    END
    PORT
      LAYER Metal4 ;
        RECT 0.000 342.000 1.000 348.390 ;
    END
    PORT
      LAYER Metal4 ;
        RECT 0.000 326.000 1.000 333.000 ;
    END
    PORT
      LAYER Metal4 ;
        RECT 0.000 318.000 1.000 325.000 ;
    END
    PORT
      LAYER Metal4 ;
        RECT 0.000 302.000 1.000 309.000 ;
    END
    PORT
      LAYER Metal4 ;
        RECT 0.000 286.000 1.000 293.000 ;
    END
    PORT
      LAYER Metal4 ;
        RECT 0.000 246.000 1.000 253.000 ;
    END
    PORT
      LAYER Metal4 ;
        RECT 0.000 230.000 1.000 245.000 ;
    END
    PORT
      LAYER Metal4 ;
        RECT 0.000 198.000 1.000 205.000 ;
    END
    PORT
      LAYER Metal4 ;
        RECT 0.000 126.000 1.000 133.000 ;
    END
    PORT
      LAYER Metal4 ;
        RECT 0.000 70.000 1.000 85.000 ;
    END
    PORT
      LAYER Metal4 ;
        RECT 0.000 86.000 1.000 101.000 ;
    END
    PORT
      LAYER Metal5 ;
        RECT 0.000 342.000 1.000 348.390 ;
    END
    PORT
      LAYER Metal5 ;
        RECT 0.000 326.000 1.000 333.000 ;
    END
    PORT
      LAYER Metal5 ;
        RECT 0.000 318.000 1.000 325.000 ;
    END
    PORT
      LAYER Metal5 ;
        RECT 0.000 302.000 1.000 309.000 ;
    END
    PORT
      LAYER Metal5 ;
        RECT 0.000 286.000 1.000 293.000 ;
    END
    PORT
      LAYER Metal5 ;
        RECT 0.000 246.000 1.000 253.000 ;
    END
    PORT
      LAYER Metal5 ;
        RECT 0.000 230.000 1.000 245.000 ;
    END
    PORT
      LAYER Metal5 ;
        RECT 0.000 198.000 1.000 205.000 ;
    END
    PORT
      LAYER Metal5 ;
        RECT 0.000 126.000 1.000 133.000 ;
    END
    PORT
      LAYER Metal5 ;
        RECT 0.000 70.000 1.000 85.000 ;
    END
    PORT
      LAYER Metal5 ;
        RECT 0.000 86.000 1.000 101.000 ;
    END
    PORT
      LAYER Metal5 ;
        RECT 0.000 102.000 1.000 117.000 ;
    END
    PORT
      LAYER Metal4 ;
        RECT 0.000 102.000 1.000 117.000 ;
    END
    PORT
      LAYER Metal3 ;
        RECT 0.000 102.000 1.000 117.000 ;
    END
    PORT
      LAYER Metal2 ;
        RECT 64.140 349.000 73.640 350.000 ;
    END
  END DVSS
  PIN VDD
    DIRECTION INOUT ;
    USE POWER ;
    PORT
      LAYER Metal5 ;
        RECT 74.000 254.000 75.000 261.000 ;
    END
    PORT
      LAYER Metal5 ;
        RECT 74.000 310.000 75.000 317.000 ;
    END
    PORT
      LAYER Metal4 ;
        RECT 74.000 254.000 75.000 261.000 ;
    END
    PORT
      LAYER Metal4 ;
        RECT 74.000 310.000 75.000 317.000 ;
    END
    PORT
      LAYER Metal3 ;
        RECT 74.000 254.000 75.000 261.000 ;
    END
    PORT
      LAYER Metal3 ;
        RECT 74.000 310.000 75.000 317.000 ;
    END
    PORT
      LAYER Metal3 ;
        RECT 0.000 310.000 1.000 317.000 ;
    END
    PORT
      LAYER Metal4 ;
        RECT 0.000 310.000 1.000 317.000 ;
    END
    PORT
      LAYER Metal5 ;
        RECT 0.000 310.000 1.000 317.000 ;
    END
    PORT
      LAYER Metal5 ;
        RECT 0.000 254.000 1.000 261.000 ;
    END
    PORT
      LAYER Metal4 ;
        RECT 0.000 254.000 1.000 261.000 ;
    END
    PORT
      LAYER Metal3 ;
        RECT 0.000 254.000 1.000 261.000 ;
    END
  END VDD
  OBS
      LAYER Metal1 ;
        RECT -0.160 65.540 75.160 349.785 ;
      LAYER Metal2 ;
        RECT 0.000 348.700 1.060 349.000 ;
        RECT 11.160 348.700 13.460 349.000 ;
        RECT 24.310 348.700 25.310 349.000 ;
        RECT 36.160 348.700 38.840 349.000 ;
        RECT 49.690 348.700 50.690 349.000 ;
        RECT 61.540 348.700 63.840 349.000 ;
        RECT 73.940 348.700 75.000 349.000 ;
        RECT 0.000 0.000 75.000 348.700 ;
      LAYER Metal3 ;
        RECT 1.300 341.700 73.700 348.390 ;
        RECT 1.000 341.300 74.000 341.700 ;
        RECT 1.300 333.700 73.700 341.300 ;
        RECT 1.000 333.300 74.000 333.700 ;
        RECT 1.300 325.700 73.700 333.300 ;
        RECT 1.000 325.300 74.000 325.700 ;
        RECT 1.300 317.700 73.700 325.300 ;
        RECT 1.000 317.300 74.000 317.700 ;
        RECT 1.300 309.700 73.700 317.300 ;
        RECT 1.000 309.300 74.000 309.700 ;
        RECT 1.300 301.700 73.700 309.300 ;
        RECT 1.000 301.300 74.000 301.700 ;
        RECT 1.300 293.700 73.700 301.300 ;
        RECT 1.000 293.300 74.000 293.700 ;
        RECT 1.300 285.700 73.700 293.300 ;
        RECT 1.000 285.300 74.000 285.700 ;
        RECT 1.300 277.700 73.700 285.300 ;
        RECT 1.000 277.300 74.000 277.700 ;
        RECT 1.300 269.700 73.700 277.300 ;
        RECT 1.000 269.300 74.000 269.700 ;
        RECT 1.300 261.700 73.700 269.300 ;
        RECT 1.000 261.300 74.000 261.700 ;
        RECT 1.300 253.700 73.700 261.300 ;
        RECT 1.000 253.300 74.000 253.700 ;
        RECT 1.300 245.700 73.700 253.300 ;
        RECT 1.000 245.300 74.000 245.700 ;
        RECT 1.300 229.700 73.700 245.300 ;
        RECT 1.000 229.300 74.000 229.700 ;
        RECT 1.300 213.700 73.700 229.300 ;
        RECT 1.000 213.300 74.000 213.700 ;
        RECT 1.300 205.700 73.700 213.300 ;
        RECT 1.000 205.300 74.000 205.700 ;
        RECT 1.300 197.700 73.700 205.300 ;
        RECT 1.000 197.300 74.000 197.700 ;
        RECT 1.300 181.700 73.700 197.300 ;
        RECT 1.000 181.300 74.000 181.700 ;
        RECT 1.300 165.700 73.700 181.300 ;
        RECT 1.000 165.300 74.000 165.700 ;
        RECT 1.300 149.700 73.700 165.300 ;
        RECT 1.000 149.300 74.000 149.700 ;
        RECT 1.300 133.700 73.700 149.300 ;
        RECT 1.000 133.300 74.000 133.700 ;
        RECT 1.300 125.700 73.700 133.300 ;
        RECT 1.000 125.300 74.000 125.700 ;
        RECT 1.300 117.700 73.700 125.300 ;
        RECT 1.000 117.300 74.000 117.700 ;
        RECT 1.300 101.700 73.700 117.300 ;
        RECT 1.000 101.300 74.000 101.700 ;
        RECT 1.300 85.700 73.700 101.300 ;
        RECT 1.000 85.300 74.000 85.700 ;
        RECT 1.300 69.700 73.700 85.300 ;
        RECT 1.000 0.000 74.000 69.700 ;
      LAYER Metal4 ;
        RECT 1.300 341.700 73.700 348.390 ;
        RECT 1.000 341.300 74.000 341.700 ;
        RECT 1.300 333.700 73.700 341.300 ;
        RECT 1.000 333.300 74.000 333.700 ;
        RECT 1.300 325.700 73.700 333.300 ;
        RECT 1.000 325.300 74.000 325.700 ;
        RECT 1.300 317.700 73.700 325.300 ;
        RECT 1.000 317.300 74.000 317.700 ;
        RECT 1.300 309.700 73.700 317.300 ;
        RECT 1.000 309.300 74.000 309.700 ;
        RECT 1.300 301.700 73.700 309.300 ;
        RECT 1.000 301.300 74.000 301.700 ;
        RECT 1.300 293.700 73.700 301.300 ;
        RECT 1.000 293.300 74.000 293.700 ;
        RECT 1.300 285.700 73.700 293.300 ;
        RECT 1.000 285.300 74.000 285.700 ;
        RECT 1.300 277.700 73.700 285.300 ;
        RECT 1.000 277.300 74.000 277.700 ;
        RECT 1.300 269.700 73.700 277.300 ;
        RECT 1.000 269.300 74.000 269.700 ;
        RECT 1.300 261.700 73.700 269.300 ;
        RECT 1.000 261.300 74.000 261.700 ;
        RECT 1.300 253.700 73.700 261.300 ;
        RECT 1.000 253.300 74.000 253.700 ;
        RECT 1.300 245.700 73.700 253.300 ;
        RECT 1.000 245.300 74.000 245.700 ;
        RECT 1.300 229.700 73.700 245.300 ;
        RECT 1.000 229.300 74.000 229.700 ;
        RECT 1.300 213.700 73.700 229.300 ;
        RECT 1.000 213.300 74.000 213.700 ;
        RECT 1.300 205.700 73.700 213.300 ;
        RECT 1.000 205.300 74.000 205.700 ;
        RECT 1.300 197.700 73.700 205.300 ;
        RECT 1.000 197.300 74.000 197.700 ;
        RECT 1.300 181.700 73.700 197.300 ;
        RECT 1.000 181.300 74.000 181.700 ;
        RECT 1.300 165.700 73.700 181.300 ;
        RECT 1.000 165.300 74.000 165.700 ;
        RECT 1.300 149.700 73.700 165.300 ;
        RECT 1.000 149.300 74.000 149.700 ;
        RECT 1.300 133.700 73.700 149.300 ;
        RECT 1.000 133.300 74.000 133.700 ;
        RECT 1.300 125.700 73.700 133.300 ;
        RECT 1.000 125.300 74.000 125.700 ;
        RECT 1.300 117.700 73.700 125.300 ;
        RECT 1.000 117.300 74.000 117.700 ;
        RECT 1.300 101.700 73.700 117.300 ;
        RECT 1.000 101.300 74.000 101.700 ;
        RECT 1.300 85.700 73.700 101.300 ;
        RECT 1.000 85.300 74.000 85.700 ;
        RECT 1.300 69.700 73.700 85.300 ;
        RECT 1.000 0.000 74.000 69.700 ;
      LAYER Metal5 ;
        RECT 1.500 69.500 73.500 348.390 ;
        RECT 1.000 0.000 74.000 69.500 ;
  END
END gf180mcu_fd_io__dvss

#--------EOF---------

#--------EOF---------

MACRO gf180mcu_fd_io__fill1
  CLASS PAD SPACER ;
  FOREIGN gf180mcu_fd_io__fill1 ;
  ORIGIN 0.000 0.000 ;
  SIZE 1.000 BY 350.000 ;
  SYMMETRY X Y R90 ;
  PIN DVDD
    DIRECTION INOUT ;
    USE POWER ;
    PORT
      LAYER Metal3 ;
        RECT 0.000 334.000 1.000 341.000 ;
    END
    PORT
      LAYER Metal3 ;
        RECT 0.000 294.000 1.000 301.000 ;
    END
    PORT
      LAYER Metal3 ;
        RECT 0.000 278.000 1.000 285.000 ;
    END
    PORT
      LAYER Metal3 ;
        RECT 0.000 270.000 1.000 277.000 ;
    END
    PORT
      LAYER Metal3 ;
        RECT 0.000 262.000 1.000 269.000 ;
    END
    PORT
      LAYER Metal3 ;
        RECT 0.000 214.000 1.000 229.000 ;
    END
    PORT
      LAYER Metal3 ;
        RECT 0.000 206.000 1.000 213.000 ;
    END
    PORT
      LAYER Metal3 ;
        RECT 0.000 182.000 1.000 197.000 ;
    END
    PORT
      LAYER Metal3 ;
        RECT 0.000 166.000 1.000 181.000 ;
    END
    PORT
      LAYER Metal3 ;
        RECT 0.000 150.000 1.000 165.000 ;
    END
    PORT
      LAYER Metal3 ;
        RECT 0.000 134.000 1.000 149.000 ;
    END
    PORT
      LAYER Metal4 ;
        RECT 0.000 334.000 1.000 341.000 ;
    END
    PORT
      LAYER Metal4 ;
        RECT 0.000 294.000 1.000 301.000 ;
    END
    PORT
      LAYER Metal4 ;
        RECT 0.000 278.000 1.000 285.000 ;
    END
    PORT
      LAYER Metal4 ;
        RECT 0.000 270.000 1.000 277.000 ;
    END
    PORT
      LAYER Metal4 ;
        RECT 0.000 262.000 1.000 269.000 ;
    END
    PORT
      LAYER Metal4 ;
        RECT 0.000 214.000 1.000 229.000 ;
    END
    PORT
      LAYER Metal4 ;
        RECT 0.000 206.000 1.000 213.000 ;
    END
    PORT
      LAYER Metal4 ;
        RECT 0.000 182.000 1.000 197.000 ;
    END
    PORT
      LAYER Metal4 ;
        RECT 0.000 166.000 1.000 181.000 ;
    END
    PORT
      LAYER Metal4 ;
        RECT 0.000 150.000 1.000 165.000 ;
    END
    PORT
      LAYER Metal4 ;
        RECT 0.000 134.000 1.000 149.000 ;
    END
    PORT
      LAYER Metal5 ;
        RECT 0.000 334.000 1.000 341.000 ;
    END
    PORT
      LAYER Metal5 ;
        RECT 0.000 294.000 1.000 301.000 ;
    END
    PORT
      LAYER Metal5 ;
        RECT 0.000 278.000 1.000 285.000 ;
    END
    PORT
      LAYER Metal5 ;
        RECT 0.000 270.000 1.000 277.000 ;
    END
    PORT
      LAYER Metal5 ;
        RECT 0.000 262.000 1.000 269.000 ;
    END
    PORT
      LAYER Metal5 ;
        RECT 0.000 214.000 1.000 229.000 ;
    END
    PORT
      LAYER Metal5 ;
        RECT 0.000 206.000 1.000 213.000 ;
    END
    PORT
      LAYER Metal5 ;
        RECT 0.000 182.000 1.000 197.000 ;
    END
    PORT
      LAYER Metal5 ;
        RECT 0.000 166.000 1.000 181.000 ;
    END
    PORT
      LAYER Metal5 ;
        RECT 0.000 150.000 1.000 165.000 ;
    END
    PORT
      LAYER Metal5 ;
        RECT 0.000 134.000 1.000 149.000 ;
    END
    PORT
      LAYER Metal5 ;
        RECT 0.000 118.000 1.000 125.000 ;
    END
    PORT
      LAYER Metal4 ;
        RECT 0.000 118.000 1.000 125.000 ;
    END
    PORT
      LAYER Metal3 ;
        RECT 0.000 118.000 1.000 125.000 ;
    END
  END DVDD
  PIN DVSS
    DIRECTION INOUT ;
    USE GROUND ;
    PORT
      LAYER Metal3 ;
        RECT 0.000 342.000 1.000 348.390 ;
    END
    PORT
      LAYER Metal3 ;
        RECT 0.000 326.000 1.000 333.000 ;
    END
    PORT
      LAYER Metal3 ;
        RECT 0.000 302.000 1.000 309.000 ;
    END
    PORT
      LAYER Metal3 ;
        RECT 0.000 286.000 1.000 293.000 ;
    END
    PORT
      LAYER Metal3 ;
        RECT 0.000 230.000 1.000 245.000 ;
    END
    PORT
      LAYER Metal3 ;
        RECT 0.000 198.000 1.000 205.000 ;
    END
    PORT
      LAYER Metal3 ;
        RECT 0.000 126.000 1.000 133.000 ;
    END
    PORT
      LAYER Metal3 ;
        RECT 0.000 102.000 1.000 117.000 ;
    END
    PORT
      LAYER Metal3 ;
        RECT 0.000 86.000 1.000 101.000 ;
    END
    PORT
      LAYER Metal4 ;
        RECT 0.000 342.000 1.000 348.390 ;
    END
    PORT
      LAYER Metal4 ;
        RECT 0.000 326.000 1.000 333.000 ;
    END
    PORT
      LAYER Metal4 ;
        RECT 0.000 302.000 1.000 309.000 ;
    END
    PORT
      LAYER Metal4 ;
        RECT 0.000 286.000 1.000 293.000 ;
    END
    PORT
      LAYER Metal4 ;
        RECT 0.000 230.000 1.000 245.000 ;
    END
    PORT
      LAYER Metal4 ;
        RECT 0.000 198.000 1.000 205.000 ;
    END
    PORT
      LAYER Metal4 ;
        RECT 0.000 126.000 1.000 133.000 ;
    END
    PORT
      LAYER Metal4 ;
        RECT 0.000 102.000 1.000 117.000 ;
    END
    PORT
      LAYER Metal4 ;
        RECT 0.000 86.000 1.000 101.000 ;
    END
    PORT
      LAYER Metal5 ;
        RECT 0.000 342.000 1.000 348.390 ;
    END
    PORT
      LAYER Metal5 ;
        RECT 0.000 326.000 1.000 333.000 ;
    END
    PORT
      LAYER Metal5 ;
        RECT 0.000 302.000 1.000 309.000 ;
    END
    PORT
      LAYER Metal5 ;
        RECT 0.000 286.000 1.000 293.000 ;
    END
    PORT
      LAYER Metal5 ;
        RECT 0.000 230.000 1.000 245.000 ;
    END
    PORT
      LAYER Metal5 ;
        RECT 0.000 198.000 1.000 205.000 ;
    END
    PORT
      LAYER Metal5 ;
        RECT 0.000 126.000 1.000 133.000 ;
    END
    PORT
      LAYER Metal5 ;
        RECT 0.000 102.000 1.000 117.000 ;
    END
    PORT
      LAYER Metal5 ;
        RECT 0.000 86.000 1.000 101.000 ;
    END
    PORT
      LAYER Metal5 ;
        RECT 0.000 70.000 1.000 85.000 ;
    END
    PORT
      LAYER Metal4 ;
        RECT 0.000 70.000 1.000 85.000 ;
    END
    PORT
      LAYER Metal3 ;
        RECT 0.000 70.000 1.000 85.000 ;
    END
  END DVSS
  PIN VDD
    DIRECTION INOUT ;
    USE POWER ;
    PORT
      LAYER Metal3 ;
        RECT 0.000 310.000 1.000 317.000 ;
    END
    PORT
      LAYER Metal4 ;
        RECT 0.000 310.000 1.000 317.000 ;
    END
    PORT
      LAYER Metal5 ;
        RECT 0.000 310.000 1.000 317.000 ;
    END
    PORT
      LAYER Metal5 ;
        RECT 0.000 254.000 1.000 261.000 ;
    END
    PORT
      LAYER Metal4 ;
        RECT 0.000 254.000 1.000 261.000 ;
    END
    PORT
      LAYER Metal3 ;
        RECT 0.000 254.000 1.000 261.000 ;
    END
  END VDD
  PIN VSS
    DIRECTION INOUT ;
    USE GROUND ;
    PORT
      LAYER Metal3 ;
        RECT 0.000 318.000 1.000 325.000 ;
    END
    PORT
      LAYER Metal4 ;
        RECT 0.000 318.000 1.000 325.000 ;
    END
    PORT
      LAYER Metal5 ;
        RECT 0.000 318.000 1.000 325.000 ;
    END
    PORT
      LAYER Metal5 ;
        RECT 0.000 246.000 1.000 253.000 ;
    END
    PORT
      LAYER Metal4 ;
        RECT 0.000 246.000 1.000 253.000 ;
    END
    PORT
      LAYER Metal3 ;
        RECT 0.000 246.000 1.000 253.000 ;
    END
  END VSS
  OBS
      LAYER Metal1 ;
        RECT -0.160 65.485 1.160 349.785 ;
      LAYER Metal2 ;
        RECT 0.000 246.000 1.000 325.000 ;
  END
END gf180mcu_fd_io__fill1

#--------EOF---------

#--------EOF---------

MACRO gf180mcu_fd_io__fill5
  CLASS PAD SPACER ;
  FOREIGN gf180mcu_fd_io__fill5 ;
  ORIGIN 0.000 0.000 ;
  SIZE 5.000 BY 350.000 ;
  SYMMETRY X Y R90 ;
  PIN DVDD
    DIRECTION INOUT ;
    USE POWER ;
    PORT
      LAYER Metal5 ;
        RECT 4.000 134.000 5.000 149.000 ;
    END
    PORT
      LAYER Metal5 ;
        RECT 4.000 150.000 5.000 165.000 ;
    END
    PORT
      LAYER Metal5 ;
        RECT 4.000 166.000 5.000 181.000 ;
    END
    PORT
      LAYER Metal5 ;
        RECT 4.000 182.000 5.000 197.000 ;
    END
    PORT
      LAYER Metal5 ;
        RECT 4.000 214.000 5.000 229.000 ;
    END
    PORT
      LAYER Metal5 ;
        RECT 4.000 118.000 5.000 125.000 ;
    END
    PORT
      LAYER Metal5 ;
        RECT 4.000 206.000 5.000 213.000 ;
    END
    PORT
      LAYER Metal5 ;
        RECT 4.000 262.000 5.000 269.000 ;
    END
    PORT
      LAYER Metal5 ;
        RECT 4.000 270.000 5.000 277.000 ;
    END
    PORT
      LAYER Metal5 ;
        RECT 4.000 278.000 5.000 285.000 ;
    END
    PORT
      LAYER Metal5 ;
        RECT 4.000 294.000 5.000 301.000 ;
    END
    PORT
      LAYER Metal5 ;
        RECT 4.000 334.000 5.000 341.000 ;
    END
    PORT
      LAYER Metal4 ;
        RECT 4.000 134.000 5.000 149.000 ;
    END
    PORT
      LAYER Metal4 ;
        RECT 4.000 150.000 5.000 165.000 ;
    END
    PORT
      LAYER Metal4 ;
        RECT 4.000 166.000 5.000 181.000 ;
    END
    PORT
      LAYER Metal4 ;
        RECT 4.000 182.000 5.000 197.000 ;
    END
    PORT
      LAYER Metal4 ;
        RECT 4.000 214.000 5.000 229.000 ;
    END
    PORT
      LAYER Metal4 ;
        RECT 4.000 118.000 5.000 125.000 ;
    END
    PORT
      LAYER Metal4 ;
        RECT 4.000 206.000 5.000 213.000 ;
    END
    PORT
      LAYER Metal4 ;
        RECT 4.000 262.000 5.000 269.000 ;
    END
    PORT
      LAYER Metal4 ;
        RECT 4.000 270.000 5.000 277.000 ;
    END
    PORT
      LAYER Metal4 ;
        RECT 4.000 278.000 5.000 285.000 ;
    END
    PORT
      LAYER Metal4 ;
        RECT 4.000 294.000 5.000 301.000 ;
    END
    PORT
      LAYER Metal4 ;
        RECT 4.000 334.000 5.000 341.000 ;
    END
    PORT
      LAYER Metal3 ;
        RECT 4.000 134.000 5.000 149.000 ;
    END
    PORT
      LAYER Metal3 ;
        RECT 4.000 150.000 5.000 165.000 ;
    END
    PORT
      LAYER Metal3 ;
        RECT 4.000 166.000 5.000 181.000 ;
    END
    PORT
      LAYER Metal3 ;
        RECT 4.000 182.000 5.000 197.000 ;
    END
    PORT
      LAYER Metal3 ;
        RECT 4.000 214.000 5.000 229.000 ;
    END
    PORT
      LAYER Metal3 ;
        RECT 4.000 118.000 5.000 125.000 ;
    END
    PORT
      LAYER Metal3 ;
        RECT 4.000 206.000 5.000 213.000 ;
    END
    PORT
      LAYER Metal3 ;
        RECT 4.000 262.000 5.000 269.000 ;
    END
    PORT
      LAYER Metal3 ;
        RECT 4.000 270.000 5.000 277.000 ;
    END
    PORT
      LAYER Metal3 ;
        RECT 4.000 278.000 5.000 285.000 ;
    END
    PORT
      LAYER Metal3 ;
        RECT 4.000 294.000 5.000 301.000 ;
    END
    PORT
      LAYER Metal3 ;
        RECT 4.000 334.000 5.000 341.000 ;
    END
    PORT
      LAYER Metal3 ;
        RECT 0.000 334.000 1.000 341.000 ;
    END
    PORT
      LAYER Metal3 ;
        RECT 0.000 294.000 1.000 301.000 ;
    END
    PORT
      LAYER Metal3 ;
        RECT 0.000 278.000 1.000 285.000 ;
    END
    PORT
      LAYER Metal3 ;
        RECT 0.000 270.000 1.000 277.000 ;
    END
    PORT
      LAYER Metal3 ;
        RECT 0.000 262.000 1.000 269.000 ;
    END
    PORT
      LAYER Metal3 ;
        RECT 0.000 214.000 1.000 229.000 ;
    END
    PORT
      LAYER Metal3 ;
        RECT 0.000 206.000 1.000 213.000 ;
    END
    PORT
      LAYER Metal3 ;
        RECT 0.000 182.000 1.000 197.000 ;
    END
    PORT
      LAYER Metal3 ;
        RECT 0.000 166.000 1.000 181.000 ;
    END
    PORT
      LAYER Metal3 ;
        RECT 0.000 150.000 1.000 165.000 ;
    END
    PORT
      LAYER Metal3 ;
        RECT 0.000 134.000 1.000 149.000 ;
    END
    PORT
      LAYER Metal4 ;
        RECT 0.000 334.000 1.000 341.000 ;
    END
    PORT
      LAYER Metal4 ;
        RECT 0.000 294.000 1.000 301.000 ;
    END
    PORT
      LAYER Metal4 ;
        RECT 0.000 278.000 1.000 285.000 ;
    END
    PORT
      LAYER Metal4 ;
        RECT 0.000 270.000 1.000 277.000 ;
    END
    PORT
      LAYER Metal4 ;
        RECT 0.000 262.000 1.000 269.000 ;
    END
    PORT
      LAYER Metal4 ;
        RECT 0.000 214.000 1.000 229.000 ;
    END
    PORT
      LAYER Metal4 ;
        RECT 0.000 206.000 1.000 213.000 ;
    END
    PORT
      LAYER Metal4 ;
        RECT 0.000 182.000 1.000 197.000 ;
    END
    PORT
      LAYER Metal4 ;
        RECT 0.000 166.000 1.000 181.000 ;
    END
    PORT
      LAYER Metal4 ;
        RECT 0.000 150.000 1.000 165.000 ;
    END
    PORT
      LAYER Metal4 ;
        RECT 0.000 134.000 1.000 149.000 ;
    END
    PORT
      LAYER Metal5 ;
        RECT 0.000 334.000 1.000 341.000 ;
    END
    PORT
      LAYER Metal5 ;
        RECT 0.000 294.000 1.000 301.000 ;
    END
    PORT
      LAYER Metal5 ;
        RECT 0.000 278.000 1.000 285.000 ;
    END
    PORT
      LAYER Metal5 ;
        RECT 0.000 270.000 1.000 277.000 ;
    END
    PORT
      LAYER Metal5 ;
        RECT 0.000 262.000 1.000 269.000 ;
    END
    PORT
      LAYER Metal5 ;
        RECT 0.000 214.000 1.000 229.000 ;
    END
    PORT
      LAYER Metal5 ;
        RECT 0.000 206.000 1.000 213.000 ;
    END
    PORT
      LAYER Metal5 ;
        RECT 0.000 182.000 1.000 197.000 ;
    END
    PORT
      LAYER Metal5 ;
        RECT 0.000 166.000 1.000 181.000 ;
    END
    PORT
      LAYER Metal5 ;
        RECT 0.000 150.000 1.000 165.000 ;
    END
    PORT
      LAYER Metal5 ;
        RECT 0.000 134.000 1.000 149.000 ;
    END
    PORT
      LAYER Metal5 ;
        RECT 0.000 118.000 1.000 125.000 ;
    END
    PORT
      LAYER Metal4 ;
        RECT 0.000 118.000 1.000 125.000 ;
    END
    PORT
      LAYER Metal3 ;
        RECT 0.000 118.000 1.000 125.000 ;
    END
  END DVDD
  PIN DVSS
    DIRECTION INOUT ;
    USE GROUND ;
    PORT
      LAYER Metal5 ;
        RECT 4.000 70.000 5.000 85.000 ;
    END
    PORT
      LAYER Metal5 ;
        RECT 4.000 86.000 5.000 101.000 ;
    END
    PORT
      LAYER Metal5 ;
        RECT 4.000 102.000 5.000 117.000 ;
    END
    PORT
      LAYER Metal5 ;
        RECT 4.000 230.000 5.000 245.000 ;
    END
    PORT
      LAYER Metal5 ;
        RECT 4.000 126.000 5.000 133.000 ;
    END
    PORT
      LAYER Metal5 ;
        RECT 4.000 198.000 5.000 205.000 ;
    END
    PORT
      LAYER Metal5 ;
        RECT 4.000 286.000 5.000 293.000 ;
    END
    PORT
      LAYER Metal5 ;
        RECT 4.000 302.000 5.000 309.000 ;
    END
    PORT
      LAYER Metal5 ;
        RECT 4.000 326.000 5.000 333.000 ;
    END
    PORT
      LAYER Metal5 ;
        RECT 4.000 342.000 5.000 348.390 ;
    END
    PORT
      LAYER Metal4 ;
        RECT 4.000 70.000 5.000 85.000 ;
    END
    PORT
      LAYER Metal4 ;
        RECT 4.000 86.000 5.000 101.000 ;
    END
    PORT
      LAYER Metal4 ;
        RECT 4.000 102.000 5.000 117.000 ;
    END
    PORT
      LAYER Metal4 ;
        RECT 4.000 230.000 5.000 245.000 ;
    END
    PORT
      LAYER Metal4 ;
        RECT 4.000 126.000 5.000 133.000 ;
    END
    PORT
      LAYER Metal4 ;
        RECT 4.000 198.000 5.000 205.000 ;
    END
    PORT
      LAYER Metal4 ;
        RECT 4.000 286.000 5.000 293.000 ;
    END
    PORT
      LAYER Metal4 ;
        RECT 4.000 302.000 5.000 309.000 ;
    END
    PORT
      LAYER Metal4 ;
        RECT 4.000 326.000 5.000 333.000 ;
    END
    PORT
      LAYER Metal4 ;
        RECT 4.000 342.000 5.000 348.390 ;
    END
    PORT
      LAYER Metal3 ;
        RECT 4.000 70.000 5.000 85.000 ;
    END
    PORT
      LAYER Metal3 ;
        RECT 4.000 86.000 5.000 101.000 ;
    END
    PORT
      LAYER Metal3 ;
        RECT 4.000 102.000 5.000 117.000 ;
    END
    PORT
      LAYER Metal3 ;
        RECT 4.000 230.000 5.000 245.000 ;
    END
    PORT
      LAYER Metal3 ;
        RECT 4.000 126.000 5.000 133.000 ;
    END
    PORT
      LAYER Metal3 ;
        RECT 4.000 198.000 5.000 205.000 ;
    END
    PORT
      LAYER Metal3 ;
        RECT 4.000 286.000 5.000 293.000 ;
    END
    PORT
      LAYER Metal3 ;
        RECT 4.000 302.000 5.000 309.000 ;
    END
    PORT
      LAYER Metal3 ;
        RECT 4.000 326.000 5.000 333.000 ;
    END
    PORT
      LAYER Metal3 ;
        RECT 4.000 342.000 5.000 348.390 ;
    END
    PORT
      LAYER Metal3 ;
        RECT 0.000 342.000 1.000 348.390 ;
    END
    PORT
      LAYER Metal3 ;
        RECT 0.000 326.000 1.000 333.000 ;
    END
    PORT
      LAYER Metal3 ;
        RECT 0.000 302.000 1.000 309.000 ;
    END
    PORT
      LAYER Metal3 ;
        RECT 0.000 286.000 1.000 293.000 ;
    END
    PORT
      LAYER Metal3 ;
        RECT 0.000 230.000 1.000 245.000 ;
    END
    PORT
      LAYER Metal3 ;
        RECT 0.000 198.000 1.000 205.000 ;
    END
    PORT
      LAYER Metal3 ;
        RECT 0.000 126.000 1.000 133.000 ;
    END
    PORT
      LAYER Metal3 ;
        RECT 0.000 102.000 1.000 117.000 ;
    END
    PORT
      LAYER Metal3 ;
        RECT 0.000 86.000 1.000 101.000 ;
    END
    PORT
      LAYER Metal4 ;
        RECT 0.000 342.000 1.000 348.390 ;
    END
    PORT
      LAYER Metal4 ;
        RECT 0.000 326.000 1.000 333.000 ;
    END
    PORT
      LAYER Metal4 ;
        RECT 0.000 302.000 1.000 309.000 ;
    END
    PORT
      LAYER Metal4 ;
        RECT 0.000 286.000 1.000 293.000 ;
    END
    PORT
      LAYER Metal4 ;
        RECT 0.000 230.000 1.000 245.000 ;
    END
    PORT
      LAYER Metal4 ;
        RECT 0.000 198.000 1.000 205.000 ;
    END
    PORT
      LAYER Metal4 ;
        RECT 0.000 126.000 1.000 133.000 ;
    END
    PORT
      LAYER Metal4 ;
        RECT 0.000 102.000 1.000 117.000 ;
    END
    PORT
      LAYER Metal4 ;
        RECT 0.000 86.000 1.000 101.000 ;
    END
    PORT
      LAYER Metal5 ;
        RECT 0.000 342.000 1.000 348.390 ;
    END
    PORT
      LAYER Metal5 ;
        RECT 0.000 326.000 1.000 333.000 ;
    END
    PORT
      LAYER Metal5 ;
        RECT 0.000 302.000 1.000 309.000 ;
    END
    PORT
      LAYER Metal5 ;
        RECT 0.000 286.000 1.000 293.000 ;
    END
    PORT
      LAYER Metal5 ;
        RECT 0.000 230.000 1.000 245.000 ;
    END
    PORT
      LAYER Metal5 ;
        RECT 0.000 198.000 1.000 205.000 ;
    END
    PORT
      LAYER Metal5 ;
        RECT 0.000 126.000 1.000 133.000 ;
    END
    PORT
      LAYER Metal5 ;
        RECT 0.000 102.000 1.000 117.000 ;
    END
    PORT
      LAYER Metal5 ;
        RECT 0.000 86.000 1.000 101.000 ;
    END
    PORT
      LAYER Metal5 ;
        RECT 0.000 70.000 1.000 85.000 ;
    END
    PORT
      LAYER Metal4 ;
        RECT 0.000 70.000 1.000 85.000 ;
    END
    PORT
      LAYER Metal3 ;
        RECT 0.000 70.000 1.000 85.000 ;
    END
  END DVSS
  PIN VDD
    DIRECTION INOUT ;
    USE POWER ;
    PORT
      LAYER Metal5 ;
        RECT 4.000 254.000 5.000 261.000 ;
    END
    PORT
      LAYER Metal5 ;
        RECT 4.000 310.000 5.000 317.000 ;
    END
    PORT
      LAYER Metal4 ;
        RECT 4.000 254.000 5.000 261.000 ;
    END
    PORT
      LAYER Metal4 ;
        RECT 4.000 310.000 5.000 317.000 ;
    END
    PORT
      LAYER Metal3 ;
        RECT 4.000 254.000 5.000 261.000 ;
    END
    PORT
      LAYER Metal3 ;
        RECT 4.000 310.000 5.000 317.000 ;
    END
    PORT
      LAYER Metal3 ;
        RECT 0.000 310.000 1.000 317.000 ;
    END
    PORT
      LAYER Metal4 ;
        RECT 0.000 310.000 1.000 317.000 ;
    END
    PORT
      LAYER Metal5 ;
        RECT 0.000 310.000 1.000 317.000 ;
    END
    PORT
      LAYER Metal5 ;
        RECT 0.000 254.000 1.000 261.000 ;
    END
    PORT
      LAYER Metal4 ;
        RECT 0.000 254.000 1.000 261.000 ;
    END
    PORT
      LAYER Metal3 ;
        RECT 0.000 254.000 1.000 261.000 ;
    END
  END VDD
  PIN VSS
    DIRECTION INOUT ;
    USE GROUND ;
    PORT
      LAYER Metal5 ;
        RECT 4.000 246.000 5.000 253.000 ;
    END
    PORT
      LAYER Metal5 ;
        RECT 4.000 318.000 5.000 325.000 ;
    END
    PORT
      LAYER Metal4 ;
        RECT 4.000 246.000 5.000 253.000 ;
    END
    PORT
      LAYER Metal4 ;
        RECT 4.000 318.000 5.000 325.000 ;
    END
    PORT
      LAYER Metal3 ;
        RECT 4.000 246.000 5.000 253.000 ;
    END
    PORT
      LAYER Metal3 ;
        RECT 4.000 318.000 5.000 325.000 ;
    END
    PORT
      LAYER Metal3 ;
        RECT 0.000 318.000 1.000 325.000 ;
    END
    PORT
      LAYER Metal4 ;
        RECT 0.000 318.000 1.000 325.000 ;
    END
    PORT
      LAYER Metal5 ;
        RECT 0.000 318.000 1.000 325.000 ;
    END
    PORT
      LAYER Metal5 ;
        RECT 0.000 246.000 1.000 253.000 ;
    END
    PORT
      LAYER Metal4 ;
        RECT 0.000 246.000 1.000 253.000 ;
    END
    PORT
      LAYER Metal3 ;
        RECT 0.000 246.000 1.000 253.000 ;
    END
  END VSS
  OBS
      LAYER Metal1 ;
        RECT -0.160 65.540 5.160 349.785 ;
      LAYER Metal2 ;
        RECT 0.000 67.350 5.000 348.300 ;
      LAYER Metal3 ;
        RECT 1.300 341.700 3.700 348.390 ;
        RECT 1.000 341.300 4.000 341.700 ;
        RECT 1.300 333.700 3.700 341.300 ;
        RECT 1.000 333.300 4.000 333.700 ;
        RECT 1.300 325.700 3.700 333.300 ;
        RECT 1.000 325.300 4.000 325.700 ;
        RECT 1.300 317.700 3.700 325.300 ;
        RECT 1.000 317.300 4.000 317.700 ;
        RECT 1.300 309.700 3.700 317.300 ;
        RECT 1.000 309.300 4.000 309.700 ;
        RECT 1.300 301.700 3.700 309.300 ;
        RECT 1.000 301.300 4.000 301.700 ;
        RECT 1.300 293.700 3.700 301.300 ;
        RECT 1.000 293.300 4.000 293.700 ;
        RECT 1.300 285.700 3.700 293.300 ;
        RECT 1.000 285.300 4.000 285.700 ;
        RECT 1.300 277.700 3.700 285.300 ;
        RECT 1.000 277.300 4.000 277.700 ;
        RECT 1.300 269.700 3.700 277.300 ;
        RECT 1.000 269.300 4.000 269.700 ;
        RECT 1.300 261.700 3.700 269.300 ;
        RECT 1.000 261.300 4.000 261.700 ;
        RECT 1.300 253.700 3.700 261.300 ;
        RECT 1.000 253.300 4.000 253.700 ;
        RECT 1.300 245.700 3.700 253.300 ;
        RECT 1.000 245.300 4.000 245.700 ;
        RECT 1.300 229.700 3.700 245.300 ;
        RECT 1.000 229.300 4.000 229.700 ;
        RECT 1.300 213.700 3.700 229.300 ;
        RECT 1.000 213.300 4.000 213.700 ;
        RECT 1.300 205.700 3.700 213.300 ;
        RECT 1.000 205.300 4.000 205.700 ;
        RECT 1.300 197.700 3.700 205.300 ;
        RECT 1.000 197.300 4.000 197.700 ;
        RECT 1.300 181.700 3.700 197.300 ;
        RECT 1.000 181.300 4.000 181.700 ;
        RECT 1.300 165.700 3.700 181.300 ;
        RECT 1.000 165.300 4.000 165.700 ;
        RECT 1.300 149.700 3.700 165.300 ;
        RECT 1.000 149.300 4.000 149.700 ;
        RECT 1.300 133.700 3.700 149.300 ;
        RECT 1.000 133.300 4.000 133.700 ;
        RECT 1.300 125.700 3.700 133.300 ;
        RECT 1.000 125.300 4.000 125.700 ;
        RECT 1.300 117.700 3.700 125.300 ;
        RECT 1.000 117.300 4.000 117.700 ;
        RECT 1.300 101.700 3.700 117.300 ;
        RECT 1.000 101.300 4.000 101.700 ;
        RECT 1.300 85.700 3.700 101.300 ;
        RECT 1.000 85.300 4.000 85.700 ;
        RECT 1.300 70.000 3.700 85.300 ;
      LAYER Metal4 ;
        RECT 1.300 341.700 3.700 348.390 ;
        RECT 1.000 341.300 4.000 341.700 ;
        RECT 1.300 333.700 3.700 341.300 ;
        RECT 1.000 333.300 4.000 333.700 ;
        RECT 1.300 325.700 3.700 333.300 ;
        RECT 1.000 325.300 4.000 325.700 ;
        RECT 1.300 317.700 3.700 325.300 ;
        RECT 1.000 317.300 4.000 317.700 ;
        RECT 1.300 309.700 3.700 317.300 ;
        RECT 1.000 309.300 4.000 309.700 ;
        RECT 1.300 301.700 3.700 309.300 ;
        RECT 1.000 301.300 4.000 301.700 ;
        RECT 1.300 293.700 3.700 301.300 ;
        RECT 1.000 293.300 4.000 293.700 ;
        RECT 1.300 285.700 3.700 293.300 ;
        RECT 1.000 285.300 4.000 285.700 ;
        RECT 1.300 277.700 3.700 285.300 ;
        RECT 1.000 277.300 4.000 277.700 ;
        RECT 1.300 269.700 3.700 277.300 ;
        RECT 1.000 269.300 4.000 269.700 ;
        RECT 1.300 261.700 3.700 269.300 ;
        RECT 1.000 261.300 4.000 261.700 ;
        RECT 1.300 253.700 3.700 261.300 ;
        RECT 1.000 253.300 4.000 253.700 ;
        RECT 1.300 245.700 3.700 253.300 ;
        RECT 1.000 245.300 4.000 245.700 ;
        RECT 1.300 229.700 3.700 245.300 ;
        RECT 1.000 229.300 4.000 229.700 ;
        RECT 1.300 213.700 3.700 229.300 ;
        RECT 1.000 213.300 4.000 213.700 ;
        RECT 1.300 205.700 3.700 213.300 ;
        RECT 1.000 205.300 4.000 205.700 ;
        RECT 1.300 197.700 3.700 205.300 ;
        RECT 1.000 197.300 4.000 197.700 ;
        RECT 1.300 181.700 3.700 197.300 ;
        RECT 1.000 181.300 4.000 181.700 ;
        RECT 1.300 165.700 3.700 181.300 ;
        RECT 1.000 165.300 4.000 165.700 ;
        RECT 1.300 149.700 3.700 165.300 ;
        RECT 1.000 149.300 4.000 149.700 ;
        RECT 1.300 133.700 3.700 149.300 ;
        RECT 1.000 133.300 4.000 133.700 ;
        RECT 1.300 125.700 3.700 133.300 ;
        RECT 1.000 125.300 4.000 125.700 ;
        RECT 1.300 117.700 3.700 125.300 ;
        RECT 1.000 117.300 4.000 117.700 ;
        RECT 1.300 101.700 3.700 117.300 ;
        RECT 1.000 101.300 4.000 101.700 ;
        RECT 1.300 85.700 3.700 101.300 ;
        RECT 1.000 85.300 4.000 85.700 ;
        RECT 1.300 70.000 3.700 85.300 ;
      LAYER Metal5 ;
        RECT 1.500 70.000 3.500 348.390 ;
  END
END gf180mcu_fd_io__fill5

#--------EOF---------

#--------EOF---------

MACRO gf180mcu_fd_io__fill10
  CLASS PAD SPACER ;
  FOREIGN gf180mcu_fd_io__fill10 ;
  ORIGIN 0.000 0.000 ;
  SIZE 10.000 BY 350.000 ;
  SYMMETRY X Y R90 ;
  PIN DVDD
    DIRECTION INOUT ;
    USE POWER ;
    PORT
      LAYER Metal5 ;
        RECT 9.000 134.000 10.000 149.000 ;
    END
    PORT
      LAYER Metal5 ;
        RECT 9.000 150.000 10.000 165.000 ;
    END
    PORT
      LAYER Metal5 ;
        RECT 9.000 166.000 10.000 181.000 ;
    END
    PORT
      LAYER Metal5 ;
        RECT 9.000 182.000 10.000 197.000 ;
    END
    PORT
      LAYER Metal5 ;
        RECT 9.000 214.000 10.000 229.000 ;
    END
    PORT
      LAYER Metal5 ;
        RECT 9.000 118.000 10.000 125.000 ;
    END
    PORT
      LAYER Metal5 ;
        RECT 9.000 206.000 10.000 213.000 ;
    END
    PORT
      LAYER Metal5 ;
        RECT 9.000 262.000 10.000 269.000 ;
    END
    PORT
      LAYER Metal5 ;
        RECT 9.000 270.000 10.000 277.000 ;
    END
    PORT
      LAYER Metal5 ;
        RECT 9.000 278.000 10.000 285.000 ;
    END
    PORT
      LAYER Metal5 ;
        RECT 9.000 294.000 10.000 301.000 ;
    END
    PORT
      LAYER Metal5 ;
        RECT 9.000 334.000 10.000 341.000 ;
    END
    PORT
      LAYER Metal4 ;
        RECT 9.000 134.000 10.000 149.000 ;
    END
    PORT
      LAYER Metal4 ;
        RECT 9.000 150.000 10.000 165.000 ;
    END
    PORT
      LAYER Metal4 ;
        RECT 9.000 166.000 10.000 181.000 ;
    END
    PORT
      LAYER Metal4 ;
        RECT 9.000 182.000 10.000 197.000 ;
    END
    PORT
      LAYER Metal4 ;
        RECT 9.000 214.000 10.000 229.000 ;
    END
    PORT
      LAYER Metal4 ;
        RECT 9.000 118.000 10.000 125.000 ;
    END
    PORT
      LAYER Metal4 ;
        RECT 9.000 206.000 10.000 213.000 ;
    END
    PORT
      LAYER Metal4 ;
        RECT 9.000 262.000 10.000 269.000 ;
    END
    PORT
      LAYER Metal4 ;
        RECT 9.000 270.000 10.000 277.000 ;
    END
    PORT
      LAYER Metal4 ;
        RECT 9.000 278.000 10.000 285.000 ;
    END
    PORT
      LAYER Metal4 ;
        RECT 9.000 294.000 10.000 301.000 ;
    END
    PORT
      LAYER Metal4 ;
        RECT 9.000 334.000 10.000 341.000 ;
    END
    PORT
      LAYER Metal3 ;
        RECT 9.000 134.000 10.000 149.000 ;
    END
    PORT
      LAYER Metal3 ;
        RECT 9.000 150.000 10.000 165.000 ;
    END
    PORT
      LAYER Metal3 ;
        RECT 9.000 166.000 10.000 181.000 ;
    END
    PORT
      LAYER Metal3 ;
        RECT 9.000 182.000 10.000 197.000 ;
    END
    PORT
      LAYER Metal3 ;
        RECT 9.000 214.000 10.000 229.000 ;
    END
    PORT
      LAYER Metal3 ;
        RECT 9.000 118.000 10.000 125.000 ;
    END
    PORT
      LAYER Metal3 ;
        RECT 9.000 206.000 10.000 213.000 ;
    END
    PORT
      LAYER Metal3 ;
        RECT 9.000 262.000 10.000 269.000 ;
    END
    PORT
      LAYER Metal3 ;
        RECT 9.000 270.000 10.000 277.000 ;
    END
    PORT
      LAYER Metal3 ;
        RECT 9.000 278.000 10.000 285.000 ;
    END
    PORT
      LAYER Metal3 ;
        RECT 9.000 294.000 10.000 301.000 ;
    END
    PORT
      LAYER Metal3 ;
        RECT 9.000 334.000 10.000 341.000 ;
    END
    PORT
      LAYER Metal3 ;
        RECT 0.000 334.000 1.000 341.000 ;
    END
    PORT
      LAYER Metal3 ;
        RECT 0.000 294.000 1.000 301.000 ;
    END
    PORT
      LAYER Metal3 ;
        RECT 0.000 278.000 1.000 285.000 ;
    END
    PORT
      LAYER Metal3 ;
        RECT 0.000 270.000 1.000 277.000 ;
    END
    PORT
      LAYER Metal3 ;
        RECT 0.000 262.000 1.000 269.000 ;
    END
    PORT
      LAYER Metal3 ;
        RECT 0.000 214.000 1.000 229.000 ;
    END
    PORT
      LAYER Metal3 ;
        RECT 0.000 206.000 1.000 213.000 ;
    END
    PORT
      LAYER Metal3 ;
        RECT 0.000 182.000 1.000 197.000 ;
    END
    PORT
      LAYER Metal3 ;
        RECT 0.000 166.000 1.000 181.000 ;
    END
    PORT
      LAYER Metal3 ;
        RECT 0.000 150.000 1.000 165.000 ;
    END
    PORT
      LAYER Metal3 ;
        RECT 0.000 134.000 1.000 149.000 ;
    END
    PORT
      LAYER Metal4 ;
        RECT 0.000 334.000 1.000 341.000 ;
    END
    PORT
      LAYER Metal4 ;
        RECT 0.000 294.000 1.000 301.000 ;
    END
    PORT
      LAYER Metal4 ;
        RECT 0.000 278.000 1.000 285.000 ;
    END
    PORT
      LAYER Metal4 ;
        RECT 0.000 270.000 1.000 277.000 ;
    END
    PORT
      LAYER Metal4 ;
        RECT 0.000 262.000 1.000 269.000 ;
    END
    PORT
      LAYER Metal4 ;
        RECT 0.000 214.000 1.000 229.000 ;
    END
    PORT
      LAYER Metal4 ;
        RECT 0.000 206.000 1.000 213.000 ;
    END
    PORT
      LAYER Metal4 ;
        RECT 0.000 182.000 1.000 197.000 ;
    END
    PORT
      LAYER Metal4 ;
        RECT 0.000 166.000 1.000 181.000 ;
    END
    PORT
      LAYER Metal4 ;
        RECT 0.000 150.000 1.000 165.000 ;
    END
    PORT
      LAYER Metal4 ;
        RECT 0.000 134.000 1.000 149.000 ;
    END
    PORT
      LAYER Metal5 ;
        RECT 0.000 334.000 1.000 341.000 ;
    END
    PORT
      LAYER Metal5 ;
        RECT 0.000 294.000 1.000 301.000 ;
    END
    PORT
      LAYER Metal5 ;
        RECT 0.000 278.000 1.000 285.000 ;
    END
    PORT
      LAYER Metal5 ;
        RECT 0.000 270.000 1.000 277.000 ;
    END
    PORT
      LAYER Metal5 ;
        RECT 0.000 262.000 1.000 269.000 ;
    END
    PORT
      LAYER Metal5 ;
        RECT 0.000 214.000 1.000 229.000 ;
    END
    PORT
      LAYER Metal5 ;
        RECT 0.000 206.000 1.000 213.000 ;
    END
    PORT
      LAYER Metal5 ;
        RECT 0.000 182.000 1.000 197.000 ;
    END
    PORT
      LAYER Metal5 ;
        RECT 0.000 166.000 1.000 181.000 ;
    END
    PORT
      LAYER Metal5 ;
        RECT 0.000 150.000 1.000 165.000 ;
    END
    PORT
      LAYER Metal5 ;
        RECT 0.000 134.000 1.000 149.000 ;
    END
    PORT
      LAYER Metal5 ;
        RECT 0.000 118.000 1.000 125.000 ;
    END
    PORT
      LAYER Metal4 ;
        RECT 0.000 118.000 1.000 125.000 ;
    END
    PORT
      LAYER Metal3 ;
        RECT 0.000 118.000 1.000 125.000 ;
    END
  END DVDD
  PIN DVSS
    DIRECTION INOUT ;
    USE GROUND ;
    PORT
      LAYER Metal5 ;
        RECT 9.000 70.000 10.000 85.000 ;
    END
    PORT
      LAYER Metal5 ;
        RECT 9.000 86.000 10.000 101.000 ;
    END
    PORT
      LAYER Metal5 ;
        RECT 9.000 102.000 10.000 117.000 ;
    END
    PORT
      LAYER Metal5 ;
        RECT 9.000 230.000 10.000 245.000 ;
    END
    PORT
      LAYER Metal5 ;
        RECT 9.000 126.000 10.000 133.000 ;
    END
    PORT
      LAYER Metal5 ;
        RECT 9.000 198.000 10.000 205.000 ;
    END
    PORT
      LAYER Metal5 ;
        RECT 9.000 286.000 10.000 293.000 ;
    END
    PORT
      LAYER Metal5 ;
        RECT 9.000 302.000 10.000 309.000 ;
    END
    PORT
      LAYER Metal5 ;
        RECT 9.000 326.000 10.000 333.000 ;
    END
    PORT
      LAYER Metal5 ;
        RECT 9.000 342.000 10.000 348.390 ;
    END
    PORT
      LAYER Metal4 ;
        RECT 9.000 70.000 10.000 85.000 ;
    END
    PORT
      LAYER Metal4 ;
        RECT 9.000 86.000 10.000 101.000 ;
    END
    PORT
      LAYER Metal4 ;
        RECT 9.000 102.000 10.000 117.000 ;
    END
    PORT
      LAYER Metal4 ;
        RECT 9.000 230.000 10.000 245.000 ;
    END
    PORT
      LAYER Metal4 ;
        RECT 9.000 126.000 10.000 133.000 ;
    END
    PORT
      LAYER Metal4 ;
        RECT 9.000 198.000 10.000 205.000 ;
    END
    PORT
      LAYER Metal4 ;
        RECT 9.000 286.000 10.000 293.000 ;
    END
    PORT
      LAYER Metal4 ;
        RECT 9.000 302.000 10.000 309.000 ;
    END
    PORT
      LAYER Metal4 ;
        RECT 9.000 326.000 10.000 333.000 ;
    END
    PORT
      LAYER Metal4 ;
        RECT 9.000 342.000 10.000 348.390 ;
    END
    PORT
      LAYER Metal3 ;
        RECT 9.000 70.000 10.000 85.000 ;
    END
    PORT
      LAYER Metal3 ;
        RECT 9.000 86.000 10.000 101.000 ;
    END
    PORT
      LAYER Metal3 ;
        RECT 9.000 102.000 10.000 117.000 ;
    END
    PORT
      LAYER Metal3 ;
        RECT 9.000 230.000 10.000 245.000 ;
    END
    PORT
      LAYER Metal3 ;
        RECT 9.000 126.000 10.000 133.000 ;
    END
    PORT
      LAYER Metal3 ;
        RECT 9.000 198.000 10.000 205.000 ;
    END
    PORT
      LAYER Metal3 ;
        RECT 9.000 286.000 10.000 293.000 ;
    END
    PORT
      LAYER Metal3 ;
        RECT 9.000 302.000 10.000 309.000 ;
    END
    PORT
      LAYER Metal3 ;
        RECT 9.000 326.000 10.000 333.000 ;
    END
    PORT
      LAYER Metal3 ;
        RECT 9.000 342.000 10.000 348.390 ;
    END
    PORT
      LAYER Metal3 ;
        RECT 0.000 342.000 1.000 348.390 ;
    END
    PORT
      LAYER Metal3 ;
        RECT 0.000 326.000 1.000 333.000 ;
    END
    PORT
      LAYER Metal3 ;
        RECT 0.000 302.000 1.000 309.000 ;
    END
    PORT
      LAYER Metal3 ;
        RECT 0.000 286.000 1.000 293.000 ;
    END
    PORT
      LAYER Metal3 ;
        RECT 0.000 230.000 1.000 245.000 ;
    END
    PORT
      LAYER Metal3 ;
        RECT 0.000 198.000 1.000 205.000 ;
    END
    PORT
      LAYER Metal3 ;
        RECT 0.000 126.000 1.000 133.000 ;
    END
    PORT
      LAYER Metal3 ;
        RECT 0.000 102.000 1.000 117.000 ;
    END
    PORT
      LAYER Metal3 ;
        RECT 0.000 86.000 1.000 101.000 ;
    END
    PORT
      LAYER Metal4 ;
        RECT 0.000 342.000 1.000 348.390 ;
    END
    PORT
      LAYER Metal4 ;
        RECT 0.000 326.000 1.000 333.000 ;
    END
    PORT
      LAYER Metal4 ;
        RECT 0.000 302.000 1.000 309.000 ;
    END
    PORT
      LAYER Metal4 ;
        RECT 0.000 286.000 1.000 293.000 ;
    END
    PORT
      LAYER Metal4 ;
        RECT 0.000 230.000 1.000 245.000 ;
    END
    PORT
      LAYER Metal4 ;
        RECT 0.000 198.000 1.000 205.000 ;
    END
    PORT
      LAYER Metal4 ;
        RECT 0.000 126.000 1.000 133.000 ;
    END
    PORT
      LAYER Metal4 ;
        RECT 0.000 102.000 1.000 117.000 ;
    END
    PORT
      LAYER Metal4 ;
        RECT 0.000 86.000 1.000 101.000 ;
    END
    PORT
      LAYER Metal5 ;
        RECT 0.000 342.000 1.000 348.390 ;
    END
    PORT
      LAYER Metal5 ;
        RECT 0.000 326.000 1.000 333.000 ;
    END
    PORT
      LAYER Metal5 ;
        RECT 0.000 302.000 1.000 309.000 ;
    END
    PORT
      LAYER Metal5 ;
        RECT 0.000 286.000 1.000 293.000 ;
    END
    PORT
      LAYER Metal5 ;
        RECT 0.000 230.000 1.000 245.000 ;
    END
    PORT
      LAYER Metal5 ;
        RECT 0.000 198.000 1.000 205.000 ;
    END
    PORT
      LAYER Metal5 ;
        RECT 0.000 126.000 1.000 133.000 ;
    END
    PORT
      LAYER Metal5 ;
        RECT 0.000 102.000 1.000 117.000 ;
    END
    PORT
      LAYER Metal5 ;
        RECT 0.000 86.000 1.000 101.000 ;
    END
    PORT
      LAYER Metal5 ;
        RECT 0.000 70.000 1.000 85.000 ;
    END
    PORT
      LAYER Metal4 ;
        RECT 0.000 70.000 1.000 85.000 ;
    END
    PORT
      LAYER Metal3 ;
        RECT 0.000 70.000 1.000 85.000 ;
    END
  END DVSS
  PIN VDD
    DIRECTION INOUT ;
    USE POWER ;
    PORT
      LAYER Metal5 ;
        RECT 9.000 254.000 10.000 261.000 ;
    END
    PORT
      LAYER Metal5 ;
        RECT 9.000 310.000 10.000 317.000 ;
    END
    PORT
      LAYER Metal4 ;
        RECT 9.000 254.000 10.000 261.000 ;
    END
    PORT
      LAYER Metal4 ;
        RECT 9.000 310.000 10.000 317.000 ;
    END
    PORT
      LAYER Metal3 ;
        RECT 9.000 254.000 10.000 261.000 ;
    END
    PORT
      LAYER Metal3 ;
        RECT 9.000 310.000 10.000 317.000 ;
    END
    PORT
      LAYER Metal3 ;
        RECT 0.000 310.000 1.000 317.000 ;
    END
    PORT
      LAYER Metal4 ;
        RECT 0.000 310.000 1.000 317.000 ;
    END
    PORT
      LAYER Metal5 ;
        RECT 0.000 310.000 1.000 317.000 ;
    END
    PORT
      LAYER Metal5 ;
        RECT 0.000 254.000 1.000 261.000 ;
    END
    PORT
      LAYER Metal4 ;
        RECT 0.000 254.000 1.000 261.000 ;
    END
    PORT
      LAYER Metal3 ;
        RECT 0.000 254.000 1.000 261.000 ;
    END
  END VDD
  PIN VSS
    DIRECTION INOUT ;
    USE GROUND ;
    PORT
      LAYER Metal5 ;
        RECT 9.000 246.000 10.000 253.000 ;
    END
    PORT
      LAYER Metal5 ;
        RECT 9.000 318.000 10.000 325.000 ;
    END
    PORT
      LAYER Metal4 ;
        RECT 9.000 246.000 10.000 253.000 ;
    END
    PORT
      LAYER Metal4 ;
        RECT 9.000 318.000 10.000 325.000 ;
    END
    PORT
      LAYER Metal3 ;
        RECT 9.000 246.000 10.000 253.000 ;
    END
    PORT
      LAYER Metal3 ;
        RECT 9.000 318.000 10.000 325.000 ;
    END
    PORT
      LAYER Metal3 ;
        RECT 0.000 318.000 1.000 325.000 ;
    END
    PORT
      LAYER Metal4 ;
        RECT 0.000 318.000 1.000 325.000 ;
    END
    PORT
      LAYER Metal5 ;
        RECT 0.000 318.000 1.000 325.000 ;
    END
    PORT
      LAYER Metal5 ;
        RECT 0.000 246.000 1.000 253.000 ;
    END
    PORT
      LAYER Metal4 ;
        RECT 0.000 246.000 1.000 253.000 ;
    END
    PORT
      LAYER Metal3 ;
        RECT 0.000 246.000 1.000 253.000 ;
    END
  END VSS
  OBS
      LAYER Metal1 ;
        RECT -0.160 65.540 10.160 349.785 ;
      LAYER Metal2 ;
        RECT 0.000 68.055 10.000 348.100 ;
      LAYER Metal3 ;
        RECT 1.300 341.700 8.700 348.390 ;
        RECT 1.000 341.300 9.000 341.700 ;
        RECT 1.300 333.700 8.700 341.300 ;
        RECT 1.000 333.300 9.000 333.700 ;
        RECT 1.300 325.700 8.700 333.300 ;
        RECT 1.000 325.300 9.000 325.700 ;
        RECT 1.300 317.700 8.700 325.300 ;
        RECT 1.000 317.300 9.000 317.700 ;
        RECT 1.300 309.700 8.700 317.300 ;
        RECT 1.000 309.300 9.000 309.700 ;
        RECT 1.300 301.700 8.700 309.300 ;
        RECT 1.000 301.300 9.000 301.700 ;
        RECT 1.300 293.700 8.700 301.300 ;
        RECT 1.000 293.300 9.000 293.700 ;
        RECT 1.300 285.700 8.700 293.300 ;
        RECT 1.000 285.300 9.000 285.700 ;
        RECT 1.300 277.700 8.700 285.300 ;
        RECT 1.000 277.300 9.000 277.700 ;
        RECT 1.300 269.700 8.700 277.300 ;
        RECT 1.000 269.300 9.000 269.700 ;
        RECT 1.300 261.700 8.700 269.300 ;
        RECT 1.000 261.300 9.000 261.700 ;
        RECT 1.300 253.700 8.700 261.300 ;
        RECT 1.000 253.300 9.000 253.700 ;
        RECT 1.300 245.700 8.700 253.300 ;
        RECT 1.000 245.300 9.000 245.700 ;
        RECT 1.300 229.700 8.700 245.300 ;
        RECT 1.000 229.300 9.000 229.700 ;
        RECT 1.300 213.700 8.700 229.300 ;
        RECT 1.000 213.300 9.000 213.700 ;
        RECT 1.300 205.700 8.700 213.300 ;
        RECT 1.000 205.300 9.000 205.700 ;
        RECT 1.300 197.700 8.700 205.300 ;
        RECT 1.000 197.300 9.000 197.700 ;
        RECT 1.300 181.700 8.700 197.300 ;
        RECT 1.000 181.300 9.000 181.700 ;
        RECT 1.300 165.700 8.700 181.300 ;
        RECT 1.000 165.300 9.000 165.700 ;
        RECT 1.300 149.700 8.700 165.300 ;
        RECT 1.000 149.300 9.000 149.700 ;
        RECT 1.300 133.700 8.700 149.300 ;
        RECT 1.000 133.300 9.000 133.700 ;
        RECT 1.300 125.700 8.700 133.300 ;
        RECT 1.000 125.300 9.000 125.700 ;
        RECT 1.300 117.700 8.700 125.300 ;
        RECT 1.000 117.300 9.000 117.700 ;
        RECT 1.300 101.700 8.700 117.300 ;
        RECT 1.000 101.300 9.000 101.700 ;
        RECT 1.300 85.700 8.700 101.300 ;
        RECT 1.000 85.300 9.000 85.700 ;
        RECT 1.300 70.000 8.700 85.300 ;
      LAYER Metal4 ;
        RECT 1.300 341.700 8.700 348.390 ;
        RECT 1.000 341.300 9.000 341.700 ;
        RECT 1.300 333.700 8.700 341.300 ;
        RECT 1.000 333.300 9.000 333.700 ;
        RECT 1.300 325.700 8.700 333.300 ;
        RECT 1.000 325.300 9.000 325.700 ;
        RECT 1.300 317.700 8.700 325.300 ;
        RECT 1.000 317.300 9.000 317.700 ;
        RECT 1.300 309.700 8.700 317.300 ;
        RECT 1.000 309.300 9.000 309.700 ;
        RECT 1.300 301.700 8.700 309.300 ;
        RECT 1.000 301.300 9.000 301.700 ;
        RECT 1.300 293.700 8.700 301.300 ;
        RECT 1.000 293.300 9.000 293.700 ;
        RECT 1.300 285.700 8.700 293.300 ;
        RECT 1.000 285.300 9.000 285.700 ;
        RECT 1.300 277.700 8.700 285.300 ;
        RECT 1.000 277.300 9.000 277.700 ;
        RECT 1.300 269.700 8.700 277.300 ;
        RECT 1.000 269.300 9.000 269.700 ;
        RECT 1.300 261.700 8.700 269.300 ;
        RECT 1.000 261.300 9.000 261.700 ;
        RECT 1.300 253.700 8.700 261.300 ;
        RECT 1.000 253.300 9.000 253.700 ;
        RECT 1.300 245.700 8.700 253.300 ;
        RECT 1.000 245.300 9.000 245.700 ;
        RECT 1.300 229.700 8.700 245.300 ;
        RECT 1.000 229.300 9.000 229.700 ;
        RECT 1.300 213.700 8.700 229.300 ;
        RECT 1.000 213.300 9.000 213.700 ;
        RECT 1.300 205.700 8.700 213.300 ;
        RECT 1.000 205.300 9.000 205.700 ;
        RECT 1.300 197.700 8.700 205.300 ;
        RECT 1.000 197.300 9.000 197.700 ;
        RECT 1.300 181.700 8.700 197.300 ;
        RECT 1.000 181.300 9.000 181.700 ;
        RECT 1.300 165.700 8.700 181.300 ;
        RECT 1.000 165.300 9.000 165.700 ;
        RECT 1.300 149.700 8.700 165.300 ;
        RECT 1.000 149.300 9.000 149.700 ;
        RECT 1.300 133.700 8.700 149.300 ;
        RECT 1.000 133.300 9.000 133.700 ;
        RECT 1.300 125.700 8.700 133.300 ;
        RECT 1.000 125.300 9.000 125.700 ;
        RECT 1.300 117.700 8.700 125.300 ;
        RECT 1.000 117.300 9.000 117.700 ;
        RECT 1.300 101.700 8.700 117.300 ;
        RECT 1.000 101.300 9.000 101.700 ;
        RECT 1.300 85.700 8.700 101.300 ;
        RECT 1.000 85.300 9.000 85.700 ;
        RECT 1.300 70.000 8.700 85.300 ;
      LAYER Metal5 ;
        RECT 1.500 70.000 8.500 348.390 ;
  END
END gf180mcu_fd_io__fill10

#--------EOF---------

#--------EOF---------

MACRO gf180mcu_fd_io__fillnc
  CLASS PAD SPACER ;
  FOREIGN gf180mcu_fd_io__fillnc ;
  ORIGIN 0.000 0.000 ;
  SIZE 0.100 BY 350.000 ;
  SYMMETRY X Y R90 ;
  PIN DVDD
    DIRECTION INOUT ;
    USE POWER ;
    PORT
      LAYER Metal3 ;
        RECT 0.000 334.000 0.100 341.000 ;
    END
    PORT
      LAYER Metal3 ;
        RECT 0.000 294.000 0.100 301.000 ;
    END
    PORT
      LAYER Metal3 ;
        RECT 0.000 278.000 0.100 285.000 ;
    END
    PORT
      LAYER Metal3 ;
        RECT 0.000 270.000 0.100 277.000 ;
    END
    PORT
      LAYER Metal3 ;
        RECT 0.000 262.000 0.100 269.000 ;
    END
    PORT
      LAYER Metal3 ;
        RECT 0.000 214.000 0.100 229.000 ;
    END
    PORT
      LAYER Metal3 ;
        RECT 0.000 206.000 0.100 213.000 ;
    END
    PORT
      LAYER Metal3 ;
        RECT 0.000 182.000 0.100 197.000 ;
    END
    PORT
      LAYER Metal3 ;
        RECT 0.000 166.000 0.100 181.000 ;
    END
    PORT
      LAYER Metal3 ;
        RECT 0.000 150.000 0.100 165.000 ;
    END
    PORT
      LAYER Metal3 ;
        RECT 0.000 134.000 0.100 149.000 ;
    END
    PORT
      LAYER Metal4 ;
        RECT 0.000 334.000 0.100 341.000 ;
    END
    PORT
      LAYER Metal4 ;
        RECT 0.000 294.000 0.100 301.000 ;
    END
    PORT
      LAYER Metal4 ;
        RECT 0.000 278.000 0.100 285.000 ;
    END
    PORT
      LAYER Metal4 ;
        RECT 0.000 270.000 0.100 277.000 ;
    END
    PORT
      LAYER Metal4 ;
        RECT 0.000 262.000 0.100 269.000 ;
    END
    PORT
      LAYER Metal4 ;
        RECT 0.000 214.000 0.100 229.000 ;
    END
    PORT
      LAYER Metal4 ;
        RECT 0.000 206.000 0.100 213.000 ;
    END
    PORT
      LAYER Metal4 ;
        RECT 0.000 182.000 0.100 197.000 ;
    END
    PORT
      LAYER Metal4 ;
        RECT 0.000 166.000 0.100 181.000 ;
    END
    PORT
      LAYER Metal4 ;
        RECT 0.000 150.000 0.100 165.000 ;
    END
    PORT
      LAYER Metal4 ;
        RECT 0.000 134.000 0.100 149.000 ;
    END
    PORT
      LAYER Metal5 ;
        RECT 0.000 334.000 0.100 341.000 ;
    END
    PORT
      LAYER Metal5 ;
        RECT 0.000 294.000 0.100 301.000 ;
    END
    PORT
      LAYER Metal5 ;
        RECT 0.000 278.000 0.100 285.000 ;
    END
    PORT
      LAYER Metal5 ;
        RECT 0.000 270.000 0.100 277.000 ;
    END
    PORT
      LAYER Metal5 ;
        RECT 0.000 262.000 0.100 269.000 ;
    END
    PORT
      LAYER Metal5 ;
        RECT 0.000 214.000 0.100 229.000 ;
    END
    PORT
      LAYER Metal5 ;
        RECT 0.000 206.000 0.100 213.000 ;
    END
    PORT
      LAYER Metal5 ;
        RECT 0.000 182.000 0.100 197.000 ;
    END
    PORT
      LAYER Metal5 ;
        RECT 0.000 166.000 0.100 181.000 ;
    END
    PORT
      LAYER Metal5 ;
        RECT 0.000 150.000 0.100 165.000 ;
    END
    PORT
      LAYER Metal5 ;
        RECT 0.000 134.000 0.100 149.000 ;
    END
    PORT
      LAYER Metal5 ;
        RECT 0.000 118.000 0.100 125.000 ;
    END
    PORT
      LAYER Metal4 ;
        RECT 0.000 118.000 0.100 125.000 ;
    END
    PORT
      LAYER Metal3 ;
        RECT 0.000 118.000 0.100 125.000 ;
    END
  END DVDD
  PIN DVSS
    DIRECTION INOUT ;
    USE GROUND ;
    PORT
      LAYER Metal3 ;
        RECT 0.000 342.000 0.100 348.390 ;
    END
    PORT
      LAYER Metal3 ;
        RECT 0.000 326.000 0.100 333.000 ;
    END
    PORT
      LAYER Metal3 ;
        RECT 0.000 302.000 0.100 309.000 ;
    END
    PORT
      LAYER Metal3 ;
        RECT 0.000 286.000 0.100 293.000 ;
    END
    PORT
      LAYER Metal3 ;
        RECT 0.000 230.000 0.100 245.000 ;
    END
    PORT
      LAYER Metal3 ;
        RECT 0.000 198.000 0.100 205.000 ;
    END
    PORT
      LAYER Metal3 ;
        RECT 0.000 126.000 0.100 133.000 ;
    END
    PORT
      LAYER Metal3 ;
        RECT 0.000 102.000 0.100 117.000 ;
    END
    PORT
      LAYER Metal3 ;
        RECT 0.000 86.000 0.100 101.000 ;
    END
    PORT
      LAYER Metal4 ;
        RECT 0.000 342.000 0.100 348.390 ;
    END
    PORT
      LAYER Metal4 ;
        RECT 0.000 326.000 0.100 333.000 ;
    END
    PORT
      LAYER Metal4 ;
        RECT 0.000 302.000 0.100 309.000 ;
    END
    PORT
      LAYER Metal4 ;
        RECT 0.000 286.000 0.100 293.000 ;
    END
    PORT
      LAYER Metal4 ;
        RECT 0.000 230.000 0.100 245.000 ;
    END
    PORT
      LAYER Metal4 ;
        RECT 0.000 198.000 0.100 205.000 ;
    END
    PORT
      LAYER Metal4 ;
        RECT 0.000 126.000 0.100 133.000 ;
    END
    PORT
      LAYER Metal4 ;
        RECT 0.000 102.000 0.100 117.000 ;
    END
    PORT
      LAYER Metal4 ;
        RECT 0.000 86.000 0.100 101.000 ;
    END
    PORT
      LAYER Metal5 ;
        RECT 0.000 342.000 0.100 348.390 ;
    END
    PORT
      LAYER Metal5 ;
        RECT 0.000 326.000 0.100 333.000 ;
    END
    PORT
      LAYER Metal5 ;
        RECT 0.000 302.000 0.100 309.000 ;
    END
    PORT
      LAYER Metal5 ;
        RECT 0.000 286.000 0.100 293.000 ;
    END
    PORT
      LAYER Metal5 ;
        RECT 0.000 230.000 0.100 245.000 ;
    END
    PORT
      LAYER Metal5 ;
        RECT 0.000 198.000 0.100 205.000 ;
    END
    PORT
      LAYER Metal5 ;
        RECT 0.000 126.000 0.100 133.000 ;
    END
    PORT
      LAYER Metal5 ;
        RECT 0.000 102.000 0.100 117.000 ;
    END
    PORT
      LAYER Metal5 ;
        RECT 0.000 86.000 0.100 101.000 ;
    END
    PORT
      LAYER Metal5 ;
        RECT 0.000 70.000 0.100 85.000 ;
    END
    PORT
      LAYER Metal4 ;
        RECT 0.000 70.000 0.100 85.000 ;
    END
    PORT
      LAYER Metal3 ;
        RECT 0.000 70.000 0.100 85.000 ;
    END
  END DVSS
  PIN VDD
    DIRECTION INOUT ;
    USE POWER ;
    PORT
      LAYER Metal3 ;
        RECT 0.000 310.000 0.100 317.000 ;
    END
    PORT
      LAYER Metal4 ;
        RECT 0.000 310.000 0.100 317.000 ;
    END
    PORT
      LAYER Metal5 ;
        RECT 0.000 310.000 0.100 317.000 ;
    END
    PORT
      LAYER Metal5 ;
        RECT 0.000 254.000 0.100 261.000 ;
    END
    PORT
      LAYER Metal4 ;
        RECT 0.000 254.000 0.100 261.000 ;
    END
    PORT
      LAYER Metal3 ;
        RECT 0.000 254.000 0.100 261.000 ;
    END
  END VDD
  PIN VSS
    DIRECTION INOUT ;
    USE GROUND ;
    PORT
      LAYER Metal3 ;
        RECT 0.000 318.000 0.100 325.000 ;
    END
    PORT
      LAYER Metal4 ;
        RECT 0.000 318.000 0.100 325.000 ;
    END
    PORT
      LAYER Metal5 ;
        RECT 0.000 318.000 0.100 325.000 ;
    END
    PORT
      LAYER Metal5 ;
        RECT 0.000 246.000 0.100 253.000 ;
    END
    PORT
      LAYER Metal4 ;
        RECT 0.000 246.000 0.100 253.000 ;
    END
    PORT
      LAYER Metal3 ;
        RECT 0.000 246.000 0.100 253.000 ;
    END
  END VSS
  OBS
      LAYER Metal1 ;
        RECT -0.160 65.540 0.260 349.785 ;
      LAYER Metal2 ;
        RECT 0.000 246.000 0.100 325.000 ;
  END
END gf180mcu_fd_io__fillnc

#--------EOF---------

#--------EOF---------

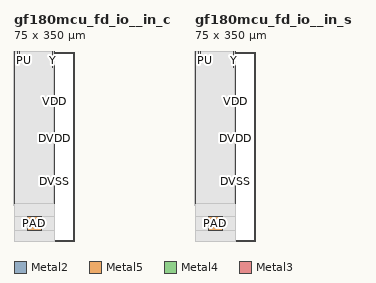
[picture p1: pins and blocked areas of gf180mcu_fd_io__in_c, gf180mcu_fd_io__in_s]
MACRO gf180mcu_fd_io__in_c
  CLASS PAD INPUT ;
  FOREIGN gf180mcu_fd_io__in_c ;
  ORIGIN 0.000 0.000 ;
  SIZE 75.000 BY 350.000 ;
  SYMMETRY X Y R90 ;
  PIN DVDD
    DIRECTION INOUT ;
    USE POWER ;
    PORT
      LAYER Metal5 ;
        RECT 74.000 118.000 75.000 125.000 ;
    END
    PORT
      LAYER Metal5 ;
        RECT 74.000 182.000 75.000 197.000 ;
    END
    PORT
      LAYER Metal5 ;
        RECT 74.000 166.000 75.000 181.000 ;
    END
    PORT
      LAYER Metal5 ;
        RECT 74.000 150.000 75.000 165.000 ;
    END
    PORT
      LAYER Metal5 ;
        RECT 74.000 134.000 75.000 149.000 ;
    END
    PORT
      LAYER Metal5 ;
        RECT 74.000 214.000 75.000 229.000 ;
    END
    PORT
      LAYER Metal5 ;
        RECT 74.000 206.000 75.000 213.000 ;
    END
    PORT
      LAYER Metal5 ;
        RECT 74.000 278.000 75.000 285.000 ;
    END
    PORT
      LAYER Metal5 ;
        RECT 74.000 270.000 75.000 277.000 ;
    END
    PORT
      LAYER Metal5 ;
        RECT 74.000 262.000 75.000 269.000 ;
    END
    PORT
      LAYER Metal5 ;
        RECT 74.000 294.000 75.000 301.000 ;
    END
    PORT
      LAYER Metal5 ;
        RECT 74.000 334.000 75.000 341.000 ;
    END
    PORT
      LAYER Metal4 ;
        RECT 74.000 118.000 75.000 125.000 ;
    END
    PORT
      LAYER Metal4 ;
        RECT 74.000 182.000 75.000 197.000 ;
    END
    PORT
      LAYER Metal4 ;
        RECT 74.000 166.000 75.000 181.000 ;
    END
    PORT
      LAYER Metal4 ;
        RECT 74.000 150.000 75.000 165.000 ;
    END
    PORT
      LAYER Metal4 ;
        RECT 74.000 134.000 75.000 149.000 ;
    END
    PORT
      LAYER Metal4 ;
        RECT 74.000 214.000 75.000 229.000 ;
    END
    PORT
      LAYER Metal4 ;
        RECT 74.000 206.000 75.000 213.000 ;
    END
    PORT
      LAYER Metal4 ;
        RECT 74.000 278.000 75.000 285.000 ;
    END
    PORT
      LAYER Metal4 ;
        RECT 74.000 270.000 75.000 277.000 ;
    END
    PORT
      LAYER Metal4 ;
        RECT 74.000 262.000 75.000 269.000 ;
    END
    PORT
      LAYER Metal4 ;
        RECT 74.000 294.000 75.000 301.000 ;
    END
    PORT
      LAYER Metal4 ;
        RECT 74.000 334.000 75.000 341.000 ;
    END
    PORT
      LAYER Metal3 ;
        RECT 74.000 118.000 75.000 125.000 ;
    END
    PORT
      LAYER Metal3 ;
        RECT 74.000 182.000 75.000 197.000 ;
    END
    PORT
      LAYER Metal3 ;
        RECT 74.000 166.000 75.000 181.000 ;
    END
    PORT
      LAYER Metal3 ;
        RECT 74.000 150.000 75.000 165.000 ;
    END
    PORT
      LAYER Metal3 ;
        RECT 74.000 134.000 75.000 149.000 ;
    END
    PORT
      LAYER Metal3 ;
        RECT 74.000 214.000 75.000 229.000 ;
    END
    PORT
      LAYER Metal3 ;
        RECT 74.000 206.000 75.000 213.000 ;
    END
    PORT
      LAYER Metal3 ;
        RECT 74.000 278.000 75.000 285.000 ;
    END
    PORT
      LAYER Metal3 ;
        RECT 74.000 270.000 75.000 277.000 ;
    END
    PORT
      LAYER Metal3 ;
        RECT 74.000 262.000 75.000 269.000 ;
    END
    PORT
      LAYER Metal3 ;
        RECT 74.000 294.000 75.000 301.000 ;
    END
    PORT
      LAYER Metal3 ;
        RECT 74.000 334.000 75.000 341.000 ;
    END
    PORT
      LAYER Metal3 ;
        RECT 0.000 334.000 1.000 341.000 ;
    END
    PORT
      LAYER Metal3 ;
        RECT 0.000 294.000 1.000 301.000 ;
    END
    PORT
      LAYER Metal3 ;
        RECT 0.000 262.000 1.000 269.000 ;
    END
    PORT
      LAYER Metal3 ;
        RECT 0.000 270.000 1.000 277.000 ;
    END
    PORT
      LAYER Metal3 ;
        RECT 0.000 278.000 1.000 285.000 ;
    END
    PORT
      LAYER Metal3 ;
        RECT 0.000 206.000 1.000 213.000 ;
    END
    PORT
      LAYER Metal3 ;
        RECT 0.000 214.000 1.000 229.000 ;
    END
    PORT
      LAYER Metal3 ;
        RECT 0.000 134.000 1.000 149.000 ;
    END
    PORT
      LAYER Metal3 ;
        RECT 0.000 150.000 1.000 165.000 ;
    END
    PORT
      LAYER Metal3 ;
        RECT 0.000 166.000 1.000 181.000 ;
    END
    PORT
      LAYER Metal3 ;
        RECT 0.000 182.000 1.000 197.000 ;
    END
    PORT
      LAYER Metal4 ;
        RECT 0.000 334.000 1.000 341.000 ;
    END
    PORT
      LAYER Metal4 ;
        RECT 0.000 294.000 1.000 301.000 ;
    END
    PORT
      LAYER Metal4 ;
        RECT 0.000 262.000 1.000 269.000 ;
    END
    PORT
      LAYER Metal4 ;
        RECT 0.000 270.000 1.000 277.000 ;
    END
    PORT
      LAYER Metal4 ;
        RECT 0.000 278.000 1.000 285.000 ;
    END
    PORT
      LAYER Metal4 ;
        RECT 0.000 206.000 1.000 213.000 ;
    END
    PORT
      LAYER Metal4 ;
        RECT 0.000 214.000 1.000 229.000 ;
    END
    PORT
      LAYER Metal4 ;
        RECT 0.000 134.000 1.000 149.000 ;
    END
    PORT
      LAYER Metal4 ;
        RECT 0.000 150.000 1.000 165.000 ;
    END
    PORT
      LAYER Metal4 ;
        RECT 0.000 166.000 1.000 181.000 ;
    END
    PORT
      LAYER Metal4 ;
        RECT 0.000 182.000 1.000 197.000 ;
    END
    PORT
      LAYER Metal5 ;
        RECT 0.000 334.000 1.000 341.000 ;
    END
    PORT
      LAYER Metal5 ;
        RECT 0.000 294.000 1.000 301.000 ;
    END
    PORT
      LAYER Metal5 ;
        RECT 0.000 262.000 1.000 269.000 ;
    END
    PORT
      LAYER Metal5 ;
        RECT 0.000 270.000 1.000 277.000 ;
    END
    PORT
      LAYER Metal5 ;
        RECT 0.000 278.000 1.000 285.000 ;
    END
    PORT
      LAYER Metal5 ;
        RECT 0.000 206.000 1.000 213.000 ;
    END
    PORT
      LAYER Metal5 ;
        RECT 0.000 214.000 1.000 229.000 ;
    END
    PORT
      LAYER Metal5 ;
        RECT 0.000 134.000 1.000 149.000 ;
    END
    PORT
      LAYER Metal5 ;
        RECT 0.000 150.000 1.000 165.000 ;
    END
    PORT
      LAYER Metal5 ;
        RECT 0.000 166.000 1.000 181.000 ;
    END
    PORT
      LAYER Metal5 ;
        RECT 0.000 182.000 1.000 197.000 ;
    END
    PORT
      LAYER Metal5 ;
        RECT 0.000 118.000 1.000 125.000 ;
    END
    PORT
      LAYER Metal4 ;
        RECT 0.000 118.000 1.000 125.000 ;
    END
    PORT
      LAYER Metal3 ;
        RECT 0.000 118.000 1.000 125.000 ;
    END
  END DVDD
  PIN DVSS
    DIRECTION INOUT ;
    USE GROUND ;
    PORT
      LAYER Metal5 ;
        RECT 74.000 102.000 75.000 117.000 ;
    END
    PORT
      LAYER Metal5 ;
        RECT 74.000 86.000 75.000 101.000 ;
    END
    PORT
      LAYER Metal5 ;
        RECT 74.000 70.000 75.000 85.000 ;
    END
    PORT
      LAYER Metal5 ;
        RECT 74.000 126.000 75.000 133.000 ;
    END
    PORT
      LAYER Metal5 ;
        RECT 74.000 198.000 75.000 205.000 ;
    END
    PORT
      LAYER Metal5 ;
        RECT 74.000 230.000 75.000 245.000 ;
    END
    PORT
      LAYER Metal5 ;
        RECT 74.000 286.000 75.000 293.000 ;
    END
    PORT
      LAYER Metal5 ;
        RECT 74.000 302.000 75.000 309.000 ;
    END
    PORT
      LAYER Metal5 ;
        RECT 74.000 326.000 75.000 333.000 ;
    END
    PORT
      LAYER Metal5 ;
        RECT 74.000 342.000 75.000 348.390 ;
    END
    PORT
      LAYER Metal4 ;
        RECT 74.000 102.000 75.000 117.000 ;
    END
    PORT
      LAYER Metal4 ;
        RECT 74.000 86.000 75.000 101.000 ;
    END
    PORT
      LAYER Metal4 ;
        RECT 74.000 70.000 75.000 85.000 ;
    END
    PORT
      LAYER Metal4 ;
        RECT 74.000 126.000 75.000 133.000 ;
    END
    PORT
      LAYER Metal4 ;
        RECT 74.000 198.000 75.000 205.000 ;
    END
    PORT
      LAYER Metal4 ;
        RECT 74.000 230.000 75.000 245.000 ;
    END
    PORT
      LAYER Metal4 ;
        RECT 74.000 286.000 75.000 293.000 ;
    END
    PORT
      LAYER Metal4 ;
        RECT 74.000 302.000 75.000 309.000 ;
    END
    PORT
      LAYER Metal4 ;
        RECT 74.000 326.000 75.000 333.000 ;
    END
    PORT
      LAYER Metal4 ;
        RECT 74.000 342.000 75.000 348.390 ;
    END
    PORT
      LAYER Metal3 ;
        RECT 74.000 102.000 75.000 117.000 ;
    END
    PORT
      LAYER Metal3 ;
        RECT 74.000 86.000 75.000 101.000 ;
    END
    PORT
      LAYER Metal3 ;
        RECT 74.000 70.000 75.000 85.000 ;
    END
    PORT
      LAYER Metal3 ;
        RECT 74.000 126.000 75.000 133.000 ;
    END
    PORT
      LAYER Metal3 ;
        RECT 74.000 198.000 75.000 205.000 ;
    END
    PORT
      LAYER Metal3 ;
        RECT 74.000 230.000 75.000 245.000 ;
    END
    PORT
      LAYER Metal3 ;
        RECT 74.000 286.000 75.000 293.000 ;
    END
    PORT
      LAYER Metal3 ;
        RECT 74.000 302.000 75.000 309.000 ;
    END
    PORT
      LAYER Metal3 ;
        RECT 74.000 326.000 75.000 333.000 ;
    END
    PORT
      LAYER Metal3 ;
        RECT 74.000 342.000 75.000 348.390 ;
    END
    PORT
      LAYER Metal3 ;
        RECT 0.000 342.000 1.000 348.390 ;
    END
    PORT
      LAYER Metal3 ;
        RECT 0.000 326.000 1.000 333.000 ;
    END
    PORT
      LAYER Metal3 ;
        RECT 0.000 302.000 1.000 309.000 ;
    END
    PORT
      LAYER Metal3 ;
        RECT 0.000 286.000 1.000 293.000 ;
    END
    PORT
      LAYER Metal3 ;
        RECT 0.000 230.000 1.000 245.000 ;
    END
    PORT
      LAYER Metal3 ;
        RECT 0.000 198.000 1.000 205.000 ;
    END
    PORT
      LAYER Metal3 ;
        RECT 0.000 126.000 1.000 133.000 ;
    END
    PORT
      LAYER Metal3 ;
        RECT 0.000 70.000 1.000 85.000 ;
    END
    PORT
      LAYER Metal3 ;
        RECT 0.000 86.000 1.000 101.000 ;
    END
    PORT
      LAYER Metal4 ;
        RECT 0.000 342.000 1.000 348.390 ;
    END
    PORT
      LAYER Metal4 ;
        RECT 0.000 326.000 1.000 333.000 ;
    END
    PORT
      LAYER Metal4 ;
        RECT 0.000 302.000 1.000 309.000 ;
    END
    PORT
      LAYER Metal4 ;
        RECT 0.000 286.000 1.000 293.000 ;
    END
    PORT
      LAYER Metal4 ;
        RECT 0.000 230.000 1.000 245.000 ;
    END
    PORT
      LAYER Metal4 ;
        RECT 0.000 198.000 1.000 205.000 ;
    END
    PORT
      LAYER Metal4 ;
        RECT 0.000 126.000 1.000 133.000 ;
    END
    PORT
      LAYER Metal4 ;
        RECT 0.000 70.000 1.000 85.000 ;
    END
    PORT
      LAYER Metal4 ;
        RECT 0.000 86.000 1.000 101.000 ;
    END
    PORT
      LAYER Metal5 ;
        RECT 0.000 342.000 1.000 348.390 ;
    END
    PORT
      LAYER Metal5 ;
        RECT 0.000 326.000 1.000 333.000 ;
    END
    PORT
      LAYER Metal5 ;
        RECT 0.000 302.000 1.000 309.000 ;
    END
    PORT
      LAYER Metal5 ;
        RECT 0.000 286.000 1.000 293.000 ;
    END
    PORT
      LAYER Metal5 ;
        RECT 0.000 230.000 1.000 245.000 ;
    END
    PORT
      LAYER Metal5 ;
        RECT 0.000 198.000 1.000 205.000 ;
    END
    PORT
      LAYER Metal5 ;
        RECT 0.000 126.000 1.000 133.000 ;
    END
    PORT
      LAYER Metal5 ;
        RECT 0.000 70.000 1.000 85.000 ;
    END
    PORT
      LAYER Metal5 ;
        RECT 0.000 86.000 1.000 101.000 ;
    END
    PORT
      LAYER Metal5 ;
        RECT 0.000 102.000 1.000 117.000 ;
    END
    PORT
      LAYER Metal4 ;
        RECT 0.000 102.000 1.000 117.000 ;
    END
    PORT
      LAYER Metal3 ;
        RECT 0.000 102.000 1.000 117.000 ;
    END
  END DVSS
  PIN PAD
    DIRECTION INPUT ;
    USE SIGNAL ;
    PORT
      LAYER Metal5 ;
        RECT 25.000 20.000 50.000 45.000 ;
    END
  END PAD
  PIN PD
    DIRECTION INPUT ;
    USE SIGNAL ;
    PORT
      LAYER Metal2 ;
        RECT 10.330 329.950 10.710 350.000 ;
    END
  END PD
  PIN PU
    DIRECTION INPUT ;
    USE SIGNAL ;
    PORT
      LAYER Metal2 ;
        RECT 5.965 330.270 6.345 350.000 ;
    END
  END PU
  PIN VDD
    DIRECTION INOUT ;
    USE POWER ;
    PORT
      LAYER Metal5 ;
        RECT 74.000 254.000 75.000 261.000 ;
    END
    PORT
      LAYER Metal5 ;
        RECT 74.000 310.000 75.000 317.000 ;
    END
    PORT
      LAYER Metal4 ;
        RECT 74.000 254.000 75.000 261.000 ;
    END
    PORT
      LAYER Metal4 ;
        RECT 74.000 310.000 75.000 317.000 ;
    END
    PORT
      LAYER Metal3 ;
        RECT 74.000 254.000 75.000 261.000 ;
    END
    PORT
      LAYER Metal3 ;
        RECT 74.000 310.000 75.000 317.000 ;
    END
    PORT
      LAYER Metal3 ;
        RECT 0.000 310.000 1.000 317.000 ;
    END
    PORT
      LAYER Metal4 ;
        RECT 0.000 310.000 1.000 317.000 ;
    END
    PORT
      LAYER Metal5 ;
        RECT 0.000 310.000 1.000 317.000 ;
    END
    PORT
      LAYER Metal5 ;
        RECT 0.000 254.000 1.000 261.000 ;
    END
    PORT
      LAYER Metal4 ;
        RECT 0.000 254.000 1.000 261.000 ;
    END
    PORT
      LAYER Metal3 ;
        RECT 0.000 254.000 1.000 261.000 ;
    END
  END VDD
  PIN VSS
    DIRECTION INOUT ;
    USE GROUND ;
    PORT
      LAYER Metal5 ;
        RECT 74.000 246.000 75.000 253.000 ;
    END
    PORT
      LAYER Metal5 ;
        RECT 74.000 318.000 75.000 325.000 ;
    END
    PORT
      LAYER Metal4 ;
        RECT 74.000 246.000 75.000 253.000 ;
    END
    PORT
      LAYER Metal4 ;
        RECT 74.000 318.000 75.000 325.000 ;
    END
    PORT
      LAYER Metal3 ;
        RECT 74.000 246.000 75.000 253.000 ;
    END
    PORT
      LAYER Metal3 ;
        RECT 74.000 318.000 75.000 325.000 ;
    END
    PORT
      LAYER Metal3 ;
        RECT 0.000 318.000 1.000 325.000 ;
    END
    PORT
      LAYER Metal4 ;
        RECT 0.000 318.000 1.000 325.000 ;
    END
    PORT
      LAYER Metal5 ;
        RECT 0.000 318.000 1.000 325.000 ;
    END
    PORT
      LAYER Metal5 ;
        RECT 0.000 246.000 1.000 253.000 ;
    END
    PORT
      LAYER Metal4 ;
        RECT 0.000 246.000 1.000 253.000 ;
    END
    PORT
      LAYER Metal3 ;
        RECT 0.000 246.000 1.000 253.000 ;
    END
  END VSS
  PIN Y
    DIRECTION OUTPUT ;
    USE SIGNAL ;
    PORT
      LAYER Metal2 ;
        RECT 70.860 319.750 71.240 350.000 ;
    END
  END Y
  OBS
      LAYER Metal1 ;
        RECT -0.160 65.540 75.160 349.785 ;
      LAYER Metal2 ;
        RECT 0.000 329.970 5.665 348.695 ;
        RECT 6.645 329.970 10.030 348.695 ;
        RECT 0.000 329.650 10.030 329.970 ;
        RECT 11.010 329.650 70.560 348.695 ;
        RECT 0.000 319.450 70.560 329.650 ;
        RECT 71.540 319.450 75.000 348.695 ;
        RECT 0.000 0.000 75.000 319.450 ;
      LAYER Metal3 ;
        RECT 1.300 341.700 73.700 348.390 ;
        RECT 1.000 341.300 74.000 341.700 ;
        RECT 1.300 333.700 73.700 341.300 ;
        RECT 1.000 333.300 74.000 333.700 ;
        RECT 1.300 325.700 73.700 333.300 ;
        RECT 1.000 325.300 74.000 325.700 ;
        RECT 1.300 317.700 73.700 325.300 ;
        RECT 1.000 317.300 74.000 317.700 ;
        RECT 1.300 309.700 73.700 317.300 ;
        RECT 1.000 309.300 74.000 309.700 ;
        RECT 1.300 301.700 73.700 309.300 ;
        RECT 1.000 301.300 74.000 301.700 ;
        RECT 1.300 293.700 73.700 301.300 ;
        RECT 1.000 293.300 74.000 293.700 ;
        RECT 1.300 285.700 73.700 293.300 ;
        RECT 1.000 285.300 74.000 285.700 ;
        RECT 1.300 277.700 73.700 285.300 ;
        RECT 1.000 277.300 74.000 277.700 ;
        RECT 1.300 269.700 73.700 277.300 ;
        RECT 1.000 269.300 74.000 269.700 ;
        RECT 1.300 261.700 73.700 269.300 ;
        RECT 1.000 261.300 74.000 261.700 ;
        RECT 1.300 253.700 73.700 261.300 ;
        RECT 1.000 253.300 74.000 253.700 ;
        RECT 1.300 245.700 73.700 253.300 ;
        RECT 1.000 245.300 74.000 245.700 ;
        RECT 1.300 229.700 73.700 245.300 ;
        RECT 1.000 229.300 74.000 229.700 ;
        RECT 1.300 213.700 73.700 229.300 ;
        RECT 1.000 213.300 74.000 213.700 ;
        RECT 1.300 205.700 73.700 213.300 ;
        RECT 1.000 205.300 74.000 205.700 ;
        RECT 1.300 197.700 73.700 205.300 ;
        RECT 1.000 197.300 74.000 197.700 ;
        RECT 1.300 181.700 73.700 197.300 ;
        RECT 1.000 181.300 74.000 181.700 ;
        RECT 1.300 165.700 73.700 181.300 ;
        RECT 1.000 165.300 74.000 165.700 ;
        RECT 1.300 149.700 73.700 165.300 ;
        RECT 1.000 149.300 74.000 149.700 ;
        RECT 1.300 133.700 73.700 149.300 ;
        RECT 1.000 133.300 74.000 133.700 ;
        RECT 1.300 125.700 73.700 133.300 ;
        RECT 1.000 125.300 74.000 125.700 ;
        RECT 1.300 117.700 73.700 125.300 ;
        RECT 1.000 117.300 74.000 117.700 ;
        RECT 1.300 101.700 73.700 117.300 ;
        RECT 1.000 101.300 74.000 101.700 ;
        RECT 1.300 85.700 73.700 101.300 ;
        RECT 1.000 85.300 74.000 85.700 ;
        RECT 1.300 69.700 73.700 85.300 ;
        RECT 1.000 0.000 74.000 69.700 ;
      LAYER Metal4 ;
        RECT 1.300 341.700 73.700 348.390 ;
        RECT 1.000 341.300 74.000 341.700 ;
        RECT 1.300 333.700 73.700 341.300 ;
        RECT 1.000 333.300 74.000 333.700 ;
        RECT 1.300 325.700 73.700 333.300 ;
        RECT 1.000 325.300 74.000 325.700 ;
        RECT 1.300 317.700 73.700 325.300 ;
        RECT 1.000 317.300 74.000 317.700 ;
        RECT 1.300 309.700 73.700 317.300 ;
        RECT 1.000 309.300 74.000 309.700 ;
        RECT 1.300 301.700 73.700 309.300 ;
        RECT 1.000 301.300 74.000 301.700 ;
        RECT 1.300 293.700 73.700 301.300 ;
        RECT 1.000 293.300 74.000 293.700 ;
        RECT 1.300 285.700 73.700 293.300 ;
        RECT 1.000 285.300 74.000 285.700 ;
        RECT 1.300 277.700 73.700 285.300 ;
        RECT 1.000 277.300 74.000 277.700 ;
        RECT 1.300 269.700 73.700 277.300 ;
        RECT 1.000 269.300 74.000 269.700 ;
        RECT 1.300 261.700 73.700 269.300 ;
        RECT 1.000 261.300 74.000 261.700 ;
        RECT 1.300 253.700 73.700 261.300 ;
        RECT 1.000 253.300 74.000 253.700 ;
        RECT 1.300 245.700 73.700 253.300 ;
        RECT 1.000 245.300 74.000 245.700 ;
        RECT 1.300 229.700 73.700 245.300 ;
        RECT 1.000 229.300 74.000 229.700 ;
        RECT 1.300 213.700 73.700 229.300 ;
        RECT 1.000 213.300 74.000 213.700 ;
        RECT 1.300 205.700 73.700 213.300 ;
        RECT 1.000 205.300 74.000 205.700 ;
        RECT 1.300 197.700 73.700 205.300 ;
        RECT 1.000 197.300 74.000 197.700 ;
        RECT 1.300 181.700 73.700 197.300 ;
        RECT 1.000 181.300 74.000 181.700 ;
        RECT 1.300 165.700 73.700 181.300 ;
        RECT 1.000 165.300 74.000 165.700 ;
        RECT 1.300 149.700 73.700 165.300 ;
        RECT 1.000 149.300 74.000 149.700 ;
        RECT 1.300 133.700 73.700 149.300 ;
        RECT 1.000 133.300 74.000 133.700 ;
        RECT 1.300 125.700 73.700 133.300 ;
        RECT 1.000 125.300 74.000 125.700 ;
        RECT 1.300 117.700 73.700 125.300 ;
        RECT 1.000 117.300 74.000 117.700 ;
        RECT 1.300 101.700 73.700 117.300 ;
        RECT 1.000 101.300 74.000 101.700 ;
        RECT 1.300 85.700 73.700 101.300 ;
        RECT 1.000 85.300 74.000 85.700 ;
        RECT 1.300 69.700 73.700 85.300 ;
        RECT 1.000 0.000 74.000 69.700 ;
      LAYER Metal5 ;
        RECT 1.500 69.500 73.500 348.390 ;
        RECT 1.000 45.500 74.000 69.500 ;
        RECT 1.000 19.500 24.500 45.500 ;
        RECT 50.500 19.500 74.000 45.500 ;
        RECT 1.000 0.000 74.000 19.500 ;
  END
END gf180mcu_fd_io__in_c

#--------EOF---------

#--------EOF---------

MACRO gf180mcu_fd_io__in_s
  CLASS PAD INPUT ;
  FOREIGN gf180mcu_fd_io__in_s ;
  ORIGIN 0.000 0.000 ;
  SIZE 75.000 BY 350.000 ;
  SYMMETRY X Y R90 ;
  PIN DVDD
    DIRECTION INOUT ;
    USE POWER ;
    PORT
      LAYER Metal5 ;
        RECT 74.000 118.000 75.000 125.000 ;
    END
    PORT
      LAYER Metal5 ;
        RECT 74.000 182.000 75.000 197.000 ;
    END
    PORT
      LAYER Metal5 ;
        RECT 74.000 166.000 75.000 181.000 ;
    END
    PORT
      LAYER Metal5 ;
        RECT 74.000 150.000 75.000 165.000 ;
    END
    PORT
      LAYER Metal5 ;
        RECT 74.000 134.000 75.000 149.000 ;
    END
    PORT
      LAYER Metal5 ;
        RECT 74.000 214.000 75.000 229.000 ;
    END
    PORT
      LAYER Metal5 ;
        RECT 74.000 206.000 75.000 213.000 ;
    END
    PORT
      LAYER Metal5 ;
        RECT 74.000 278.000 75.000 285.000 ;
    END
    PORT
      LAYER Metal5 ;
        RECT 74.000 270.000 75.000 277.000 ;
    END
    PORT
      LAYER Metal5 ;
        RECT 74.000 262.000 75.000 269.000 ;
    END
    PORT
      LAYER Metal5 ;
        RECT 74.000 294.000 75.000 301.000 ;
    END
    PORT
      LAYER Metal5 ;
        RECT 74.000 334.000 75.000 341.000 ;
    END
    PORT
      LAYER Metal4 ;
        RECT 74.000 118.000 75.000 125.000 ;
    END
    PORT
      LAYER Metal4 ;
        RECT 74.000 182.000 75.000 197.000 ;
    END
    PORT
      LAYER Metal4 ;
        RECT 74.000 166.000 75.000 181.000 ;
    END
    PORT
      LAYER Metal4 ;
        RECT 74.000 150.000 75.000 165.000 ;
    END
    PORT
      LAYER Metal4 ;
        RECT 74.000 134.000 75.000 149.000 ;
    END
    PORT
      LAYER Metal4 ;
        RECT 74.000 214.000 75.000 229.000 ;
    END
    PORT
      LAYER Metal4 ;
        RECT 74.000 206.000 75.000 213.000 ;
    END
    PORT
      LAYER Metal4 ;
        RECT 74.000 278.000 75.000 285.000 ;
    END
    PORT
      LAYER Metal4 ;
        RECT 74.000 270.000 75.000 277.000 ;
    END
    PORT
      LAYER Metal4 ;
        RECT 74.000 262.000 75.000 269.000 ;
    END
    PORT
      LAYER Metal4 ;
        RECT 74.000 294.000 75.000 301.000 ;
    END
    PORT
      LAYER Metal4 ;
        RECT 74.000 334.000 75.000 341.000 ;
    END
    PORT
      LAYER Metal3 ;
        RECT 74.000 118.000 75.000 125.000 ;
    END
    PORT
      LAYER Metal3 ;
        RECT 74.000 182.000 75.000 197.000 ;
    END
    PORT
      LAYER Metal3 ;
        RECT 74.000 166.000 75.000 181.000 ;
    END
    PORT
      LAYER Metal3 ;
        RECT 74.000 150.000 75.000 165.000 ;
    END
    PORT
      LAYER Metal3 ;
        RECT 74.000 134.000 75.000 149.000 ;
    END
    PORT
      LAYER Metal3 ;
        RECT 74.000 214.000 75.000 229.000 ;
    END
    PORT
      LAYER Metal3 ;
        RECT 74.000 206.000 75.000 213.000 ;
    END
    PORT
      LAYER Metal3 ;
        RECT 74.000 278.000 75.000 285.000 ;
    END
    PORT
      LAYER Metal3 ;
        RECT 74.000 270.000 75.000 277.000 ;
    END
    PORT
      LAYER Metal3 ;
        RECT 74.000 262.000 75.000 269.000 ;
    END
    PORT
      LAYER Metal3 ;
        RECT 74.000 294.000 75.000 301.000 ;
    END
    PORT
      LAYER Metal3 ;
        RECT 74.000 334.000 75.000 341.000 ;
    END
    PORT
      LAYER Metal3 ;
        RECT 0.000 334.000 1.000 341.000 ;
    END
    PORT
      LAYER Metal3 ;
        RECT 0.000 294.000 1.000 301.000 ;
    END
    PORT
      LAYER Metal3 ;
        RECT 0.000 262.000 1.000 269.000 ;
    END
    PORT
      LAYER Metal3 ;
        RECT 0.000 270.000 1.000 277.000 ;
    END
    PORT
      LAYER Metal3 ;
        RECT 0.000 278.000 1.000 285.000 ;
    END
    PORT
      LAYER Metal3 ;
        RECT 0.000 206.000 1.000 213.000 ;
    END
    PORT
      LAYER Metal3 ;
        RECT 0.000 214.000 1.000 229.000 ;
    END
    PORT
      LAYER Metal3 ;
        RECT 0.000 134.000 1.000 149.000 ;
    END
    PORT
      LAYER Metal3 ;
        RECT 0.000 150.000 1.000 165.000 ;
    END
    PORT
      LAYER Metal3 ;
        RECT 0.000 166.000 1.000 181.000 ;
    END
    PORT
      LAYER Metal3 ;
        RECT 0.000 182.000 1.000 197.000 ;
    END
    PORT
      LAYER Metal4 ;
        RECT 0.000 334.000 1.000 341.000 ;
    END
    PORT
      LAYER Metal4 ;
        RECT 0.000 294.000 1.000 301.000 ;
    END
    PORT
      LAYER Metal4 ;
        RECT 0.000 262.000 1.000 269.000 ;
    END
    PORT
      LAYER Metal4 ;
        RECT 0.000 270.000 1.000 277.000 ;
    END
    PORT
      LAYER Metal4 ;
        RECT 0.000 278.000 1.000 285.000 ;
    END
    PORT
      LAYER Metal4 ;
        RECT 0.000 206.000 1.000 213.000 ;
    END
    PORT
      LAYER Metal4 ;
        RECT 0.000 214.000 1.000 229.000 ;
    END
    PORT
      LAYER Metal4 ;
        RECT 0.000 134.000 1.000 149.000 ;
    END
    PORT
      LAYER Metal4 ;
        RECT 0.000 150.000 1.000 165.000 ;
    END
    PORT
      LAYER Metal4 ;
        RECT 0.000 166.000 1.000 181.000 ;
    END
    PORT
      LAYER Metal4 ;
        RECT 0.000 182.000 1.000 197.000 ;
    END
    PORT
      LAYER Metal5 ;
        RECT 0.000 334.000 1.000 341.000 ;
    END
    PORT
      LAYER Metal5 ;
        RECT 0.000 294.000 1.000 301.000 ;
    END
    PORT
      LAYER Metal5 ;
        RECT 0.000 262.000 1.000 269.000 ;
    END
    PORT
      LAYER Metal5 ;
        RECT 0.000 270.000 1.000 277.000 ;
    END
    PORT
      LAYER Metal5 ;
        RECT 0.000 278.000 1.000 285.000 ;
    END
    PORT
      LAYER Metal5 ;
        RECT 0.000 206.000 1.000 213.000 ;
    END
    PORT
      LAYER Metal5 ;
        RECT 0.000 214.000 1.000 229.000 ;
    END
    PORT
      LAYER Metal5 ;
        RECT 0.000 134.000 1.000 149.000 ;
    END
    PORT
      LAYER Metal5 ;
        RECT 0.000 150.000 1.000 165.000 ;
    END
    PORT
      LAYER Metal5 ;
        RECT 0.000 166.000 1.000 181.000 ;
    END
    PORT
      LAYER Metal5 ;
        RECT 0.000 182.000 1.000 197.000 ;
    END
    PORT
      LAYER Metal5 ;
        RECT 0.000 118.000 1.000 125.000 ;
    END
    PORT
      LAYER Metal4 ;
        RECT 0.000 118.000 1.000 125.000 ;
    END
    PORT
      LAYER Metal3 ;
        RECT 0.000 118.000 1.000 125.000 ;
    END
  END DVDD
  PIN DVSS
    DIRECTION INOUT ;
    USE GROUND ;
    PORT
      LAYER Metal5 ;
        RECT 74.000 102.000 75.000 117.000 ;
    END
    PORT
      LAYER Metal5 ;
        RECT 74.000 86.000 75.000 101.000 ;
    END
    PORT
      LAYER Metal5 ;
        RECT 74.000 70.000 75.000 85.000 ;
    END
    PORT
      LAYER Metal5 ;
        RECT 74.000 126.000 75.000 133.000 ;
    END
    PORT
      LAYER Metal5 ;
        RECT 74.000 198.000 75.000 205.000 ;
    END
    PORT
      LAYER Metal5 ;
        RECT 74.000 230.000 75.000 245.000 ;
    END
    PORT
      LAYER Metal5 ;
        RECT 74.000 286.000 75.000 293.000 ;
    END
    PORT
      LAYER Metal5 ;
        RECT 74.000 302.000 75.000 309.000 ;
    END
    PORT
      LAYER Metal5 ;
        RECT 74.000 326.000 75.000 333.000 ;
    END
    PORT
      LAYER Metal5 ;
        RECT 74.000 342.000 75.000 348.390 ;
    END
    PORT
      LAYER Metal4 ;
        RECT 74.000 102.000 75.000 117.000 ;
    END
    PORT
      LAYER Metal4 ;
        RECT 74.000 86.000 75.000 101.000 ;
    END
    PORT
      LAYER Metal4 ;
        RECT 74.000 70.000 75.000 85.000 ;
    END
    PORT
      LAYER Metal4 ;
        RECT 74.000 126.000 75.000 133.000 ;
    END
    PORT
      LAYER Metal4 ;
        RECT 74.000 198.000 75.000 205.000 ;
    END
    PORT
      LAYER Metal4 ;
        RECT 74.000 230.000 75.000 245.000 ;
    END
    PORT
      LAYER Metal4 ;
        RECT 74.000 286.000 75.000 293.000 ;
    END
    PORT
      LAYER Metal4 ;
        RECT 74.000 302.000 75.000 309.000 ;
    END
    PORT
      LAYER Metal4 ;
        RECT 74.000 326.000 75.000 333.000 ;
    END
    PORT
      LAYER Metal4 ;
        RECT 74.000 342.000 75.000 348.390 ;
    END
    PORT
      LAYER Metal3 ;
        RECT 74.000 102.000 75.000 117.000 ;
    END
    PORT
      LAYER Metal3 ;
        RECT 74.000 86.000 75.000 101.000 ;
    END
    PORT
      LAYER Metal3 ;
        RECT 74.000 70.000 75.000 85.000 ;
    END
    PORT
      LAYER Metal3 ;
        RECT 74.000 126.000 75.000 133.000 ;
    END
    PORT
      LAYER Metal3 ;
        RECT 74.000 198.000 75.000 205.000 ;
    END
    PORT
      LAYER Metal3 ;
        RECT 74.000 230.000 75.000 245.000 ;
    END
    PORT
      LAYER Metal3 ;
        RECT 74.000 286.000 75.000 293.000 ;
    END
    PORT
      LAYER Metal3 ;
        RECT 74.000 302.000 75.000 309.000 ;
    END
    PORT
      LAYER Metal3 ;
        RECT 74.000 326.000 75.000 333.000 ;
    END
    PORT
      LAYER Metal3 ;
        RECT 74.000 342.000 75.000 348.390 ;
    END
    PORT
      LAYER Metal3 ;
        RECT 0.000 342.000 1.000 348.390 ;
    END
    PORT
      LAYER Metal3 ;
        RECT 0.000 326.000 1.000 333.000 ;
    END
    PORT
      LAYER Metal3 ;
        RECT 0.000 302.000 1.000 309.000 ;
    END
    PORT
      LAYER Metal3 ;
        RECT 0.000 286.000 1.000 293.000 ;
    END
    PORT
      LAYER Metal3 ;
        RECT 0.000 230.000 1.000 245.000 ;
    END
    PORT
      LAYER Metal3 ;
        RECT 0.000 198.000 1.000 205.000 ;
    END
    PORT
      LAYER Metal3 ;
        RECT 0.000 126.000 1.000 133.000 ;
    END
    PORT
      LAYER Metal3 ;
        RECT 0.000 70.000 1.000 85.000 ;
    END
    PORT
      LAYER Metal3 ;
        RECT 0.000 86.000 1.000 101.000 ;
    END
    PORT
      LAYER Metal4 ;
        RECT 0.000 342.000 1.000 348.390 ;
    END
    PORT
      LAYER Metal4 ;
        RECT 0.000 326.000 1.000 333.000 ;
    END
    PORT
      LAYER Metal4 ;
        RECT 0.000 302.000 1.000 309.000 ;
    END
    PORT
      LAYER Metal4 ;
        RECT 0.000 286.000 1.000 293.000 ;
    END
    PORT
      LAYER Metal4 ;
        RECT 0.000 230.000 1.000 245.000 ;
    END
    PORT
      LAYER Metal4 ;
        RECT 0.000 198.000 1.000 205.000 ;
    END
    PORT
      LAYER Metal4 ;
        RECT 0.000 126.000 1.000 133.000 ;
    END
    PORT
      LAYER Metal4 ;
        RECT 0.000 70.000 1.000 85.000 ;
    END
    PORT
      LAYER Metal4 ;
        RECT 0.000 86.000 1.000 101.000 ;
    END
    PORT
      LAYER Metal5 ;
        RECT 0.000 342.000 1.000 348.390 ;
    END
    PORT
      LAYER Metal5 ;
        RECT 0.000 326.000 1.000 333.000 ;
    END
    PORT
      LAYER Metal5 ;
        RECT 0.000 302.000 1.000 309.000 ;
    END
    PORT
      LAYER Metal5 ;
        RECT 0.000 286.000 1.000 293.000 ;
    END
    PORT
      LAYER Metal5 ;
        RECT 0.000 230.000 1.000 245.000 ;
    END
    PORT
      LAYER Metal5 ;
        RECT 0.000 198.000 1.000 205.000 ;
    END
    PORT
      LAYER Metal5 ;
        RECT 0.000 126.000 1.000 133.000 ;
    END
    PORT
      LAYER Metal5 ;
        RECT 0.000 70.000 1.000 85.000 ;
    END
    PORT
      LAYER Metal5 ;
        RECT 0.000 86.000 1.000 101.000 ;
    END
    PORT
      LAYER Metal5 ;
        RECT 0.000 102.000 1.000 117.000 ;
    END
    PORT
      LAYER Metal4 ;
        RECT 0.000 102.000 1.000 117.000 ;
    END
    PORT
      LAYER Metal3 ;
        RECT 0.000 102.000 1.000 117.000 ;
    END
  END DVSS
  PIN PAD
    DIRECTION INPUT ;
    USE SIGNAL ;
    PORT
      LAYER Metal5 ;
        RECT 25.000 20.000 50.000 45.000 ;
    END
  END PAD
  PIN PD
    DIRECTION INPUT ;
    USE SIGNAL ;
    PORT
      LAYER Metal2 ;
        RECT 10.330 329.950 10.710 350.000 ;
    END
  END PD
  PIN PU
    DIRECTION INPUT ;
    USE SIGNAL ;
    PORT
      LAYER Metal2 ;
        RECT 5.965 330.270 6.345 350.000 ;
    END
  END PU
  PIN VDD
    DIRECTION INOUT ;
    USE POWER ;
    PORT
      LAYER Metal5 ;
        RECT 74.000 254.000 75.000 261.000 ;
    END
    PORT
      LAYER Metal5 ;
        RECT 74.000 310.000 75.000 317.000 ;
    END
    PORT
      LAYER Metal4 ;
        RECT 74.000 254.000 75.000 261.000 ;
    END
    PORT
      LAYER Metal4 ;
        RECT 74.000 310.000 75.000 317.000 ;
    END
    PORT
      LAYER Metal3 ;
        RECT 74.000 254.000 75.000 261.000 ;
    END
    PORT
      LAYER Metal3 ;
        RECT 74.000 310.000 75.000 317.000 ;
    END
    PORT
      LAYER Metal3 ;
        RECT 0.000 310.000 1.000 317.000 ;
    END
    PORT
      LAYER Metal4 ;
        RECT 0.000 310.000 1.000 317.000 ;
    END
    PORT
      LAYER Metal5 ;
        RECT 0.000 310.000 1.000 317.000 ;
    END
    PORT
      LAYER Metal5 ;
        RECT 0.000 254.000 1.000 261.000 ;
    END
    PORT
      LAYER Metal4 ;
        RECT 0.000 254.000 1.000 261.000 ;
    END
    PORT
      LAYER Metal3 ;
        RECT 0.000 254.000 1.000 261.000 ;
    END
  END VDD
  PIN VSS
    DIRECTION INOUT ;
    USE GROUND ;
    PORT
      LAYER Metal5 ;
        RECT 74.000 246.000 75.000 253.000 ;
    END
    PORT
      LAYER Metal5 ;
        RECT 74.000 318.000 75.000 325.000 ;
    END
    PORT
      LAYER Metal4 ;
        RECT 74.000 246.000 75.000 253.000 ;
    END
    PORT
      LAYER Metal4 ;
        RECT 74.000 318.000 75.000 325.000 ;
    END
    PORT
      LAYER Metal3 ;
        RECT 74.000 246.000 75.000 253.000 ;
    END
    PORT
      LAYER Metal3 ;
        RECT 74.000 318.000 75.000 325.000 ;
    END
    PORT
      LAYER Metal3 ;
        RECT 0.000 318.000 1.000 325.000 ;
    END
    PORT
      LAYER Metal4 ;
        RECT 0.000 318.000 1.000 325.000 ;
    END
    PORT
      LAYER Metal5 ;
        RECT 0.000 318.000 1.000 325.000 ;
    END
    PORT
      LAYER Metal5 ;
        RECT 0.000 246.000 1.000 253.000 ;
    END
    PORT
      LAYER Metal4 ;
        RECT 0.000 246.000 1.000 253.000 ;
    END
    PORT
      LAYER Metal3 ;
        RECT 0.000 246.000 1.000 253.000 ;
    END
  END VSS
  PIN Y
    DIRECTION OUTPUT ;
    USE SIGNAL ;
    PORT
      LAYER Metal2 ;
        RECT 70.860 319.750 71.240 350.000 ;
    END
  END Y
  OBS
      LAYER Metal1 ;
        RECT -0.160 65.540 75.160 349.785 ;
      LAYER Metal2 ;
        RECT 0.000 329.970 5.665 348.695 ;
        RECT 6.645 329.970 10.030 348.695 ;
        RECT 0.000 329.650 10.030 329.970 ;
        RECT 11.010 329.650 70.560 348.695 ;
        RECT 0.000 319.450 70.560 329.650 ;
        RECT 71.540 319.450 75.000 348.695 ;
        RECT 0.000 0.000 75.000 319.450 ;
      LAYER Metal3 ;
        RECT 1.300 341.700 73.700 348.390 ;
        RECT 1.000 341.300 74.000 341.700 ;
        RECT 1.300 333.700 73.700 341.300 ;
        RECT 1.000 333.300 74.000 333.700 ;
        RECT 1.300 325.700 73.700 333.300 ;
        RECT 1.000 325.300 74.000 325.700 ;
        RECT 1.300 317.700 73.700 325.300 ;
        RECT 1.000 317.300 74.000 317.700 ;
        RECT 1.300 309.700 73.700 317.300 ;
        RECT 1.000 309.300 74.000 309.700 ;
        RECT 1.300 301.700 73.700 309.300 ;
        RECT 1.000 301.300 74.000 301.700 ;
        RECT 1.300 293.700 73.700 301.300 ;
        RECT 1.000 293.300 74.000 293.700 ;
        RECT 1.300 285.700 73.700 293.300 ;
        RECT 1.000 285.300 74.000 285.700 ;
        RECT 1.300 277.700 73.700 285.300 ;
        RECT 1.000 277.300 74.000 277.700 ;
        RECT 1.300 269.700 73.700 277.300 ;
        RECT 1.000 269.300 74.000 269.700 ;
        RECT 1.300 261.700 73.700 269.300 ;
        RECT 1.000 261.300 74.000 261.700 ;
        RECT 1.300 253.700 73.700 261.300 ;
        RECT 1.000 253.300 74.000 253.700 ;
        RECT 1.300 245.700 73.700 253.300 ;
        RECT 1.000 245.300 74.000 245.700 ;
        RECT 1.300 229.700 73.700 245.300 ;
        RECT 1.000 229.300 74.000 229.700 ;
        RECT 1.300 213.700 73.700 229.300 ;
        RECT 1.000 213.300 74.000 213.700 ;
        RECT 1.300 205.700 73.700 213.300 ;
        RECT 1.000 205.300 74.000 205.700 ;
        RECT 1.300 197.700 73.700 205.300 ;
        RECT 1.000 197.300 74.000 197.700 ;
        RECT 1.300 181.700 73.700 197.300 ;
        RECT 1.000 181.300 74.000 181.700 ;
        RECT 1.300 165.700 73.700 181.300 ;
        RECT 1.000 165.300 74.000 165.700 ;
        RECT 1.300 149.700 73.700 165.300 ;
        RECT 1.000 149.300 74.000 149.700 ;
        RECT 1.300 133.700 73.700 149.300 ;
        RECT 1.000 133.300 74.000 133.700 ;
        RECT 1.300 125.700 73.700 133.300 ;
        RECT 1.000 125.300 74.000 125.700 ;
        RECT 1.300 117.700 73.700 125.300 ;
        RECT 1.000 117.300 74.000 117.700 ;
        RECT 1.300 101.700 73.700 117.300 ;
        RECT 1.000 101.300 74.000 101.700 ;
        RECT 1.300 85.700 73.700 101.300 ;
        RECT 1.000 85.300 74.000 85.700 ;
        RECT 1.300 69.700 73.700 85.300 ;
        RECT 1.000 0.000 74.000 69.700 ;
      LAYER Metal4 ;
        RECT 1.300 341.700 73.700 348.390 ;
        RECT 1.000 341.300 74.000 341.700 ;
        RECT 1.300 333.700 73.700 341.300 ;
        RECT 1.000 333.300 74.000 333.700 ;
        RECT 1.300 325.700 73.700 333.300 ;
        RECT 1.000 325.300 74.000 325.700 ;
        RECT 1.300 317.700 73.700 325.300 ;
        RECT 1.000 317.300 74.000 317.700 ;
        RECT 1.300 309.700 73.700 317.300 ;
        RECT 1.000 309.300 74.000 309.700 ;
        RECT 1.300 301.700 73.700 309.300 ;
        RECT 1.000 301.300 74.000 301.700 ;
        RECT 1.300 293.700 73.700 301.300 ;
        RECT 1.000 293.300 74.000 293.700 ;
        RECT 1.300 285.700 73.700 293.300 ;
        RECT 1.000 285.300 74.000 285.700 ;
        RECT 1.300 277.700 73.700 285.300 ;
        RECT 1.000 277.300 74.000 277.700 ;
        RECT 1.300 269.700 73.700 277.300 ;
        RECT 1.000 269.300 74.000 269.700 ;
        RECT 1.300 261.700 73.700 269.300 ;
        RECT 1.000 261.300 74.000 261.700 ;
        RECT 1.300 253.700 73.700 261.300 ;
        RECT 1.000 253.300 74.000 253.700 ;
        RECT 1.300 245.700 73.700 253.300 ;
        RECT 1.000 245.300 74.000 245.700 ;
        RECT 1.300 229.700 73.700 245.300 ;
        RECT 1.000 229.300 74.000 229.700 ;
        RECT 1.300 213.700 73.700 229.300 ;
        RECT 1.000 213.300 74.000 213.700 ;
        RECT 1.300 205.700 73.700 213.300 ;
        RECT 1.000 205.300 74.000 205.700 ;
        RECT 1.300 197.700 73.700 205.300 ;
        RECT 1.000 197.300 74.000 197.700 ;
        RECT 1.300 181.700 73.700 197.300 ;
        RECT 1.000 181.300 74.000 181.700 ;
        RECT 1.300 165.700 73.700 181.300 ;
        RECT 1.000 165.300 74.000 165.700 ;
        RECT 1.300 149.700 73.700 165.300 ;
        RECT 1.000 149.300 74.000 149.700 ;
        RECT 1.300 133.700 73.700 149.300 ;
        RECT 1.000 133.300 74.000 133.700 ;
        RECT 1.300 125.700 73.700 133.300 ;
        RECT 1.000 125.300 74.000 125.700 ;
        RECT 1.300 117.700 73.700 125.300 ;
        RECT 1.000 117.300 74.000 117.700 ;
        RECT 1.300 101.700 73.700 117.300 ;
        RECT 1.000 101.300 74.000 101.700 ;
        RECT 1.300 85.700 73.700 101.300 ;
        RECT 1.000 85.300 74.000 85.700 ;
        RECT 1.300 69.700 73.700 85.300 ;
        RECT 1.000 0.000 74.000 69.700 ;
      LAYER Metal5 ;
        RECT 1.500 69.500 73.500 348.390 ;
        RECT 1.000 45.500 74.000 69.500 ;
        RECT 1.000 19.500 24.500 45.500 ;
        RECT 50.500 19.500 74.000 45.500 ;
        RECT 1.000 0.000 74.000 19.500 ;
  END
END gf180mcu_fd_io__in_s

#--------EOF---------

#--------EOF---------


END LIBRARY
